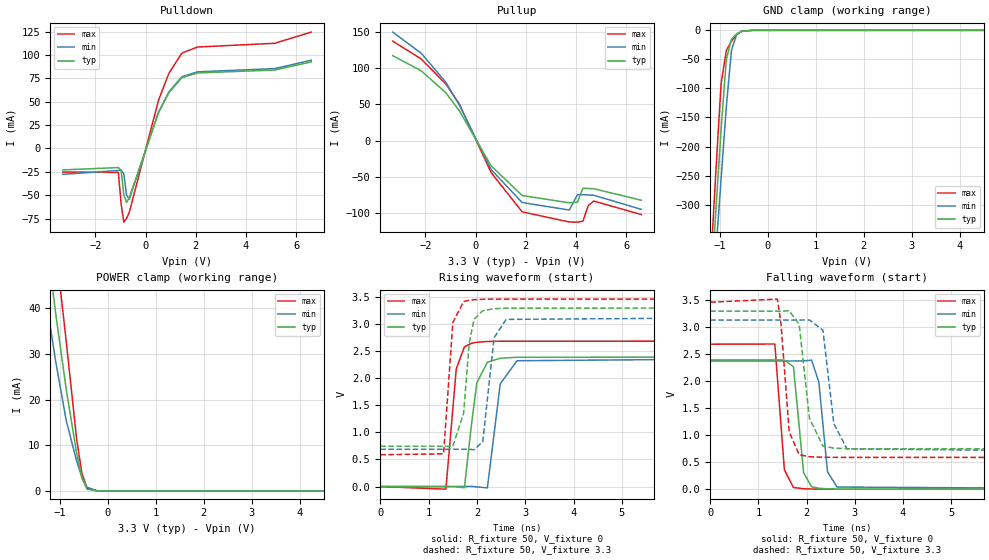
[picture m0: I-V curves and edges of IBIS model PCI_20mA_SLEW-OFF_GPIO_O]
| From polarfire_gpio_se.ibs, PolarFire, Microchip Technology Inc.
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|   Model PCI_20mA_SLEW-OFF_GPIO_O
[Model]   PCI_20mA_SLEW-OFF_GPIO_O
Model_type   Output
Polarity   Non-Inverting
Enable   Active-High
Cref =   5p
Rref =   25
|   typ   min   max
C_comp_pullup   2.605e-12   2.605e-12   2.76e-12
C_comp_pulldown  2.605e-12   2.605e-12   2.76e-12
| Vmeas and Vref depend on the measuring edge
| Rising Edge, uncomment the following
Vmeas =   0.9405V
Vref =   0.000V
| Falling Edge, uncomment the following
|Vmeas =   2.0295V
|Vref =   3.300V
[Model Spec]
Vmeas_rising   0.9405V   0.8934V   0.9875V
Vref_rising   0.000V   0.000V   0.000V
Vmeas_falling   2.0295V   1.9280V   2.1309V
Vref_falling   3.300V   3.135V   3.465V
[Temperature Range]  25C   100C   -40C
[Voltage Range]  3.3   3.135   3.465
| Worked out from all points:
|   slope of the pulldown table from 0 to 0.495 V, typ, clamps not added: 13.4 ohm
|   slope of the pullup table from 0 to 0.495 V, typ, clamps not added: 17.3 ohm
|   GND clamp passes 1 mA (typ) near -0.51 V on its own axis
|   POWER clamp passes 1 mA (typ) near -0.46 V on its own axis
|   rising waveform, R_fixture 50, V_fixture 0: 20-80 % time 180ps typ, 184ps min, 138ps max; typ from 0 V to 2.39 V
|   rising waveform, R_fixture 50, V_fixture 3.3: 20-80 % time 145ps typ, 168ps min, 109ps max; typ from 0.745 V to 3.3 V
|   falling waveform, R_fixture 50, V_fixture 0: 20-80 % time 128ps typ, 142ps min, 96.9ps max; typ from 2.39 V to 0 V
|   falling waveform, R_fixture 50, V_fixture 3.3: 20-80 % time 192ps typ, 194ps min, 144ps max; typ from 3.3 V to 0.745 V
[GND Clamp]
| Voltage   I(typ)   I(min)   I(max)
-3.3V     -3.213A    -2.957A    -3.541A
-1.191V   -450mA     -505.3mA   -401.1mA
-1.083V   -310.2mA   -380.8mA   -242.7mA
-974.5mV  -170.4mA   -256.4mA   -91.54mA
-866.2mV  -50.48mA   -132.2mA   -34.88mA
-758mV    -15.08mA   -34.24mA   -18.56mA
-649.7mV  -5.883mA   -6.714mA   -7.365mA
-541.4mV  -1.389mA   -1.466mA   -1.709mA
-324.8mV  -3.553uA   -9.504uA   -2.339uA
6.6V      0A         0A         0A
[POWER Clamp]
| Voltage   I(typ)   I(min)   I(max)
-3.3V     320.3mA    266.4mA    379mA
-1.624V   89.11mA    69.3mA     113.8mA
-1.408V   67.23mA    51.37mA    87.82mA
-1.299V   57.08mA    43.14mA    75.67mA
-1.191V   47.51mA    35.38mA    63.94mA
-1.083V   38.51mA    28.09mA    52.96mA
-866.2mV  22.14mA    15.36mA    32.61mA
-649.7mV  8.213mA    6.528mA    11.28mA
-541.4mV  2.791mA    3.019mA    3.88mA
-433.1mV  359.8uA    815.7uA    615.5uA
-216.6mV  159.8nA    4.578uA    2.748uA
6.6V      0A         0A         0A
[Pullup]
| Voltage   I(typ)   I(min)   I(max)
-3.3V     117mA      149.5mA    137mA
-2.166V   96.15mA    120.4mA    112.5mA
-1.191V   66.14mA    80.61mA    78.16mA
-649.7mV  41.23mA    49.17mA    50.55mA
618.8mV   -34.87mA   -39.98mA   -44.1mA
1.856V    -75.75mA   -85.44mA   -98.28mA
3.733V    -85.83mA   -95.77mA   -112.2mA
4.058V    -84.98mA   -74.55mA   -112.5mA
4.275V    -65.71mA   -74.6mA    -111.1mA
4.491V    -66.04mA   -74.99mA   -89.28mA
4.708V    -66.38mA   -75.37mA   -83.39mA
6.6V      -82.26mA   -94.83mA   -102mA
[Pulldown]
| Voltage   I(typ)   I(min)   I(max)
-3.3V     -22.95mA   -27.72mA   -25.22mA
-1.083V   -20.45mA   -23.58mA   -25.68mA
-974.5mV  -23.56mA   -23.09mA   -59.29mA
-866.2mV  -49.58mA   -27.1mA    -78.93mA
-758mV    -57.79mA   -49.98mA   -74.96mA
-649.7mV  -52.66mA   -54.3mA    -68.46mA
515.6mV   38.32mA    38.87mA    51.68mA
928.1mV   59.63mA    60.53mA    80.39mA
1.444V    75.7mA     76.75mA    102.1mA
2.062V    80.85mA    82.04mA    108.6mA
5.141V    83.98mA    85.49mA    112.6mA
6.6V      92.71mA    94.49mA    124.6mA
[Ramp]
dV/dt_r   1.43642/0.180403n  1.42548/0.18362n  1.61223/0.137715n
dV/dt_f   1.53328/0.192092n  1.46781/0.19408n  1.72588/0.143667n
R_load = 50
[Rising Waveform]
R_fixture = 50
V_fixture = 0
V_fixture_min = 0
V_fixture_max = 0
| Time   V(typ)   V(min)   V(max)
0s        32.7nV     23.65nV    88.85nV
1.358ns   758.9uV    498.5uV    -48.53mV
1.573ns   -5.442mV   577.4uV    2.174V
1.741ns   -23.01mV   639.1uV    2.581V
1.886ns   1.136V     2.761mV    2.648V
1.998ns   1.918V     -5.65mV    2.666V
2.217ns   2.298V     -25.15mV   2.681V
2.483ns   2.371V     1.897V     2.686V
2.83ns    2.389V     2.325V     2.686V
10ns      2.394V     2.376V     2.687V
[Rising Waveform]
R_fixture = 50
V_fixture = 3.3
V_fixture_min = 3.135
V_fixture_max = 3.465
| Time   V(typ)   V(min)   V(max)
0s        744.5mV    688.6mV    588.5mV
1.31ns    744.8mV    689.2mV    603.4mV
1.502ns   741.6mV    689.3mV    3.033V
1.725ns   1.357V     689.4mV    3.419V
1.84ns    2.649V     689.6mV    3.443V
1.941ns   3.093V     680.1mV    3.453V
2.121ns   3.25V      830.4mV    3.461V
2.356ns   3.287V     2.752V     3.464V
2.604ns   3.296V     3.089V     3.465V
10ns      3.3V       3.135V     3.465V
[Falling Waveform]
R_fixture = 50
V_fixture = 0
V_fixture_min = 0
V_fixture_max = 0
| Time   V(typ)   V(min)   V(max)
0s        2.394V     2.376V     2.687V
1.34ns    2.394V     2.376V     2.691V
1.538ns   2.394V     2.376V     357.7mV
1.726ns   2.271V     2.376V     30.74mV
1.937ns   303.7mV    2.377V     8.074mV
2.103ns   44.1mV     2.392V     3.21mV
2.253ns   16.72mV    1.987V     1.497mV
2.433ns   6.341mV    323.4mV    704.6uV
2.629ns   2.511mV    39.81mV    686.3uV
10ns      499.5nV    2.786uV    152.4nV
[Falling Waveform]
R_fixture = 50
V_fixture = 3.3
V_fixture_min = 3.135
V_fixture_max = 3.465
| Time   V(typ)   V(min)   V(max)
0s        3.3V       3.135V     3.465V
1.393ns   3.299V     3.135V     3.524V
1.467ns   3.299V     3.135V     3.078V
1.638ns   3.308V     3.135V     1.062V
1.846ns   3.051V     3.135V     639mV
2.058ns   1.314V     3.137V     601.6mV
2.338ns   799.5mV    2.947V     591.6mV
2.565ns   760.8mV    1.213V     589.5mV
2.838ns   749mV      747.2mV    588.8mV
10ns      744.5mV    688.6mV    588.5mV
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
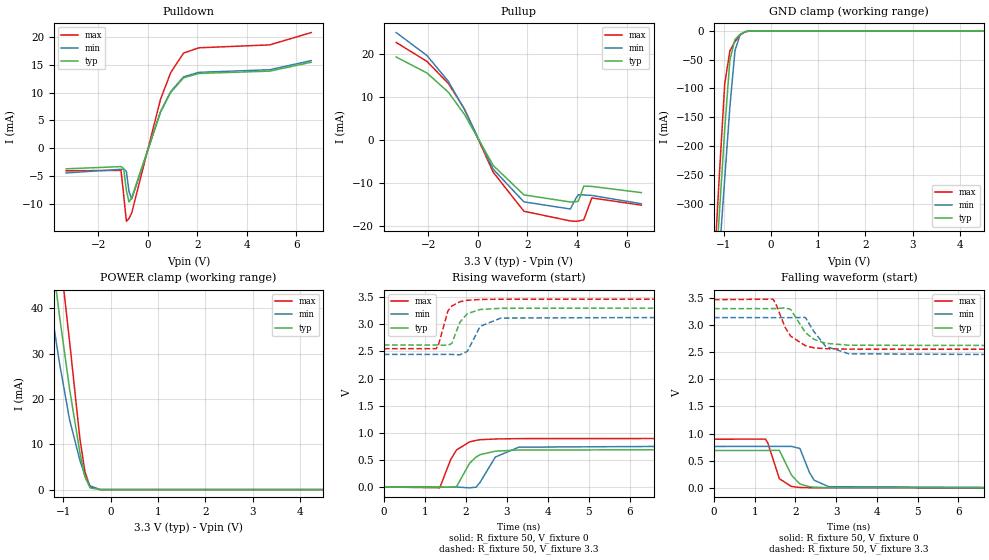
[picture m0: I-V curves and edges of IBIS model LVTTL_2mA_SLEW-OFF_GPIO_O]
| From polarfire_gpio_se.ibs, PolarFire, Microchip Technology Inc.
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|   Model LVTTL_2mA_SLEW-OFF_GPIO_O
[Model]   LVTTL_2mA_SLEW-OFF_GPIO_O
Model_type   Output
Polarity   Non-Inverting
Enable   Active-High
Vmeas =   1.65
Cref =   5p
Rref =   1M
|   typ   min   max
C_comp_pullup   2.605e-12   2.605e-12   2.76e-12
C_comp_pulldown  2.605e-12   2.605e-12   2.76e-12
[Temperature Range]  25C   100C   -40C
[Voltage Range]  3.3   3.135   3.465
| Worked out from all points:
|   slope of the pulldown table from 0 to 0.495 V, typ, clamps not added: 78.7 ohm
|   slope of the pullup table from 0 to 0.495 V, typ, clamps not added: 102 ohm
|   GND clamp passes 1 mA (typ) near -0.51 V on its own axis
|   POWER clamp passes 1 mA (typ) near -0.46 V on its own axis
|   rising waveform, R_fixture 50, V_fixture 0: 20-80 % time 366ps typ, 413ps min, 340ps max; typ from 0 V to 0.688 V
|   rising waveform, R_fixture 50, V_fixture 3.3: 20-80 % time 263ps typ, 317ps min, 225ps max; typ from 2.62 V to 3.3 V
|   falling waveform, R_fixture 50, V_fixture 0: 20-80 % time 276ps typ, 261ps min, 231ps max; typ from 0.688 V to 0 V
|   falling waveform, R_fixture 50, V_fixture 3.3: 20-80 % time 419ps typ, 425ps min, 393ps max; typ from 3.3 V to 2.62 V
[GND Clamp]
| Voltage   I(typ)   I(min)   I(max)
-3.3V     -3.213A    -2.957A    -3.542A
-1.191V   -450mA     -505.3mA   -401.1mA
-1.083V   -310.2mA   -380.8mA   -242.7mA
-974.5mV  -170.4mA   -256.4mA   -91.54mA
-866.2mV  -50.48mA   -132.2mA   -34.88mA
-758mV    -15.08mA   -34.24mA   -18.56mA
-649.7mV  -5.883mA   -6.714mA   -7.365mA
-541.4mV  -1.389mA   -1.466mA   -1.709mA
-433.1mV  -123uA     -170uA     -145.5uA
-108.3mV  -6.015nA   -17.98nA   -17.62nA
6.6V      0A         0A         0A
[POWER Clamp]
| Voltage   I(typ)   I(min)   I(max)
-3.3V     320.3mA    266.4mA    379mA
-1.624V   89.11mA    69.3mA     113.8mA
-1.408V   67.23mA    51.37mA    87.82mA
-1.299V   57.08mA    43.14mA    75.67mA
-1.191V   47.51mA    35.38mA    63.94mA
-1.083V   38.51mA    28.09mA    52.96mA
-866.2mV  22.14mA    15.36mA    32.61mA
-649.7mV  8.213mA    6.528mA    11.28mA
-541.4mV  2.791mA    3.019mA    3.88mA
-433.1mV  359.8uA    815.7uA    615.5uA
-216.6mV  159.8nA    4.578uA    2.748uA
6.6V      0A         0A         0A
[Pullup]
| Voltage   I(typ)   I(min)   I(max)
-3.3V     19.29mA    24.96mA    22.66mA
-2.057V   15.58mA    19.63mA    18.26mA
-1.191V   11.1mA     13.61mA    13.12mA
-541.4mV  5.944mA    7.057mA    7.214mA
618.8mV   -5.885mA   -6.76mA    -7.46mA
1.856V    -12.7mA    -14.32mA   -16.49mA
3.733V    -14.35mA   -15.98mA   -18.75mA
3.95V     -14.29mA   -13.56mA   -18.83mA
4.058V    -14.15mA   -12.66mA   -18.76mA
4.275V    -10.66mA   -12.72mA   -18.48mA
4.599V    -10.74mA   -12.82mA   -13.41mA
6.6V      -12.17mA   -14.77mA   -15.08mA
[Pulldown]
| Voltage   I(typ)   I(min)   I(max)
-3.3V     -3.739mA   -4.486mA   -4.094mA
-1.083V   -3.336mA   -3.821mA   -4.025mA
-974.5mV  -3.682mA   -3.744mA   -8.434mA
-866.2mV  -7.63mA    -4.182mA   -13.21mA
-758mV    -9.724mA   -7.867mA   -12.69mA
-649.7mV  -8.948mA   -9.182mA   -11.69mA
515.6mV   6.515mA    6.609mA    8.847mA
928.1mV   10.07mA    10.23mA    13.65mA
1.444V    12.7mA     12.87mA    17.16mA
2.062V    13.48mA    13.68mA    18.11mA
4.924V    13.9mA     14.15mA    18.64mA
6.6V      15.5mA     15.8mA     20.86mA
[Ramp]
dV/dt_r   0.412661/0.366321n  0.457095/0.413405n  0.537475/0.340225n
dV/dt_f   0.408767/0.418814n  0.413823/0.424708n  0.548259/0.392834n
R_load = 50
[Rising Waveform]
R_fixture = 50
V_fixture = 0
V_fixture_min = 0
V_fixture_max = 0
| Time   V(typ)   V(min)   V(max)
0s        102.4nV    74.64nV    311nV
1.362ns   -768.9uV   110.2uV    -13.21mV
1.625ns   -3.459mV   131.4uV    501.1mV
1.77ns    4.766mV    143.1uV    683mV
2.089ns   438.2mV    -15.31mV   832.3mV
2.25ns    554.7mV    -1.884mV   861mV
2.35ns    597.8mV    92.23mV    872.8mV
2.717ns   660.7mV    552.7mV    885.7mV
3.29ns    683.4mV    735.1mV    892.8mV
10ns      687.8mV    761.8mV    895.8mV
[Rising Waveform]
R_fixture = 50
V_fixture = 3.3
V_fixture_min = 3.135
V_fixture_max = 3.465
| Time   V(typ)   V(min)   V(max)
0s        2.619V     2.445V     2.551V
1.274ns   2.618V     2.445V     2.551V
1.331ns   2.618V     2.445V     2.624V
1.562ns   2.614V     2.445V     3.25V
1.656ns   2.648V     2.445V     3.337V
1.853ns   3.039V     2.438V     3.417V
2.035ns   3.198V     2.501V     3.444V
2.348ns   3.274V     2.964V     3.459V
2.854ns   3.296V     3.116V     3.464V
10ns      3.3V       3.135V     3.465V
[Falling Waveform]
R_fixture = 50
V_fixture = 0
V_fixture_min = 0
V_fixture_max = 0
| Time   V(typ)   V(min)   V(max)
0s        687.8mV    762.1mV    895.8mV
1.265ns   688.1mV    762.7mV    898.4mV
1.325ns   688.2mV    762.7mV    818.8mV
1.604ns   691.6mV    762.8mV    168.7mV
1.902ns   235.6mV    763mV      25.15mV
2.109ns   70.55mV    726.5mV    7.988mV
2.343ns   20.89mV    286mV      3.215mV
2.46ns    12.75mV    140.2mV    827.8uV
2.819ns   2.226mV    21.21mV    439.8uV
10ns      534.1nV    -354nV     399.4nV
[Falling Waveform]
R_fixture = 50
V_fixture = 3.3
V_fixture_min = 3.135
V_fixture_max = 3.465
| Time   V(typ)   V(min)   V(max)
0s        3.3V       3.135V     3.465V
1.448ns   3.301V     3.134V     3.475V
1.51ns    3.301V     3.134V     3.404V
1.745ns   3.315V     3.134V     2.956V
1.883ns   3.285V     3.134V     2.792V
2.244ns   2.859V     3.138V     2.618V
2.45ns    2.737V     2.881V     2.579V
2.742ns   2.661V     2.606V     2.563V
3.314ns   2.626V     2.468V     2.554V
10ns      2.619V     2.445V     2.551V
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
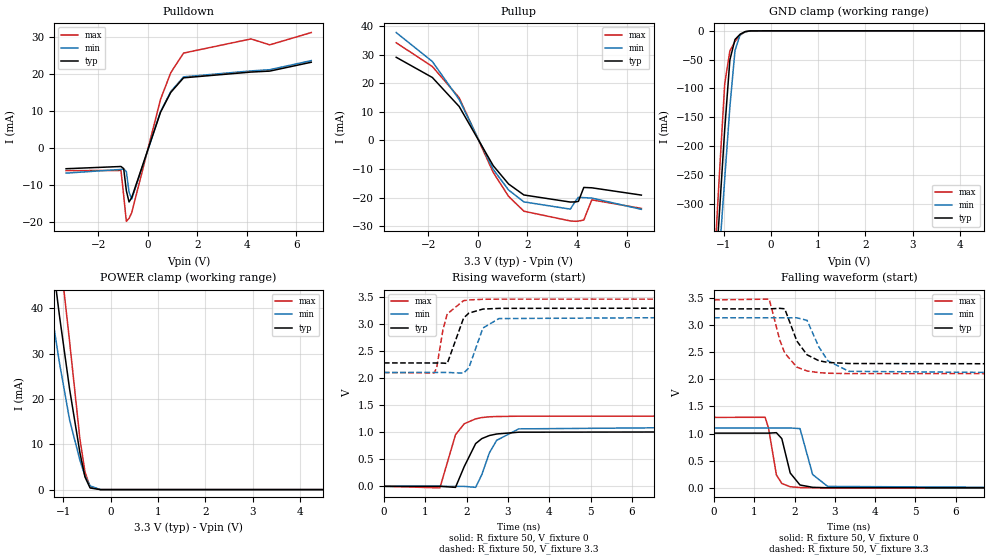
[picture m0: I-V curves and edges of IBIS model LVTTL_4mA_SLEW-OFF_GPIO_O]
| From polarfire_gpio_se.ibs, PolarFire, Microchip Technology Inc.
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|   Model LVTTL_4mA_SLEW-OFF_GPIO_O
[Model]   LVTTL_4mA_SLEW-OFF_GPIO_O
Model_type   Output
Polarity   Non-Inverting
Enable   Active-High
Vmeas =   1.65
Cref =   5p
Rref =   1M
|   typ   min   max
C_comp_pullup   2.605e-12   2.605e-12   2.76e-12
C_comp_pulldown  2.605e-12   2.605e-12   2.76e-12
[Temperature Range]  25C   100C   -40C
[Voltage Range]  3.3   3.135   3.465
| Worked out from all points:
|   slope of the pulldown table from 0 to 0.495 V, typ, clamps not added: 52.5 ohm
|   slope of the pullup table from 0 to 0.495 V, typ, clamps not added: 68.4 ohm
|   GND clamp passes 1 mA (typ) near -0.51 V on its own axis
|   POWER clamp passes 1 mA (typ) near -0.46 V on its own axis
|   rising waveform, R_fixture 50, V_fixture 0: 20-80 % time 367ps typ, 397ps min, 326ps max; typ from 0 V to 1.01 V
|   rising waveform, R_fixture 50, V_fixture 3.3: 20-80 % time 265ps typ, 289ps min, 217ps max; typ from 2.28 V to 3.3 V
|   falling waveform, R_fixture 50, V_fixture 0: 20-80 % time 211ps typ, 238ps min, 171ps max; typ from 1.01 V to 0 V
|   falling waveform, R_fixture 50, V_fixture 3.3: 20-80 % time 391ps typ, 456ps min, 364ps max; typ from 3.3 V to 2.28 V
[GND Clamp]
| Voltage   I(typ)   I(min)   I(max)
-3.3V     -3.213A    -2.957A    -3.542A
-1.191V   -450mA     -505.3mA   -401.1mA
-1.083V   -310.2mA   -380.8mA   -242.7mA
-974.5mV  -170.4mA   -256.4mA   -91.54mA
-866.2mV  -50.48mA   -132.2mA   -34.88mA
-758mV    -15.08mA   -34.24mA   -18.56mA
-649.7mV  -5.883mA   -6.714mA   -7.365mA
-541.4mV  -1.389mA   -1.466mA   -1.709mA
-433.1mV  -123uA     -170uA     -145.5uA
-108.3mV  -6.015nA   -17.98nA   -17.62nA
6.6V      0A         0A         0A
[POWER Clamp]
| Voltage   I(typ)   I(min)   I(max)
-3.3V     320.3mA    266.4mA    379mA
-1.624V   89.11mA    69.3mA     113.8mA
-1.408V   67.23mA    51.37mA    87.82mA
-1.299V   57.08mA    43.14mA    75.67mA
-1.191V   47.51mA    35.38mA    63.94mA
-1.083V   38.51mA    28.09mA    52.96mA
-866.2mV  22.14mA    15.36mA    32.61mA
-649.7mV  8.213mA    6.528mA    11.28mA
-541.4mV  2.791mA    3.019mA    3.88mA
-433.1mV  359.8uA    815.7uA    615.5uA
-216.6mV  159.8nA    4.578uA    2.748uA
6.6V      0A         0A         0A
[Pullup]
| Voltage   I(typ)   I(min)   I(max)
-3.3V     29.06mA    37.69mA    34.14mA
-1.841V   22mA       27.59mA    25.83mA
-758mV    11.88mA    14.29mA    14.95mA
618.8mV   -8.81mA    -10.12mA   -11.17mA
1.238V    -15.2mA    -17.29mA   -19.51mA
1.856V    -19.03mA   -21.44mA   -24.7mA
3.733V    -21.5mA    -23.97mA   -28.1mA
3.95V     -21.43mA   -20.97mA   -28.22mA
4.058V    -21.25mA   -19.85mA   -28.14mA
4.275V    -16.4mA    -19.95mA   -27.77mA
4.599V    -16.52mA   -20.11mA   -20.73mA
6.6V      -19.07mA   -24.04mA   -23.71mA
[Pulldown]
| Voltage   I(typ)   I(min)   I(max)
-3.3V     -5.571mA   -6.764mA   -6.091mA
-1.083V   -4.968mA   -5.761mA   -6.034mA
-974.5mV  -5.532mA   -5.644mA   -12.81mA
-866.2mV  -11.51mA   -6.329mA   -19.8mA
-758mV    -14.57mA   -11.89mA   -19mA
-649.7mV  -13.39mA   -13.75mA   -17.48mA
515.6mV   9.754mA    9.89mA     13.24mA
928.1mV   15.09mA    15.32mA    20.43mA
1.444V    19.03mA    19.29mA    25.73mA
4.166V    20.59mA    20.9mA     29.56mA
4.924V    20.85mA    21.23mA    27.96mA
6.6V      23.25mA    23.69mA    31.28mA
[Ramp]
dV/dt_r   0.605265/0.366908n  0.662241/0.396996n  0.779577/0.325652n
dV/dt_f   0.60978/0.39101n  0.616355/0.456454n  0.815846/0.36434n
R_load = 50
[Rising Waveform]
R_fixture = 50
V_fixture = 0
V_fixture_min = 0
V_fixture_max = 0
| Time   V(typ)   V(min)   V(max)
0s        84.25nV    61.34nV    248.1nV
1.353ns   861.7uV    -559.1uV   -28.54mV
1.731ns   -19.52mV   -715.3uV   954.6mV
1.942ns   365mV      -1.097mV   1.158V
2.218ns   790.4mV    -19.14mV   1.249V
2.367ns   882.9mV    215.3mV    1.273V
2.551ns   940.4mV    619.5mV    1.287V
2.727ns   968.5mV    851.9mV    1.292V
3.262ns   1.002V     1.063V     1.298V
10ns      1.009V     1.104V     1.299V
[Rising Waveform]
R_fixture = 50
V_fixture = 3.3
V_fixture_min = 3.135
V_fixture_max = 3.465
| Time   V(typ)   V(min)   V(max)
0s        2.284V     2.108V     2.105V
1.219ns   2.283V     2.108V     2.1V
1.278ns   2.283V     2.108V     2.207V
1.427ns   2.281V     2.108V     2.896V
1.532ns   2.275V     2.108V     3.192V
1.927ns   3.115V     2.095V     3.437V
2.054ns   3.206V     2.193V     3.45V
2.394ns   3.281V     2.93V      3.462V
2.782ns   3.294V     3.105V     3.465V
10ns      3.3V       3.135V     3.465V
[Falling Waveform]
R_fixture = 50
V_fixture = 0
V_fixture_min = 0
V_fixture_max = 0
| Time   V(typ)   V(min)   V(max)
0s        1.009V     1.104V     1.299V
1.268ns   1.009V     1.104V     1.301V
1.355ns   1.009V     1.104V     1.096V
1.548ns   1.017V     1.104V     240.3mV
1.683ns   906.7mV    1.104V     80.15mV
1.892ns   273.8mV    1.104V     20.41mV
2.135ns   52.58mV    1.092V     5.632mV
2.449ns   10.09mV    245.9mV    1.124mV
2.823ns   2.058mV    26.29mV    127.2uV
10ns      1.187uV    2.702uV    -287.6nV
[Falling Waveform]
R_fixture = 50
V_fixture = 3.3
V_fixture_min = 3.135
V_fixture_max = 3.465
| Time   V(typ)   V(min)   V(max)
0s        3.3V       3.135V     3.465V
1.37ns    3.299V     3.135V     3.479V
1.633ns   3.309V     3.134V     2.723V
1.755ns   3.301V     3.134V     2.486V
2.057ns   2.706V     3.135V     2.225V
2.309ns   2.453V     3.088V     2.155V
2.605ns   2.343V     2.596V     2.124V
2.827ns   2.312V     2.341V     2.113V
3.35ns    2.292V     2.148V     2.106V
10ns      2.284V     2.108V     2.105V
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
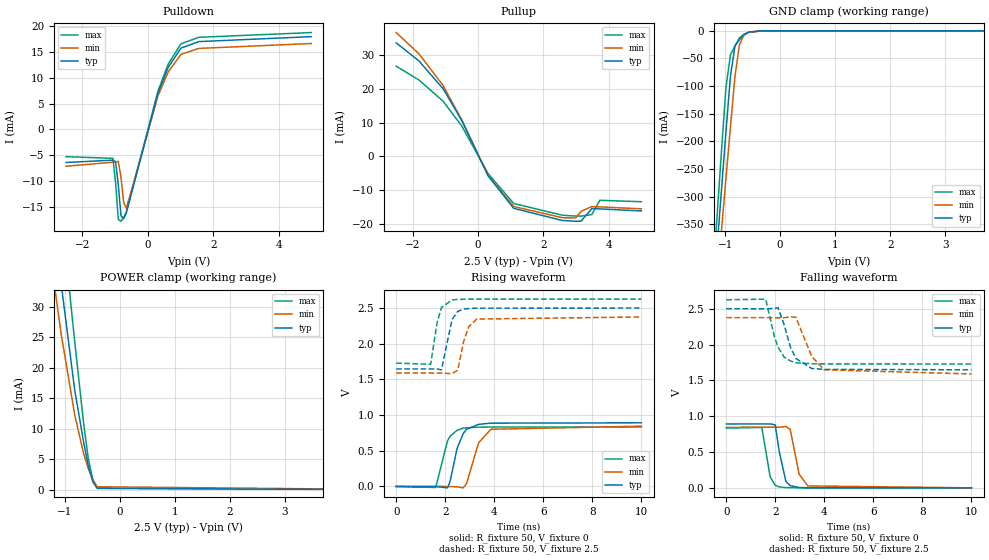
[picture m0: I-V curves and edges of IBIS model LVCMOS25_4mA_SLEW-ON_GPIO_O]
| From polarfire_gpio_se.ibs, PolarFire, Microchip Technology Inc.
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|   Model LVCMOS25_4mA_SLEW-ON_GPIO_O
[Model]   LVCMOS25_4mA_SLEW-ON_GPIO_O
Model_type   Output
Polarity   Non-Inverting
Enable   Active-High
Vmeas =   1.25
Cref =   5p
Rref =   1M
|   typ   min   max
C_comp_pullup   2.605e-12   2.605e-12   2.76e-12
C_comp_pulldown  2.605e-12   2.605e-12   2.76e-12
[Temperature Range]  25C   100C   -40C
[Voltage Range]  2.5   2.375   2.625
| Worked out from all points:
|   slope of the pulldown table from 0 to 0.375 V, typ, clamps not added: 45.8 ohm
|   slope of the pullup table from 0 to 0.375 V, typ, clamps not added: 55 ohm
|   GND clamp passes 1 mA (typ) near -0.51 V on its own axis
|   POWER clamp passes 1 mA (typ) near -0.47 V on its own axis
|   rising waveform, R_fixture 50, V_fixture 0: 20-80 % time 419ps typ, 487ps min, 380ps max; typ from 0 V to 0.892 V
|   rising waveform, R_fixture 50, V_fixture 2.5: 20-80 % time 291ps typ, 341ps min, 263ps max; typ from 1.65 V to 2.5 V
|   falling waveform, R_fixture 50, V_fixture 0: 20-80 % time 250ps typ, 301ps min, 214ps max; typ from 0.892 V to 0 V
|   falling waveform, R_fixture 50, V_fixture 2.5: 20-80 % time 492ps typ, 592ps min, 435ps max; typ from 2.5 V to 1.65 V
[GND Clamp]
| Voltage   I(typ)   I(min)   I(max)
-2.5V     -2.154A    -2.019A    -2.334A
-1.23V    -500.9mA   -550.5mA   -458.7mA
-1.148V   -394.9mA   -456.3mA   -338.7mA
-1.066V   -289mA     -362mA     -218.7mA
-984.4mV  -183.1mA   -267.7mA   -102.9mA
-902.3mV  -82.21mA   -173.6mA   -43.25mA
-820.3mV  -27.37mA   -82.26mA   -27.26mA
-738.3mV  -12.87mA   -24.95mA   -16.13mA
-656.2mV  -6.285mA   -7.324mA   -7.886mA
-574.2mV  -2.342mA   -2.429mA   -2.872mA
-328.1mV  -3.985uA   -10.42uA   -2.675uA
5V        0A         0A         0A
[POWER Clamp]
| Voltage   I(typ)   I(min)   I(max)
-2.5V     191.3mA    155.6mA    232.6mA
-1.559V   79.6mA     61.42mA    102.5mA
-1.395V   63.37mA    48.38mA    82.85mA
-1.23V    48.04mA    36.4mA     63.67mA
-1.148V   40.77mA    30.8mA     54.53mA
-1.066V   33.71mA    25.51mA    45.88mA
-820.3mV  16.31mA    12.25mA    24.25mA
-656.2mV  7.665mA    5.818mA    10.67mA
-574.2mV  3.929mA    3.48mA     5.131mA
-492.2mV  1.272mA    1.622mA    1.634mA
-410.2mV  189.8uA    467.6uA    244.4uA
5V        0A         0A         0A
[Pullup]
| Voltage   I(typ)   I(min)   I(max)
-2.5V     33.62mA    36.67mA    26.72mA
-1.805V   28.27mA    30.39mA    22.62mA
-1.066V   20.05mA    20.99mA    16.34mA
-492.2mV  10.57mA    10.75mA    8.939mA
312.5mV   -5.798mA   -5.683mA   -5.138mA
1.094V    -15.4mA    -14.86mA   -13.96mA
2.582V    -18.99mA   -18.17mA   -17.44mA
2.992V    -19.24mA   -18.24mA   -17.69mA
3.156V    -19.2mA    -16.28mA   -17.71mA
3.484V    -15.48mA   -14.88mA   -17.24mA
3.73V     -15.57mA   -14.97mA   -13.02mA
5V        -16.17mA   -15.55mA   -13.44mA
[Pulldown]
| Voltage   I(typ)   I(min)   I(max)
-2.5V     -6.418mA   -7.144mA   -5.286mA
-1.066V   -5.955mA   -6.36mA    -5.613mA
-984.4mV  -6.289mA   -6.263mA   -10.4mA
-902.3mV  -10.75mA   -6.223mA   -17.43mA
-820.3mV  -16.74mA   -9.245mA   -17.81mA
-738.3mV  -17.3mA    -14.16mA   -17.08mA
-656.2mV  -16.13mA   -15.3mA    -16.02mA
312.5mV   7.039mA    6.513mA    7.432mA
625mV     12.05mA    11.15mA    12.69mA
1.016V    15.75mA    14.54mA    16.59mA
1.562V    17.01mA    15.69mA    17.84mA
5V        17.97mA    16.64mA    18.76mA
[Ramp]
dV/dt_r   0.535034/0.418696n  0.507143/0.486984n  0.50036/0.379991n
dV/dt_f   0.511775/0.492134n  0.470942/0.592329n  0.537693/0.434764n
R_load = 50
[Rising Waveform]
R_fixture = 50
V_fixture = 0
V_fixture_min = 0
V_fixture_max = 0
| Time   V(typ)   V(min)   V(max)
0s        21.03nV    38.43nV    26.87nV
1.611ns   -542.2uV   -604.4uV   -13.97mV
2.093ns   -18.93mV   -785.2uV   638.2mV
2.194ns   64.68mV    -823.1uV   703.1mV
2.484ns   534.4mV    -4.776mV   788.2mV
2.731ns   740.7mV    -19.36mV   817.1mV
2.87ns    801.6mV    41.5mV     822.1mV
3.361ns   870.6mV    612.8mV    831.1mV
3.864ns   887.5mV    801.5mV    832.9mV
10ns      891.7mV    845.2mV    833.9mV
[Rising Waveform]
R_fixture = 50
V_fixture = 2.5
V_fixture_min = 2.375
V_fixture_max = 2.625
| Time   V(typ)   V(min)   V(max)
0s        1.647V     1.59V      1.729V
1.404ns   1.647V     1.59V      1.712V
1.668ns   1.647V     1.59V      2.295V
1.845ns   1.633V     1.59V      2.507V
2.276ns   2.337V     1.58V      2.613V
2.51ns    2.454V     1.631V     2.621V
2.753ns   2.485V     2.033V     2.623V
2.953ns   2.493V     2.237V     2.625V
3.285ns   2.498V     2.346V     2.625V
10ns      2.5V       2.375V     2.625V
[Falling Waveform]
R_fixture = 50
V_fixture = 0
V_fixture_min = 0
V_fixture_max = 0
| Time   V(typ)   V(min)   V(max)
0s        891.7mV    845.2mV    834mV
1.446ns   892.4mV    845.7mV    843.7mV
1.788ns   892.6mV    845.8mV    153mV
1.995ns   879.4mV    845.9mV    36.17mV
2.157ns   509.9mV    845.9mV    13.22mV
2.431ns   87.39mV    857.2mV    3.48mV
2.604ns   30.6mV     815.3mV    1.515mV
2.969ns   5.435mV    189.9mV    561.2uV
3.323ns   1.359mV    27.09mV    532.9uV
10ns      985.3nV    5.259uV    494.1nV
[Falling Waveform]
R_fixture = 50
V_fixture = 2.5
V_fixture_min = 2.375
V_fixture_max = 2.625
| Time   V(typ)   V(min)   V(max)
0s        2.5V       2.375V     2.625V
1.606ns   2.499V     2.375V     2.634V
1.963ns   2.505V     2.374V     2.106V
2.109ns   2.515V     2.374V     1.965V
2.36ns    2.275V     2.374V     1.823V
2.621ns   1.958V     2.388V     1.77V
2.836ns   1.807V     2.38V      1.747V
3.483ns   1.666V     1.833V     1.731V
3.991ns   1.654V     1.647V     1.73V
10ns      1.647V     1.59V      1.729V
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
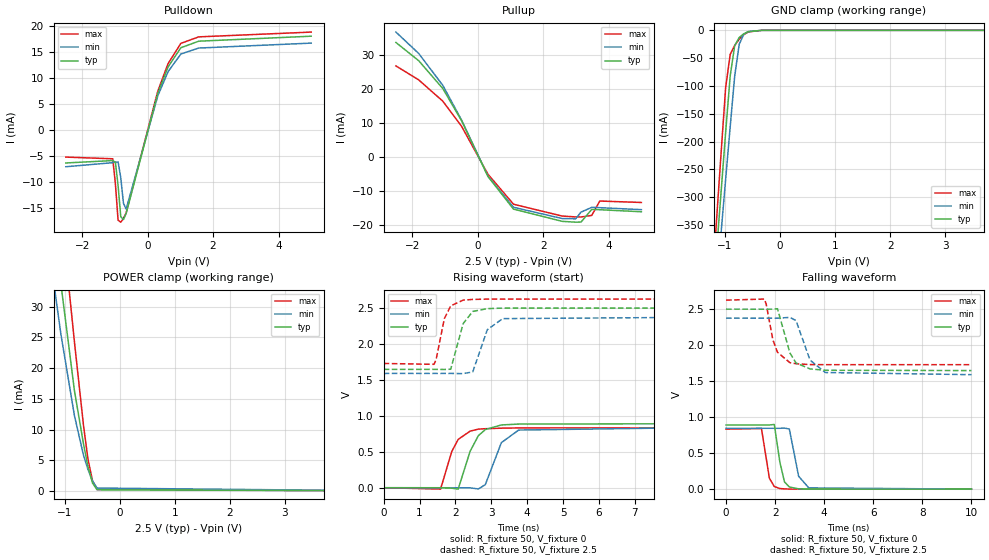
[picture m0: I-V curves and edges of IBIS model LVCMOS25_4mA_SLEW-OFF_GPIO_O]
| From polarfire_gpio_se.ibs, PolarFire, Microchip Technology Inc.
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|   Model LVCMOS25_4mA_SLEW-OFF_GPIO_O
[Model]   LVCMOS25_4mA_SLEW-OFF_GPIO_O
Model_type   Output
Polarity   Non-Inverting
Enable   Active-High
Vmeas =   1.25
Cref =   5p
Rref =   1M
|   typ   min   max
C_comp_pullup   2.605e-12   2.605e-12   2.76e-12
C_comp_pulldown  2.605e-12   2.605e-12   2.76e-12
[Temperature Range]  25C   100C   -40C
[Voltage Range]  2.5   2.375   2.625
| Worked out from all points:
|   slope of the pulldown table from 0 to 0.375 V, typ, clamps not added: 45.8 ohm
|   slope of the pullup table from 0 to 0.375 V, typ, clamps not added: 55 ohm
|   GND clamp passes 1 mA (typ) near -0.51 V on its own axis
|   POWER clamp passes 1 mA (typ) near -0.47 V on its own axis
|   rising waveform, R_fixture 50, V_fixture 0: 20-80 % time 390ps typ, 436ps min, 352ps max; typ from 0 V to 0.892 V
|   rising waveform, R_fixture 50, V_fixture 2.5: 20-80 % time 281ps typ, 330ps min, 252ps max; typ from 1.65 V to 2.5 V
|   falling waveform, R_fixture 50, V_fixture 0: 20-80 % time 228ps typ, 279ps min, 195ps max; typ from 0.892 V to 0 V
|   falling waveform, R_fixture 50, V_fixture 2.5: 20-80 % time 453ps typ, 532ps min, 387ps max; typ from 2.5 V to 1.65 V
[GND Clamp]
| Voltage   I(typ)   I(min)   I(max)
-2.5V     -2.154A    -2.019A    -2.334A
-1.23V    -500.9mA   -550.5mA   -458.7mA
-1.148V   -394.9mA   -456.3mA   -338.7mA
-1.066V   -289mA     -362mA     -218.7mA
-984.4mV  -183.1mA   -267.7mA   -102.9mA
-902.3mV  -82.21mA   -173.6mA   -43.25mA
-820.3mV  -27.37mA   -82.26mA   -27.26mA
-738.3mV  -12.87mA   -24.95mA   -16.13mA
-656.2mV  -6.285mA   -7.324mA   -7.886mA
-574.2mV  -2.342mA   -2.429mA   -2.872mA
-328.1mV  -3.985uA   -10.42uA   -2.675uA
5V        0A         0A         0A
[POWER Clamp]
| Voltage   I(typ)   I(min)   I(max)
-2.5V     191.3mA    155.6mA    232.6mA
-1.559V   79.6mA     61.42mA    102.5mA
-1.395V   63.37mA    48.38mA    82.85mA
-1.23V    48.04mA    36.4mA     63.67mA
-1.148V   40.77mA    30.8mA     54.53mA
-1.066V   33.71mA    25.51mA    45.88mA
-820.3mV  16.31mA    12.25mA    24.25mA
-656.2mV  7.665mA    5.818mA    10.67mA
-574.2mV  3.929mA    3.48mA     5.131mA
-492.2mV  1.272mA    1.622mA    1.634mA
-410.2mV  189.8uA    467.6uA    244.4uA
5V        0A         0A         0A
[Pullup]
| Voltage   I(typ)   I(min)   I(max)
-2.5V     33.62mA    36.67mA    26.72mA
-1.805V   28.27mA    30.39mA    22.62mA
-1.066V   20.05mA    20.99mA    16.34mA
-492.2mV  10.57mA    10.75mA    8.939mA
312.5mV   -5.798mA   -5.683mA   -5.138mA
1.094V    -15.4mA    -14.86mA   -13.96mA
2.582V    -18.99mA   -18.17mA   -17.44mA
2.992V    -19.24mA   -18.24mA   -17.69mA
3.156V    -19.2mA    -16.28mA   -17.71mA
3.484V    -15.48mA   -14.88mA   -17.24mA
3.73V     -15.57mA   -14.97mA   -13.02mA
5V        -16.17mA   -15.55mA   -13.44mA
[Pulldown]
| Voltage   I(typ)   I(min)   I(max)
-2.5V     -6.418mA   -7.144mA   -5.286mA
-1.066V   -5.955mA   -6.36mA    -5.613mA
-984.4mV  -6.289mA   -6.263mA   -10.4mA
-902.3mV  -10.75mA   -6.223mA   -17.43mA
-820.3mV  -16.74mA   -9.245mA   -17.81mA
-738.3mV  -17.3mA    -14.16mA   -17.08mA
-656.2mV  -16.13mA   -15.3mA    -16.02mA
312.5mV   7.039mA    6.513mA    7.432mA
625mV     12.05mA    11.15mA    12.69mA
1.016V    15.75mA    14.54mA    16.59mA
1.562V    17.01mA    15.69mA    17.84mA
5V        17.97mA    16.64mA    18.76mA
[Ramp]
dV/dt_r   0.535015/0.390377n  0.507106/0.436038n  0.500376/0.352346n
dV/dt_f   0.511786/0.452645n  0.471144/0.531646n  0.537693/0.387269n
R_load = 50
[Rising Waveform]
R_fixture = 50
V_fixture = 0
V_fixture_min = 0
V_fixture_max = 0
| Time   V(typ)   V(min)   V(max)
0s        21.02nV    38.42nV    26.87nV
1.586ns   -481.1uV   -428uV     -18.7mV
1.898ns   -6.249mV   -512.2uV   503.6mV
2.076ns   -20.07mV   -560.2uV   671.9mV
2.41ns    507.1mV    -1.195mV   787.6mV
2.639ns   724.2mV    -17.63mV   814.9mV
2.833ns   808.9mV    42.98mV    821.1mV
3.281ns   873.5mV    627.2mV    828.5mV
3.762ns   885.6mV    802.5mV    832mV
10ns      891.7mV    845.2mV    834mV
[Rising Waveform]
R_fixture = 50
V_fixture = 2.5
V_fixture_min = 2.375
V_fixture_max = 2.625
| Time   V(typ)   V(min)   V(max)
0s        1.647V     1.59V      1.729V
1.404ns   1.647V     1.59V      1.717V
1.462ns   1.647V     1.59V      1.783V
1.692ns   1.645V     1.59V      2.353V
1.869ns   1.649V     1.59V      2.531V
2.215ns   2.283V     1.588V     2.61V
2.483ns   2.453V     1.611V     2.62V
2.888ns   2.492V     2.198V     2.624V
3.317ns   2.499V     2.353V     2.624V
10ns      2.5V       2.375V     2.625V
[Falling Waveform]
R_fixture = 50
V_fixture = 0
V_fixture_min = 0
V_fixture_max = 0
| Time   V(typ)   V(min)   V(max)
0s        891.7mV    845.2mV    834mV
1.443ns   891.7mV    845.3mV    841.8mV
1.765ns   891.7mV    845.3mV    152.9mV
1.966ns   897.9mV    845.3mV    36.37mV
2.195ns   370.4mV    845.3mV    8.919mV
2.381ns   101.6mV    848.5mV    3.865mV
2.579ns   29.96mV    834.5mV    1.519mV
2.957ns   4.79mV     179.6mV    137.9uV
3.373ns   605.4uV    17.59mV    129.8uV
10ns      1.18uV     4.561uV    473.6nV
[Falling Waveform]
R_fixture = 50
V_fixture = 2.5
V_fixture_min = 2.375
V_fixture_max = 2.625
| Time   V(typ)   V(min)   V(max)
0s        2.5V       2.375V     2.625V
1.565ns   2.499V     2.374V     2.64V
1.636ns   2.499V     2.374V     2.57V
1.907ns   2.5V       2.374V     2.075V
2.096ns   2.506V     2.374V     1.901V
2.603ns   1.891V     2.386V     1.756V
2.85ns    1.753V     2.341V     1.742V
3.422ns   1.67V      1.792V     1.73V
4.047ns   1.651V     1.62V      1.729V
10ns      1.647V     1.59V      1.729V
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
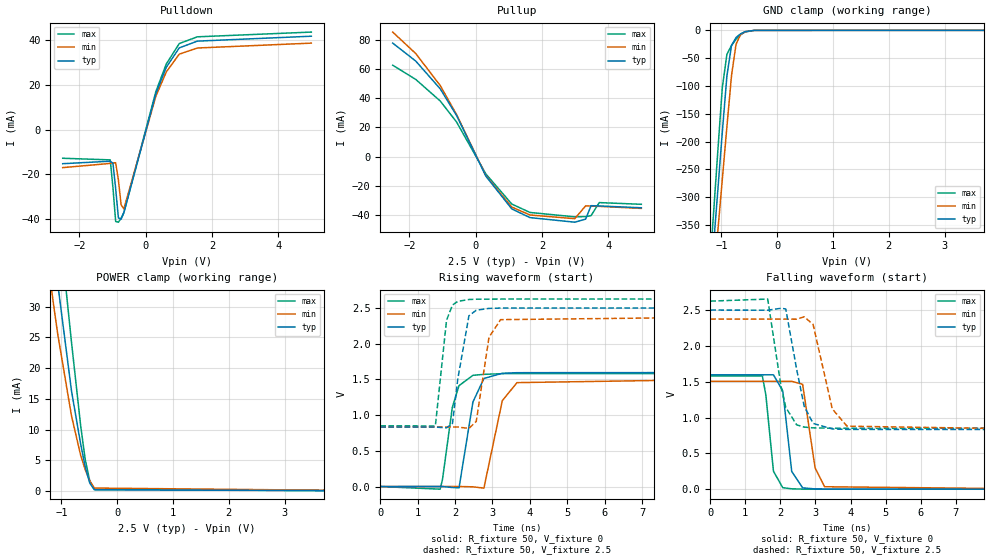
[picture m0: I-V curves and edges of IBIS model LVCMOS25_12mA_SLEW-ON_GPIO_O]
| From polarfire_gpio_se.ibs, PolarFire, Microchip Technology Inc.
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|   Model LVCMOS25_12mA_SLEW-ON_GPIO_O
[Model]   LVCMOS25_12mA_SLEW-ON_GPIO_O
Model_type   Output
Polarity   Non-Inverting
Enable   Active-High
Vmeas =   1.25
Cref =   5p
Rref =   1M
|   typ   min   max
C_comp_pullup   2.605e-12   2.605e-12   2.76e-12
C_comp_pulldown  2.605e-12   2.605e-12   2.76e-12
[Temperature Range]  25C   100C   -40C
[Voltage Range]  2.5   2.375   2.625
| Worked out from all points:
|   slope of the pulldown table from 0 to 0.375 V, typ, clamps not added: 19.8 ohm
|   slope of the pullup table from 0 to 0.375 V, typ, clamps not added: 23.7 ohm
|   GND clamp passes 1 mA (typ) near -0.51 V on its own axis
|   POWER clamp passes 1 mA (typ) near -0.47 V on its own axis
|   rising waveform, R_fixture 50, V_fixture 0: 20-80 % time 296ps typ, 344ps min, 278ps max; typ from 0 V to 1.6 V
|   rising waveform, R_fixture 50, V_fixture 2.5: 20-80 % time 229ps typ, 268ps min, 192ps max; typ from 0.833 V to 2.5 V
|   falling waveform, R_fixture 50, V_fixture 0: 20-80 % time 210ps typ, 255ps min, 188ps max; typ from 1.6 V to 0 V
|   falling waveform, R_fixture 50, V_fixture 2.5: 20-80 % time 366ps typ, 431ps min, 327ps max; typ from 2.5 V to 0.833 V
[GND Clamp]
| Voltage   I(typ)   I(min)   I(max)
-2.5V     -2.154A    -2.019A    -2.334A
-1.23V    -500.9mA   -550.5mA   -458.7mA
-1.148V   -394.9mA   -456.3mA   -338.7mA
-1.066V   -289mA     -362mA     -218.7mA
-984.4mV  -183.1mA   -267.7mA   -102.9mA
-902.3mV  -82.21mA   -173.6mA   -43.25mA
-820.3mV  -27.37mA   -82.26mA   -27.26mA
-738.3mV  -12.87mA   -24.95mA   -16.13mA
-656.2mV  -6.285mA   -7.324mA   -7.886mA
-574.2mV  -2.342mA   -2.429mA   -2.872mA
-410.2mV  -62.85uA   -96.5uA    -70.85uA
5V        0A         0A         0A
[POWER Clamp]
| Voltage   I(typ)   I(min)   I(max)
-2.5V     191.3mA    155.6mA    232.6mA
-1.559V   79.6mA     61.42mA    102.5mA
-1.395V   63.37mA    48.38mA    82.85mA
-1.23V    48.04mA    36.4mA     63.67mA
-1.148V   40.77mA    30.8mA     54.53mA
-1.066V   33.71mA    25.51mA    45.88mA
-820.3mV  16.31mA    12.25mA    24.25mA
-656.2mV  7.665mA    5.818mA    10.67mA
-574.2mV  3.929mA    3.48mA     5.131mA
-492.2mV  1.272mA    1.622mA    1.634mA
-410.2mV  189.8uA    467.6uA    244.4uA
5V        0A         0A         0A
[Pullup]
| Voltage   I(typ)   I(min)   I(max)
-2.5V     77.74mA    85.27mA    62.59mA
-1.805V   65.42mA    70.57mA    52.86mA
-1.066V   46.4mA     48.65mA    38.08mA
-574.2mV  28.18mA    28.85mA    23.73mA
312.5mV   -13.44mA   -13.17mA   -11.93mA
1.094V    -35.83mA   -34.55mA   -32.49mA
1.641V    -41.75mA   -39.96mA   -38.22mA
2.992V    -44.89mA   -42.49mA   -41.24mA
3.32V     -42.78mA   -33.71mA   -41.05mA
3.484V    -33.59mA   -33.85mA   -40.41mA
3.73V     -33.78mA   -34.05mA   -31.47mA
5V        -35.02mA   -35.45mA   -32.64mA
[Pulldown]
| Voltage   I(typ)   I(min)   I(max)
-2.5V     -15.27mA   -17.03mA   -12.83mA
-1.066V   -14.16mA   -15.15mA   -13.56mA
-984.4mV  -15.08mA   -14.92mA   -26mA
-902.3mV  -26.47mA   -14.85mA   -41.17mA
-820.3mV  -39.57mA   -22.52mA   -41.5mA
-738.3mV  -40.15mA   -33.68mA   -39.7mA
-656.2mV  -37.32mA   -35.53mA   -37.14mA
312.5mV   16.27mA    15.07mA    17.18mA
625mV     27.94mA    25.88mA    29.43mA
1.016V    36.65mA    33.84mA    38.59mA
1.562V    39.69mA    36.6mA     41.62mA
5V        41.89mA    38.79mA    43.74mA
[Ramp]
dV/dt_r   0.957456/0.296222n  0.903749/0.34386n  0.948665/0.27806n
dV/dt_f   1.0004/0.365865n  0.925306/0.431378n  1.06503/0.327114n
R_load = 50
[Rising Waveform]
R_fixture = 50
V_fixture = 0
V_fixture_min = 0
V_fixture_max = 0
| Time   V(typ)   V(min)   V(max)
0s        11.97nV    22.18nV    15.14nV
1.6ns     687.7uV    372.4uV    -36.88mV
1.663ns   714.8uV    387uV      94.99mV
1.927ns   -13.59mV   448.5uV    1.109V
2.106ns   -18.72mV   490.1uV    1.413V
2.478ns   1.184V     -4.286mV   1.557V
2.772ns   1.513V     -21.89mV   1.571V
3.263ns   1.586V     1.202V     1.58V
3.657ns   1.594V     1.455V     1.582V
10ns      1.596V     1.506V     1.581V
[Rising Waveform]
R_fixture = 50
V_fixture = 2.5
V_fixture_min = 2.375
V_fixture_max = 2.625
| Time   V(typ)   V(min)   V(max)
0s        832.7mV    832.8mV    850mV
1.473ns   832.4mV    833.3mV    848mV
1.772ns   821.7mV    833.4mV    2.328V
1.931ns   883.9mV    833.5mV    2.542V
2.074ns   1.509V     833.5mV    2.593V
2.371ns   2.391V     813.5mV    2.619V
2.568ns   2.469V     912.8mV    2.623V
2.908ns   2.494V     2.091V     2.624V
3.219ns   2.499V     2.337V     2.625V
10ns      2.5V       2.375V     2.625V
[Falling Waveform]
R_fixture = 50
V_fixture = 0
V_fixture_min = 0
V_fixture_max = 0
| Time   V(typ)   V(min)   V(max)
0s        1.596V     1.506V     1.581V
1.486ns   1.596V     1.506V     1.58V
1.585ns   1.596V     1.506V     1.316V
1.802ns   1.596V     1.505V     250.5mV
2.068ns   1.372V     1.505V     20.36mV
2.323ns   247.6mV    1.505V     4.963mV
2.634ns   18.8mV     1.464V     1.007mV
2.99ns    3.249mV    295.4mV    169.4uV
3.261ns   1.031mV    33.92mV    162.9uV
10ns      560.1nV    5.647uV    862.1nV
[Falling Waveform]
R_fixture = 50
V_fixture = 2.5
V_fixture_min = 2.375
V_fixture_max = 2.625
| Time   V(typ)   V(min)   V(max)
0s        2.5V       2.375V     2.625V
1.638ns   2.499V     2.374V     2.654V
2.015ns   2.525V     2.374V     1.442V
2.153ns   2.516V     2.374V     1.141V
2.464ns   1.672V     2.373V     897.9mV
2.679ns   1.158V     2.407V     867.2mV
2.933ns   917.9mV    2.299V     855.9mV
3.48ns    840.8mV    1.12V      850.6mV
3.9ns     834.2mV    879.3mV    849.9mV
10ns      832.7mV    832.8mV    850mV
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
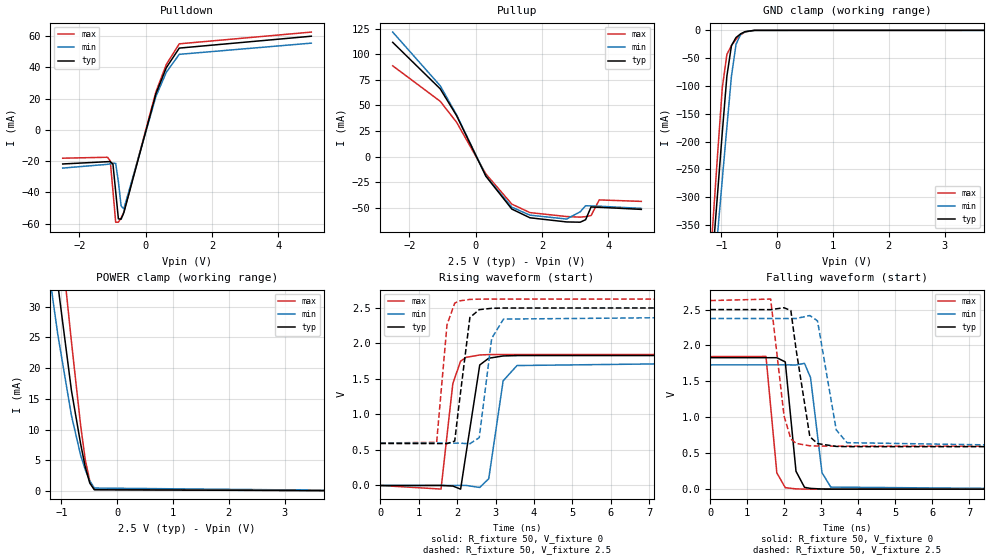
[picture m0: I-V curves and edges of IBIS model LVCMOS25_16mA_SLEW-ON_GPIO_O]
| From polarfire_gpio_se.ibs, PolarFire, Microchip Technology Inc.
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|   Model LVCMOS25_16mA_SLEW-ON_GPIO_O
[Model]   LVCMOS25_16mA_SLEW-ON_GPIO_O
Model_type   Output
Polarity   Non-Inverting
Enable   Active-High
Vmeas =   1.25
Cref =   5p
Rref =   1M
|   typ   min   max
C_comp_pullup   2.605e-12   2.605e-12   2.76e-12
C_comp_pulldown  2.605e-12   2.605e-12   2.76e-12
[Temperature Range]  25C   100C   -40C
[Voltage Range]  2.5   2.375   2.625
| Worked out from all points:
|   slope of the pulldown table from 0 to 0.375 V, typ, clamps not added: 14 ohm
|   slope of the pullup table from 0 to 0.375 V, typ, clamps not added: 16.7 ohm
|   GND clamp passes 1 mA (typ) near -0.51 V on its own axis
|   POWER clamp passes 1 mA (typ) near -0.47 V on its own axis
|   rising waveform, R_fixture 50, V_fixture 0: 20-80 % time 231ps typ, 264ps min, 211ps max; typ from 0 V to 1.83 V
|   rising waveform, R_fixture 50, V_fixture 2.5: 20-80 % time 208ps typ, 241ps min, 167ps max; typ from 0.591 V to 2.5 V
|   falling waveform, R_fixture 50, V_fixture 0: 20-80 % time 182ps typ, 229ps min, 154ps max; typ from 1.83 V to 0 V
|   falling waveform, R_fixture 50, V_fixture 2.5: 20-80 % time 272ps typ, 330ps min, 246ps max; typ from 2.5 V to 0.591 V
[GND Clamp]
| Voltage   I(typ)   I(min)   I(max)
-2.5V     -2.154A    -2.019A    -2.334A
-1.23V    -500.9mA   -550.5mA   -458.7mA
-1.148V   -394.9mA   -456.3mA   -338.7mA
-1.066V   -289mA     -362mA     -218.7mA
-984.4mV  -183.1mA   -267.7mA   -102.9mA
-902.3mV  -82.21mA   -173.6mA   -43.25mA
-820.3mV  -27.37mA   -82.26mA   -27.26mA
-738.3mV  -12.87mA   -24.95mA   -16.13mA
-656.2mV  -6.285mA   -7.324mA   -7.886mA
-574.2mV  -2.342mA   -2.429mA   -2.872mA
-410.2mV  -62.85uA   -96.5uA    -70.85uA
5V        0A         0A         0A
[POWER Clamp]
| Voltage   I(typ)   I(min)   I(max)
-2.5V     191.3mA    155.6mA    232.6mA
-1.559V   79.6mA     61.42mA    102.5mA
-1.395V   63.37mA    48.38mA    82.85mA
-1.23V    48.04mA    36.4mA     63.67mA
-1.148V   40.77mA    30.8mA     54.53mA
-1.066V   33.71mA    25.51mA    45.88mA
-820.3mV  16.31mA    12.25mA    24.25mA
-656.2mV  7.665mA    5.818mA    10.67mA
-574.2mV  3.929mA    3.48mA     5.131mA
-492.2mV  1.272mA    1.622mA    1.634mA
-410.2mV  189.8uA    467.6uA    244.4uA
5V        0A         0A         0A
[Pullup]
| Voltage   I(typ)   I(min)   I(max)
-2.5V     111.6mA    121.6mA    88.7mA
-1.066V   66.19mA    69.19mA    54.05mA
-574.2mV  40.12mA    40.97mA    33.68mA
312.5mV   -19.13mA   -18.73mA   -16.95mA
1.094V    -51.1mA    -49.25mA   -46.28mA
1.641V    -59.61mA   -57.05mA   -54.54mA
2.746V    -63.65mA   -60.83mA   -58.39mA
3.156V    -63.9mA    -53.75mA   -58.96mA
3.32V     -61.47mA   -47.84mA   -58.47mA
3.484V    -49.07mA   -48.02mA   -57.43mA
3.73V     -49.35mA   -48.31mA   -42.17mA
5V        -51.4mA    -50.43mA   -43.6mA
[Pulldown]
| Voltage   I(typ)   I(min)   I(max)
-2.5V     -21.8mA    -24.42mA   -18.1mA
-1.148V   -20.34mA   -22.02mA   -17.51mA
-1.066V   -20.22mA   -21.71mA   -19.77mA
-984.4mV  -21.89mA   -21.38mA   -38.99mA
-902.3mV  -39.28mA   -21.4mA    -58.99mA
-820.3mV  -56.85mA   -33.15mA   -58.99mA
-738.3mV  -57.05mA   -48.61mA   -56.33mA
-656.2mV  -52.91mA   -50.5mA    -52.6mA
312.5mV   23.07mA    21.38mA    24.31mA
625mV     39.7mA     36.79mA    41.76mA
1.016V    52.23mA    48.24mA    54.96mA
5V        59.82mA    55.4mA     62.46mA
[Ramp]
dV/dt_r   1.09823/0.231334n  1.03825/0.263871n  1.10671/0.211375n
dV/dt_f   1.1454/0.272269n  1.06754/0.329666n  1.21584/0.245885n
R_load = 50
[Rising Waveform]
R_fixture = 50
V_fixture = 0
V_fixture_min = 0
V_fixture_max = 0
| Time   V(typ)   V(min)   V(max)
0s        9.068nV    16.86nV    11.45nV
1.581ns   637.6uV    685uV      -50.13mV
1.889ns   -7.759mV   818.4uV    1.437V
2.091ns   -51.72mV   905.9uV    1.751V
2.232ns   447.6mV    967uV      1.804V
2.589ns   1.697V     -27.63mV   1.838V
2.823ns   1.792V     95.17mV    1.843V
3.198ns   1.824V     1.474V     1.844V
3.559ns   1.829V     1.689V     1.844V
10ns      1.83V      1.73V      1.845V
[Rising Waveform]
R_fixture = 50
V_fixture = 2.5
V_fixture_min = 2.375
V_fixture_max = 2.625
| Time   V(typ)   V(min)   V(max)
0s        591mV      595.8mV    598.6mV
1.467ns   590.8mV    596.3mV    607.4mV
1.737ns   589.4mV    596.4mV    2.264V
1.938ns   626.1mV    596.5mV    2.567V
2.038ns   1.088V     596.5mV    2.597V
2.332ns   2.365V     587.9mV    2.62V
2.576ns   2.476V     673.4mV    2.624V
2.9ns     2.495V     2.071V     2.625V
3.207ns   2.499V     2.343V     2.625V
10ns      2.5V       2.375V     2.625V
[Falling Waveform]
R_fixture = 50
V_fixture = 0
V_fixture_min = 0
V_fixture_max = 0
| Time   V(typ)   V(min)   V(max)
0s        1.83V      1.73V      1.845V
1.506ns   1.83V      1.73V      1.847V
1.799ns   1.83V      1.73V      226.8mV
2.027ns   1.771V     1.73V      20.76mV
2.317ns   249.1mV    1.729V     3.925mV
2.547ns   25.59mV    1.751V     1.176mV
2.71ns    10.65mV    1.553V     651uV
3.02ns    2.263mV    229.2mV    63.3uV
3.257ns   851.4uV    28.73mV    61.17uV
10ns      206nV      5.448uV    645nV
[Falling Waveform]
R_fixture = 50
V_fixture = 2.5
V_fixture_min = 2.375
V_fixture_max = 2.625
| Time   V(typ)   V(min)   V(max)
0s        2.5V       2.375V     2.625V
1.632ns   2.499V     2.375V     2.646V
1.994ns   2.525V     2.375V     1.018V
2.178ns   2.486V     2.375V     698.9mV
2.319ns   1.946V     2.375V     636.8mV
2.691ns   730.7mV    2.417V     603.8mV
2.899ns   634.6mV    2.342V     600.6mV
3.404ns   595mV      825.8mV    598.8mV
3.696ns   592.2mV    647.1mV    598.6mV
10ns      591mV      595.8mV    598.6mV
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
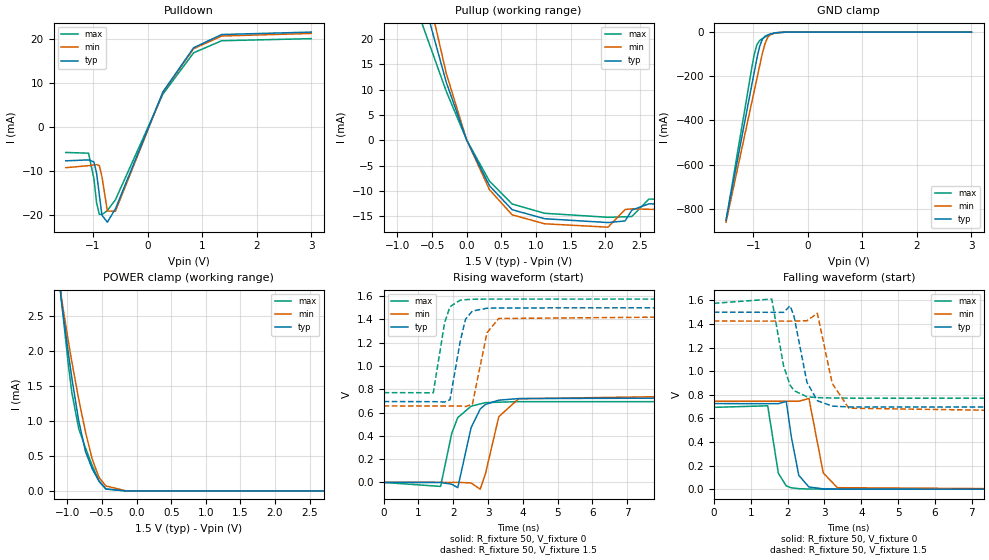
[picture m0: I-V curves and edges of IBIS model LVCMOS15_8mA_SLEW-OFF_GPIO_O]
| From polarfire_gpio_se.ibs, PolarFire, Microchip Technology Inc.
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|   Model LVCMOS15_8mA_SLEW-OFF_GPIO_O
[Model]   LVCMOS15_8mA_SLEW-OFF_GPIO_O
Model_type   Output
Polarity   Non-Inverting
Enable   Active-High
Vmeas =   0.75
Cref =   5p
Rref =   1M
|   typ   min   max
C_comp_pullup   2.605e-12   2.605e-12   2.76e-12
C_comp_pulldown  2.605e-12   2.605e-12   2.76e-12
[Temperature Range]  25C   100C   -40C
[Voltage Range]  1.5   1.425   1.575
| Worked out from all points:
|   slope of the pulldown table from 0 to 0.225 V, typ, clamps not added: 34.2 ohm
|   slope of the pullup table from 0 to 0.225 V, typ, clamps not added: 34 ohm
|   GND clamp passes 1 mA (typ) near -0.52 V on its own axis
|   POWER clamp passes 1 mA (typ) near -0.84 V on its own axis
|   rising waveform, R_fixture 50, V_fixture 0: 20-80 % time 383ps typ, 401ps min, 350ps max; typ from 0 V to 0.725 V
|   rising waveform, R_fixture 50, V_fixture 1.5: 20-80 % time 280ps typ, 308ps min, 259ps max; typ from 0.694 V to 1.5 V
|   falling waveform, R_fixture 50, V_fixture 0: 20-80 % time 233ps typ, 283ps min, 193ps max; typ from 0.725 V to 0 V
|   falling waveform, R_fixture 50, V_fixture 1.5: 20-80 % time 324ps typ, 330ps min, 295ps max; typ from 1.5 V to 0.694 V
[GND Clamp]
| Voltage   I(typ)   I(min)   I(max)
-1.5V     -849.7mA   -860.2mA   -853.5mA
-1.034V   -246.6mA   -324.3mA   -170.7mA
-984.4mV  -183.1mA   -267.7mA   -102.9mA
-935.2mV  -119.9mA   -211.2mA   -57.59mA
-885.9mV  -66.33mA   -154.7mA   -38.94mA
-836.7mV  -33.59mA   -99.09mA   -29.82mA
-787.5mV  -19.44mA   -53.53mA   -22.49mA
-738.3mV  -12.87mA   -24.95mA   -16.13mA
-689.1mV  -8.545mA   -11.57mA   -10.81mA
-590.6mV  -2.947mA   -3.067mA   -3.621mA
-393.7mV  -37.64uA   -63.17uA   -40.12uA
3V        0A         0A         0A
[POWER Clamp]
| Voltage   I(typ)   I(min)   I(max)
-1.5V     10.9mA     9.757mA    12.4mA
-1.181V   3.55mA     3.502mA    3.75mA
-1.083V   2.694mA    2.748mA    2.703mA
-984.4mV  1.956mA    2.133mA    1.792mA
-935.2mV  1.615mA    1.848mA    1.408mA
-836.7mV  1.007mA    1.316mA    894.8uA
-738.3mV  562.1uA    843.7uA    616.9uA
-639.8mV  314.2uA    451.1uA    357.6uA
-541.4mV  134.7uA    190.1uA    142.2uA
-443mV    26.83uA    70.8uA     28.29uA
-147.7mV  138.9nA    173.8nA    970.8pA
3V        0A         0A         0A
[Pullup]
| Voltage   I(typ)   I(min)   I(max)
-1.5V     70.01mA    84.98mA    53.82mA
-1.181V   55.46mA    66mA       43.49mA
-295.3mV  11.42mA    13.18mA    9.637mA
0V        -138.7nA   12.43uA    20.68uA
328.1mV   -8.987mA   -9.76mA    -8.073mA
656.2mV   -13.72mA   -14.73mA   -12.6mA
1.125V    -15.5mA    -16.5mA    -14.43mA
2.041V    -16.26mA   -17.17mA   -15.22mA
2.288V    -15.94mA   -13.69mA   -15.12mA
2.386V    -13.79mA   -13.55mA   -15.06mA
2.632V    -12.56mA   -13.64mA   -11.62mA
3V        -12.67mA   -13.76mA   -11.72mA
[Pulldown]
| Voltage   I(typ)   I(min)   I(max)
-1.5V     -7.654mA   -9.205mA   -5.749mA
-1.083V   -7.43mA    -8.749mA   -5.909mA
-984.4mV  -7.883mA   -8.59mA    -11.7mA
-935.2mV  -10.5mA    -8.502mA   -17.22mA
-885.9mV  -15.31mA   -8.737mA   -19.78mA
-836.7mV  -20.02mA   -11.27mA   -19.87mA
-738.3mV  -21.59mA   -19.05mA   -18.94mA
-590.6mV  -18.57mA   -19.11mA   -16.51mA
281.2mV   8.019mA    7.924mA    7.527mA
843.8mV   18.05mA    17.82mA    16.9mA
1.359V    21.05mA    20.71mA    19.64mA
3V        21.6mA     21.29mA    20.11mA
[Ramp]
dV/dt_r   0.435212/0.383072n  0.447544/0.40119n  0.416049/0.349615n
dV/dt_f   0.483314/0.323801n  0.460744/0.330442n  0.482132/0.295487n
R_load = 50
[Rising Waveform]
R_fixture = 50
V_fixture = 0
V_fixture_min = 0
V_fixture_max = 0
| Time   V(typ)   V(min)   V(max)
0s        14.78nV    20.59nV    20.51nV
1.636ns   -677.1uV   642.8uV    -34.32mV
1.957ns   -15.22mV   768.9uV    421.9mV
2.13ns    -45.11mV   836.8uV    556.9mV
2.512ns   469.6mV    -4.66mV    654.5mV
2.774ns   630.2mV    -57.95mV   674.4mV
2.925ns   670.2mV    74.06mV    685.2mV
3.309ns   706.4mV    564.9mV    689.3mV
3.879ns   720.3mV    718.8mV    693.7mV
10ns      725.4mV    745.9mV    693.4mV
[Rising Waveform]
R_fixture = 50
V_fixture = 1.5
V_fixture_min = 1.425
V_fixture_max = 1.575
| Time   V(typ)   V(min)   V(max)
0s        694.5mV    657.1mV    771.4mV
1.426ns   693.9mV    656.6mV    770mV
1.752ns   691mV      656.4mV    1.372V
1.906ns   709.2mV    656.4mV    1.509V
2.197ns   1.206V     656.3mV    1.565V
2.352ns   1.402V     652mV      1.57V
2.549ns   1.472V     671.2mV    1.573V
2.969ns   1.496V     1.285V     1.575V
3.306ns   1.499V     1.408V     1.575V
10ns      1.5V       1.425V     1.575V
[Falling Waveform]
R_fixture = 50
V_fixture = 0
V_fixture_min = 0
V_fixture_max = 0
| Time   V(typ)   V(min)   V(max)
0s        725.3mV    745.9mV    693.4mV
1.463ns   724.6mV    745.4mV    706.4mV
1.752ns   724.5mV    745.3mV    134.2mV
1.966ns   743.7mV    745.3mV    27.31mV
2.105ns   440mV      745.2mV    11.43mV
2.306ns   116.9mV    744.8mV    4.263mV
2.581ns   18.32mV    768.8mV    1.259mV
2.97ns    2.642mV    137mV      277.6uV
3.354ns   463uV      12.47mV    -1.484uV
10ns      645nV      3.921uV    819.8nV
[Falling Waveform]
R_fixture = 50
V_fixture = 1.5
V_fixture_min = 1.425
V_fixture_max = 1.575
| Time   V(typ)   V(min)   V(max)
0s        1.5V       1.425V     1.575V
1.573ns   1.499V     1.424V     1.611V
1.895ns   1.498V     1.424V     1.041V
2.07ns    1.554V     1.424V     882mV
2.176ns   1.465V     1.424V     835mV
2.528ns   904.1mV    1.427V     783.1mV
2.809ns   749.7mV    1.491V     775.9mV
3.211ns   704.2mV    897.3mV    772.5mV
3.661ns   696.7mV    686.1mV    771.5mV
10ns      694.5mV    657.1mV    771.4mV
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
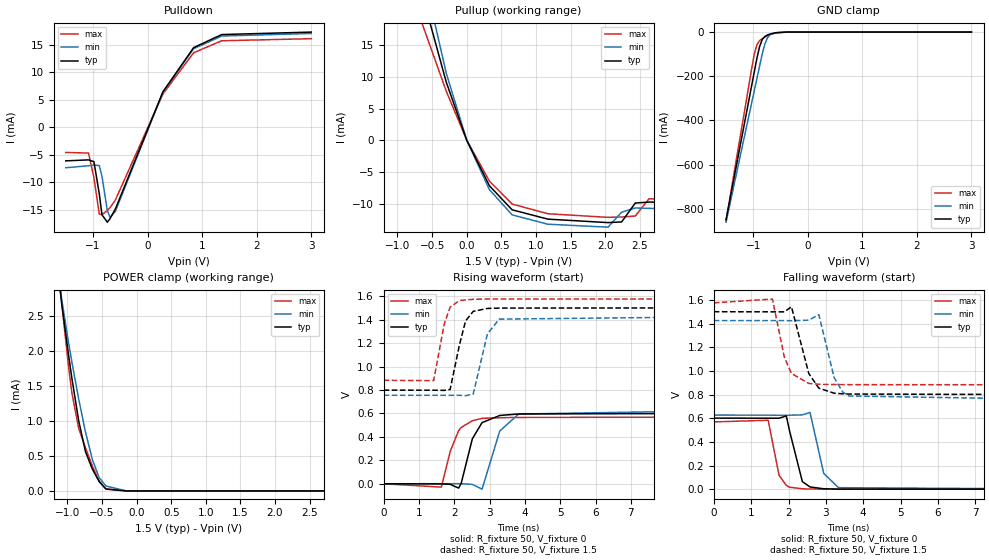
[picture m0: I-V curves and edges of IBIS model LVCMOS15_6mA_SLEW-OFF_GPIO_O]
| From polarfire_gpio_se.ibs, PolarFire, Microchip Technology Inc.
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|   Model LVCMOS15_6mA_SLEW-OFF_GPIO_O
[Model]   LVCMOS15_6mA_SLEW-OFF_GPIO_O
Model_type   Output
Polarity   Non-Inverting
Enable   Active-High
Vmeas =   0.75
Cref =   5p
Rref =   1M
|   typ   min   max
C_comp_pullup   2.605e-12   2.605e-12   2.76e-12
C_comp_pulldown  2.605e-12   2.605e-12   2.76e-12
[Temperature Range]  25C   100C   -40C
[Voltage Range]  1.5   1.425   1.575
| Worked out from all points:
|   slope of the pulldown table from 0 to 0.225 V, typ, clamps not added: 42.6 ohm
|   slope of the pullup table from 0 to 0.225 V, typ, clamps not added: 42.5 ohm
|   GND clamp passes 1 mA (typ) near -0.52 V on its own axis
|   POWER clamp passes 1 mA (typ) near -0.84 V on its own axis
|   rising waveform, R_fixture 50, V_fixture 0: 20-80 % time 391ps typ, 417ps min, 358ps max; typ from 0 V to 0.601 V
|   rising waveform, R_fixture 50, V_fixture 1.5: 20-80 % time 296ps typ, 324ps min, 269ps max; typ from 0.799 V to 1.5 V
|   falling waveform, R_fixture 50, V_fixture 0: 20-80 % time 245ps typ, 284ps min, 199ps max; typ from 0.601 V to 0 V
|   falling waveform, R_fixture 50, V_fixture 1.5: 20-80 % time 353ps typ, 341ps min, 309ps max; typ from 1.5 V to 0.799 V
[GND Clamp]
| Voltage   I(typ)   I(min)   I(max)
-1.5V     -849.7mA   -860.2mA   -853.5mA
-1.034V   -246.6mA   -324.3mA   -170.7mA
-984.4mV  -183.1mA   -267.7mA   -102.9mA
-935.2mV  -119.9mA   -211.2mA   -57.59mA
-885.9mV  -66.33mA   -154.7mA   -38.94mA
-836.7mV  -33.59mA   -99.09mA   -29.82mA
-787.5mV  -19.44mA   -53.53mA   -22.49mA
-738.3mV  -12.87mA   -24.95mA   -16.13mA
-689.1mV  -8.545mA   -11.57mA   -10.81mA
-590.6mV  -2.947mA   -3.067mA   -3.621mA
-393.7mV  -37.64uA   -63.17uA   -40.12uA
3V        0A         0A         0A
[POWER Clamp]
| Voltage   I(typ)   I(min)   I(max)
-1.5V     10.9mA     9.757mA    12.4mA
-1.181V   3.55mA     3.502mA    3.75mA
-1.083V   2.694mA    2.748mA    2.703mA
-984.4mV  1.956mA    2.133mA    1.792mA
-935.2mV  1.615mA    1.848mA    1.408mA
-836.7mV  1.007mA    1.316mA    894.8uA
-738.3mV  562.1uA    843.7uA    616.9uA
-639.8mV  314.2uA    451.1uA    357.6uA
-541.4mV  134.7uA    190.1uA    142.2uA
-443mV    26.83uA    70.8uA     28.29uA
-147.7mV  138.9nA    174nA      970.8pA
3V        0A         0A         0A
[Pullup]
| Voltage   I(typ)   I(min)   I(max)
-1.5V     56.04mA    68.02mA    43.12mA
-1.181V   44.42mA    52.88mA    34.86mA
-295.3mV  9.154mA    10.56mA    7.724mA
0V        -138.7nA   9.95uA     16.62uA
328.1mV   -7.199mA   -7.814mA   -6.465mA
656.2mV   -10.99mA   -11.79mA   -10.08mA
1.172V    -12.46mA   -13.26mA   -11.61mA
2.041V    -13.01mA   -13.73mA   -12.18mA
2.238V    -12.9mA    -11.36mA   -12.12mA
2.435V    -9.92mA    -10.7mA    -11.97mA
2.632V    -9.767mA   -10.76mA   -9.253mA
3V        -9.852mA   -10.86mA   -9.332mA
[Pulldown]
| Voltage   I(typ)   I(min)   I(max)
-1.5V     -6.142mA   -7.393mA   -4.616mA
-1.083V   -5.962mA   -7.027mA   -4.715mA
-984.4mV  -6.289mA   -6.899mA   -9.229mA
-885.9mV  -12.14mA   -6.99mA    -15.82mA
-836.7mV  -15.95mA   -8.973mA   -15.92mA
-738.3mV  -17.3mA    -15.2mA    -15.19mA
-689.1mV  -16.66mA   -16.43mA   -14.66mA
-590.6mV  -14.89mA   -15.32mA   -13.25mA
281.2mV   6.43mA     6.351mA    6.039mA
843.8mV   14.46mA    14.27mA    13.53mA
1.359V    16.84mA    16.57mA    15.71mA
3V        17.29mA    17.04mA    16.09mA
[Ramp]
dV/dt_r   0.360363/0.390669n  0.375538/0.416842n  0.341141/0.357648n
dV/dt_f   0.420878/0.353422n  0.402167/0.341363n  0.415505/0.308892n
R_load = 50
[Rising Waveform]
R_fixture = 50
V_fixture = 0
V_fixture_min = 0
V_fixture_max = 0
| Time   V(typ)   V(min)   V(max)
0s        16.87nV    23.49nV    23.32nV
1.632ns   -639uV     570.9uV    -28.05mV
1.883ns   -4.353mV   658.7uV    274.6mV
2.122ns   -36.45mV   742.3uV    453.4mV
2.196ns   4.193mV    768.2uV    480.5mV
2.511ns   383.3mV    -4.951mV   537.3mV
2.786ns   521.6mV    -45.76mV   558.3mV
3.288ns   582.6mV    450.5mV    563.1mV
3.822ns   595.4mV    594.6mV    565.8mV
10ns      600.6mV    625.9mV    568.6mV
[Rising Waveform]
R_fixture = 50
V_fixture = 1.5
V_fixture_min = 1.425
V_fixture_max = 1.575
| Time   V(typ)   V(min)   V(max)
0s        798.6mV    754.7mV    882.5mV
1.416ns   797.9mV    754.6mV    879.4mV
1.717ns   796.4mV    754.5mV    1.364V
1.882ns   804mV      754.5mV    1.506V
2.147ns   1.186V     754.5mV    1.562V
2.32ns    1.389V     751.2mV    1.568V
2.536ns   1.47V      765.4mV    1.573V
2.938ns   1.495V     1.278V     1.575V
3.273ns   1.498V     1.404V     1.575V
10ns      1.5V       1.425V     1.575V
[Falling Waveform]
R_fixture = 50
V_fixture = 0
V_fixture_min = 0
V_fixture_max = 0
| Time   V(typ)   V(min)   V(max)
0s        600.6mV    625.9mV    568.6mV
1.456ns   599.8mV    625.4mV    582.5mV
1.746ns   599.6mV    625.3mV    118.6mV
1.941ns   619.1mV    625.2mV    31.74mV
2.029ns   491.5mV    625.2mV    16.87mV
2.371ns   63.53mV    627.9mV    2.911mV
2.576ns   18.6mV     648.6mV    1.434mV
2.943ns   3.141mV    132.9mV    13.83uV
3.338ns   715.9uV    12.66mV    13.03uV
10ns      -761.9nV   4.056uV    -446.1nV
[Falling Waveform]
R_fixture = 50
V_fixture = 1.5
V_fixture_min = 1.425
V_fixture_max = 1.575
| Time   V(typ)   V(min)   V(max)
0s        1.5V       1.425V     1.575V
1.57ns    1.499V     1.425V     1.607V
1.89ns    1.499V     1.425V     1.115V
2.079ns   1.542V     1.424V     978.2mV
2.544ns   976.4mV    1.429V     893.4mV
2.812ns   854mV      1.475V     886.4mV
3.221ns   811.3mV    944.2mV    884.5mV
3.444ns   806mV      823.7mV    883.8mV
3.613ns   804mV      787.7mV    883.5mV
10ns      798.5mV    754.7mV    882.5mV
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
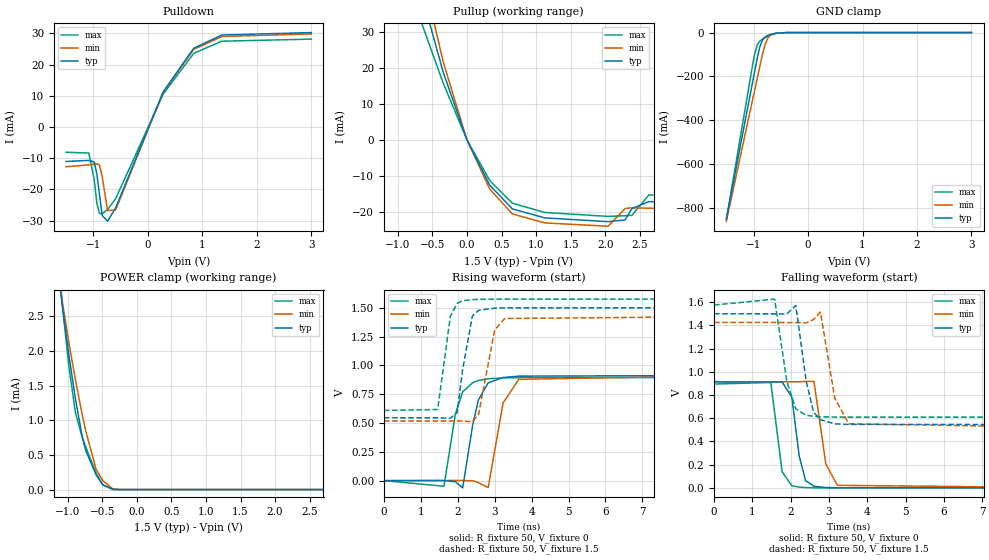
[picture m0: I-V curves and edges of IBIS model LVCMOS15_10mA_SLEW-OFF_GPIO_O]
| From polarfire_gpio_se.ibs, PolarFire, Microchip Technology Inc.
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|   Model LVCMOS15_10mA_SLEW-OFF_GPIO_O
[Model]   LVCMOS15_10mA_SLEW-OFF_GPIO_O
Model_type   Output
Polarity   Non-Inverting
Enable   Active-High
Vmeas =   0.75
Cref =   5p
Rref =   1M
|   typ   min   max
C_comp_pullup   2.605e-12   2.605e-12   2.76e-12
C_comp_pulldown  2.605e-12   2.605e-12   2.76e-12
[Temperature Range]  25C   100C   -40C
[Voltage Range]  1.5   1.425   1.575
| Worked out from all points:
|   slope of the pulldown table from 0 to 0.225 V, typ, clamps not added: 24.5 ohm
|   slope of the pullup table from 0 to 0.225 V, typ, clamps not added: 24.4 ohm
|   GND clamp passes 1 mA (typ) near -0.52 V on its own axis
|   POWER clamp passes 1 mA (typ) near -0.84 V on its own axis
|   rising waveform, R_fixture 50, V_fixture 0: 20-80 % time 320ps typ, 328ps min, 306ps max; typ from 0 V to 0.913 V
|   rising waveform, R_fixture 50, V_fixture 1.5: 20-80 % time 240ps typ, 311ps min, 216ps max; typ from 0.545 V to 1.5 V
|   falling waveform, R_fixture 50, V_fixture 0: 20-80 % time 223ps typ, 248ps min, 188ps max; typ from 0.913 V to 0 V
|   falling waveform, R_fixture 50, V_fixture 1.5: 20-80 % time 248ps typ, 279ps min, 255ps max; typ from 1.5 V to 0.545 V
[GND Clamp]
| Voltage   I(typ)   I(min)   I(max)
-1.5V     -849.7mA   -860.2mA   -853.5mA
-1.034V   -246.6mA   -324.3mA   -170.7mA
-984.4mV  -183.1mA   -267.7mA   -102.9mA
-935.2mV  -119.9mA   -211.2mA   -57.59mA
-885.9mV  -66.33mA   -154.7mA   -38.94mA
-836.7mV  -33.59mA   -99.09mA   -29.82mA
-787.5mV  -19.44mA   -53.53mA   -22.49mA
-738.3mV  -12.87mA   -24.95mA   -16.13mA
-689.1mV  -8.545mA   -11.57mA   -10.81mA
-590.6mV  -2.947mA   -3.067mA   -3.621mA
-393.7mV  -37.64uA   -63.17uA   -40.12uA
3V        0A         0A         0A
[POWER Clamp]
| Voltage   I(typ)   I(min)   I(max)
-1.5V     10.9mA     9.757mA    12.4mA
-1.23V    4.091mA    4.068mA    4.41mA
-1.083V   2.694mA    2.748mA    2.728mA
-984.4mV  1.956mA    2.133mA    1.792mA
-885.9mV  1.297mA    1.575mA    1.105mA
-787.5mV  756.7uA    1.072mA    746.1uA
-738.3mV  562.1uA    843.7uA    616.9uA
-590.6mV  217.4uA    298uA      241.2uA
-492.2mV  69.4uA     129.1uA    67.8uA
-344.5mV  1.546uA    8.832uA    4.546uA
-246.1mV  138.9nA    771.2nA    12.63nA
3V        0A         0A         0A
[Pullup]
| Voltage   I(typ)   I(min)   I(max)
-1.5V     97.49mA    118.4mA    74.94mA
-1.083V   70.28mA    83.19mA    55.49mA
-344.5mV  18.91mA    21.79mA    15.84mA
0V        -138.7nA   17.25uA    28.6uA
328.1mV   -12.55mA   -13.63mA   -11.27mA
656.2mV   -19.2mA    -20.6mA    -17.61mA
1.125V    -21.7mA    -23.1mA    -20.19mA
2.041V    -22.76mA   -24.03mA   -21.29mA
2.288V    -22.28mA   -19.11mA   -21.1mA
2.386V    -19.09mA   -18.89mA   -20.99mA
2.632V    -17.18mA   -19.02mA   -15.31mA
3V        -17.33mA   -19.19mA   -15.43mA
[Pulldown]
| Voltage   I(typ)   I(min)   I(max)
-1.5V     -11.06mA   -12.77mA   -8.108mA
-1.083V   -10.73mA   -12.14mA   -8.354mA
-984.4mV  -11.24mA   -11.92mA   -16.79mA
-935.2mV  -15.01mA   -11.79mA   -24.44mA
-885.9mV  -21.9mA    -12.25mA   -27.74mA
-836.7mV  -28.35mA   -15.96mA   -27.79mA
-738.3mV  -30.24mA   -26.8mA    -26.47mA
-590.6mV  -25.96mA   -26.62mA   -23.03mA
281.2mV   11.21mA    11.05mA    10.5mA
843.8mV   25.25mA    24.89mA    23.61mA
1.359V    29.47mA    28.98mA    27.48mA
3V        30.25mA    29.81mA    28.15mA
[Ramp]
dV/dt_r   0.547789/0.320419n  0.54883/0.327975n  0.53667/0.306044n
dV/dt_f   0.57295/0.247669n  0.544317/0.279122n  0.579415/0.25508n
R_load = 50
[Rising Waveform]
R_fixture = 50
V_fixture = 0
V_fixture_min = 0
V_fixture_max = 0
| Time   V(typ)   V(min)   V(max)
0s        11.81nV    16.52nV    16.52nV
1.625ns   804.8uV    716.9uV    -48.79mV
1.936ns   -9.623mV   854.1uV    579.3mV
2.133ns   -62.77mV   941uV      771.4mV
2.405ns   485.8mV    -1.038mV   850.2mV
2.558ns   699.9mV    -17.15mV   869.6mV
2.823ns   848.7mV    -60.9mV    883.9mV
3.226ns   894.9mV    673.2mV    891.8mV
3.652ns   906.8mV    879.2mV    893.6mV
10ns      913mV      914.7mV    894.4mV
[Rising Waveform]
R_fixture = 50
V_fixture = 1.5
V_fixture_min = 1.425
V_fixture_max = 1.575
| Time   V(typ)   V(min)   V(max)
0s        545.1mV    517.8mV    609.3mV
1.455ns   544.5mV    517.6mV    617.1mV
1.799ns   541.2mV    517.6mV    1.426V
1.982ns   590.5mV    517.5mV    1.538V
2.125ns   951.8mV    517.5mV    1.561V
2.394ns   1.428V     510mV      1.571V
2.564ns   1.478V     576.8mV    1.573V
2.999ns   1.497V     1.307V     1.575V
3.271ns   1.499V     1.407V     1.575V
10ns      1.5V       1.425V     1.575V
[Falling Waveform]
R_fixture = 50
V_fixture = 0
V_fixture_min = 0
V_fixture_max = 0
| Time   V(typ)   V(min)   V(max)
0s        913mV      914.7mV    894.4mV
1.481ns   912.1mV    914.1mV    907.9mV
1.776ns   912.4mV    913.9mV    139.8mV
2.03ns    782mV      913.8mV    17.75mV
2.222ns   274mV      913.8mV    6.277mV
2.39ns    61.86mV    916.6mV    2.896mV
2.607ns   13.89mV    917.5mV    575.2uV
2.919ns   2.743mV    203.1mV    291.8uV
3.22ns    860.9uV    21.75mV    18.34uV
10ns      1.88uV     3.952uV    453.2nV
[Falling Waveform]
R_fixture = 50
V_fixture = 1.5
V_fixture_min = 1.425
V_fixture_max = 1.575
| Time   V(typ)   V(min)   V(max)
0s        1.5V       1.425V     1.575V
1.581ns   1.499V     1.425V     1.626V
1.898ns   1.498V     1.424V     917.9mV
2.133ns   1.571V     1.424V     681.2mV
2.405ns   918.3mV    1.421V     624.8mV
2.598ns   651.5mV    1.45V      616.5mV
2.776ns   586.7mV    1.514V     612.4mV
3.153ns   551.5mV    769.5mV    609.9mV
3.52ns    546.9mV    551.4mV    609.4mV
10ns      545.1mV    517.8mV    609.3mV
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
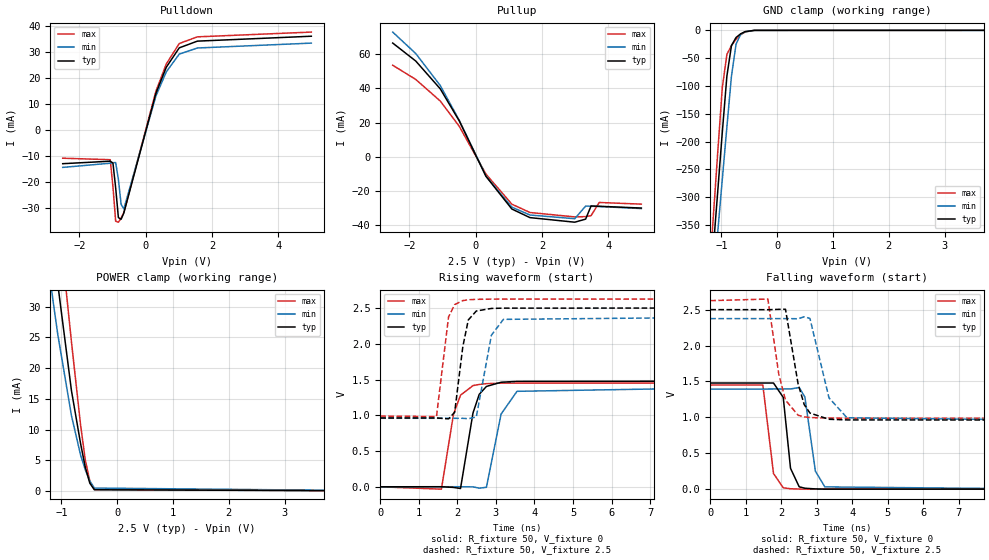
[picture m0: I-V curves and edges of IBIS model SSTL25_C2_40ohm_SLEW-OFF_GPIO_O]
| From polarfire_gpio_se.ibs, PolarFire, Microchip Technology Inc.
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|   Model SSTL25_C2_40ohm_SLEW-OFF_GPIO_O
[Model]   SSTL25_C2_40ohm_SLEW-OFF_GPIO_O
Model_type   Output
Polarity   Non-Inverting
Enable   Active-High
Vmeas =   1.25
Cref =   5p
Rref =   50
Vref =   1.25
|   typ   min   max
C_comp_pullup   2.605e-12   2.605e-12   2.76e-12
C_comp_pulldown  2.605e-12   2.605e-12   2.76e-12
[Temperature Range]  25C   100C   -40C
[Voltage Range]  2.5   2.375   2.625
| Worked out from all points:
|   slope of the pulldown table from 0 to 0.375 V, typ, clamps not added: 23 ohm
|   slope of the pullup table from 0 to 0.375 V, typ, clamps not added: 27.6 ohm
|   GND clamp passes 1 mA (typ) near -0.51 V on its own axis
|   POWER clamp passes 1 mA (typ) near -0.47 V on its own axis
|   rising waveform, R_fixture 50, V_fixture 0: 20-80 % time 288ps typ, 327ps min, 281ps max; typ from 0 V to 1.48 V
|   rising waveform, R_fixture 50, V_fixture 2.5: 20-80 % time 221ps typ, 267ps min, 187ps max; typ from 0.963 V to 2.5 V
|   falling waveform, R_fixture 50, V_fixture 0: 20-80 % time 180ps typ, 228ps min, 165ps max; typ from 1.48 V to 0 V
|   falling waveform, R_fixture 50, V_fixture 2.5: 20-80 % time 342ps typ, 417ps min, 328ps max; typ from 2.5 V to 0.963 V
[GND Clamp]
| Voltage   I(typ)   I(min)   I(max)
-2.5V     -2.154A    -2.019A    -2.334A
-1.23V    -500.9mA   -550.5mA   -458.7mA
-1.148V   -394.9mA   -456.3mA   -338.7mA
-1.066V   -289mA     -362mA     -218.7mA
-984.4mV  -183.1mA   -267.7mA   -102.9mA
-902.3mV  -82.21mA   -173.6mA   -43.25mA
-820.3mV  -27.37mA   -82.26mA   -27.26mA
-738.3mV  -12.87mA   -24.95mA   -16.13mA
-656.2mV  -6.285mA   -7.324mA   -7.886mA
-574.2mV  -2.342mA   -2.429mA   -2.872mA
-410.2mV  -62.85uA   -96.5uA    -70.85uA
5V        0A         0A         0A
[POWER Clamp]
| Voltage   I(typ)   I(min)   I(max)
-2.5V     191.3mA    155.6mA    232.6mA
-1.559V   79.6mA     61.42mA    102.5mA
-1.395V   63.37mA    48.38mA    82.85mA
-1.23V    48.04mA    36.4mA     63.67mA
-1.148V   40.77mA    30.8mA     54.53mA
-1.066V   33.71mA    25.51mA    45.88mA
-820.3mV  16.31mA    12.25mA    24.25mA
-656.2mV  7.665mA    5.818mA    10.67mA
-574.2mV  3.929mA    3.48mA     5.131mA
-492.2mV  1.272mA    1.622mA    1.634mA
-410.2mV  189.8uA    467.6uA    244.4uA
5V        0A         0A         0A
[Pullup]
| Voltage   I(typ)   I(min)   I(max)
-2.5V     66.67mA    73.1mA     53.64mA
-1.805V   56.12mA    60.52mA    45.32mA
-1.066V   39.81mA    41.74mA    32.66mA
-492.2mV  20.98mA    21.34mA    17.82mA
312.5mV   -11.53mA   -11.3mA    -10.24mA
1.094V    -30.72mA   -29.62mA   -27.87mA
1.641V    -35.77mA   -34.24mA   -32.77mA
2.992V    -38.45mA   -36.41mA   -35.35mA
3.32V     -36.64mA   -28.99mA   -35.18mA
3.484V    -28.93mA   -29.1mA    -34.62mA
3.73V     -29.1mA    -29.28mA   -26.88mA
5V        -30.16mA   -30.46mA   -27.85mA
[Pulldown]
| Voltage   I(typ)   I(min)   I(max)
-2.5V     -13.11mA   -14.54mA   -11mA
-1.066V   -12.16mA   -12.93mA   -11.58mA
-984.4mV  -12.87mA   -12.74mA   -21.98mA
-902.3mV  -22.41mA   -12.67mA   -35.23mA
-820.3mV  -33.84mA   -19.11mA   -35.61mA
-738.3mV  -34.48mA   -28.75mA   -34.08mA
-656.2mV  -32.07mA   -30.49mA   -31.89mA
312.5mV   13.99mA    12.94mA    14.76mA
625mV     23.99mA    22.21mA    25.26mA
1.016V    31.44mA    29.03mA    33.1mA
1.562V    34.02mA    31.38mA    35.67mA
5V        35.91mA    33.26mA    37.5mA
[Ramp]
dV/dt_r   0.886572/0.28835n  0.836294/0.326756n  0.87015/0.281196n
dV/dt_f   0.922356/0.341587n  0.850041/0.416629n  0.982087/0.328475n
R_load = 50
[Rising Waveform]
R_fixture = 50
V_fixture = 0
V_fixture_min = 0
V_fixture_max = 0
| Time   V(typ)   V(min)   V(max)
0s        13.4nV     24.78nV    16.99nV
1.586ns   744.1uV    575uV      -33.3mV
1.9ns     -8.804mV   688.9uV    1.015V
2.082ns   -24.11mV   754.8uV    1.281V
2.406ns   1.033V     -1.018mV   1.415V
2.568ns   1.293V     -18.93mV   1.431V
2.754ns   1.403V     -7.746mV   1.442V
3.135ns   1.462V     1.017V     1.449V
3.548ns   1.474V     1.335V     1.45V
10ns      1.478V     1.394V     1.45V
[Rising Waveform]
R_fixture = 50
V_fixture = 2.5
V_fixture_min = 2.375
V_fixture_max = 2.625
| Time   V(typ)   V(min)   V(max)
0s        962.7mV    958.3mV    988.2mV
1.458ns   962.6mV    957.7mV    981.4mV
1.771ns   949.9mV    957.6mV    2.374V
1.93ns    1.042V     957.5mV    2.548V
2.142ns   1.96V      957.4mV    2.604V
2.284ns   2.333V     951.5mV    2.615V
2.492ns   2.458V     976.3mV    2.621V
2.884ns   2.494V     2.12V      2.624V
3.195ns   2.498V     2.341V     2.625V
10ns      2.5V       2.375V     2.625V
[Falling Waveform]
R_fixture = 50
V_fixture = 0
V_fixture_min = 0
V_fixture_max = 0
| Time   V(typ)   V(min)   V(max)
0s        1.478V     1.394V     1.45V
1.481ns   1.478V     1.394V     1.451V
1.782ns   1.478V     1.395V     217.8mV
2.056ns   1.278V     1.395V     19.01mV
2.261ns   290.6mV    1.395V     5.788mV
2.506ns   32.43mV    1.415V     1.841mV
2.667ns   13.29mV    1.281V     816uV
2.962ns   3.388mV    250.5mV    185.4uV
3.229ns   1.111mV    31.75mV    43.13uV
10ns      2.497uV    4.968uV    711.4nV
[Falling Waveform]
R_fixture = 50
V_fixture = 2.5
V_fixture_min = 2.375
V_fixture_max = 2.625
| Time   V(typ)   V(min)   V(max)
0s        2.5V       2.375V     2.625V
1.623ns   2.499V     2.375V     2.647V
1.931ns   2.504V     2.375V     1.599V
2.119ns   2.505V     2.375V     1.24V
2.475ns   1.464V     2.373V     1.029V
2.647ns   1.178V     2.4V       1.007V
2.808ns   1.06V      2.378V     997.4mV
3.345ns   973mV      1.272V     989.5mV
3.853ns   964.4mV    994mV      988.2mV
10ns      962.7mV    958.3mV    988.2mV
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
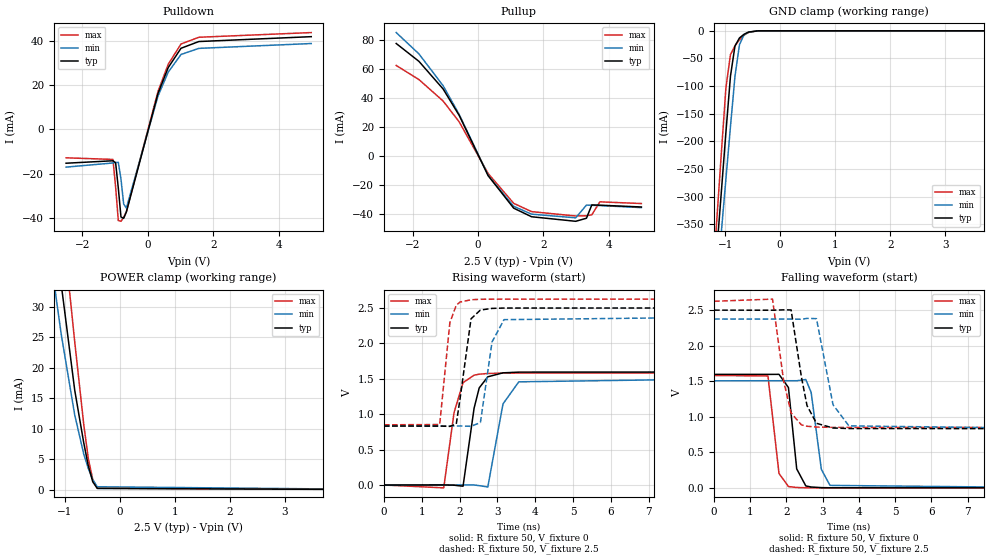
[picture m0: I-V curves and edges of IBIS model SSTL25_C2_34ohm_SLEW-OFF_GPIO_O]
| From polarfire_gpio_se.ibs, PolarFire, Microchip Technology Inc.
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|   Model SSTL25_C2_34ohm_SLEW-OFF_GPIO_O
[Model]   SSTL25_C2_34ohm_SLEW-OFF_GPIO_O
Model_type   Output
Polarity   Non-Inverting
Enable   Active-High
Vmeas =   1.25
Cref =   5p
Rref =   50
Vref =   1.25
|   typ   min   max
C_comp_pullup   2.605e-12   2.605e-12   2.76e-12
C_comp_pulldown  2.605e-12   2.605e-12   2.76e-12
[Temperature Range]  25C   100C   -40C
[Voltage Range]  2.5   2.375   2.625
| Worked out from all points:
|   slope of the pulldown table from 0 to 0.375 V, typ, clamps not added: 19.8 ohm
|   slope of the pullup table from 0 to 0.375 V, typ, clamps not added: 23.7 ohm
|   GND clamp passes 1 mA (typ) near -0.51 V on its own axis
|   POWER clamp passes 1 mA (typ) near -0.47 V on its own axis
|   rising waveform, R_fixture 50, V_fixture 0: 20-80 % time 267ps typ, 306ps min, 258ps max; typ from 0 V to 1.6 V
|   rising waveform, R_fixture 50, V_fixture 2.5: 20-80 % time 213ps typ, 250ps min, 177ps max; typ from 0.833 V to 2.5 V
|   falling waveform, R_fixture 50, V_fixture 0: 20-80 % time 182ps typ, 227ps min, 163ps max; typ from 1.6 V to 0 V
|   falling waveform, R_fixture 50, V_fixture 2.5: 20-80 % time 315ps typ, 353ps min, 291ps max; typ from 2.5 V to 0.833 V
[GND Clamp]
| Voltage   I(typ)   I(min)   I(max)
-2.5V     -2.154A    -2.019A    -2.334A
-1.23V    -500.9mA   -550.5mA   -458.7mA
-1.148V   -394.9mA   -456.3mA   -338.7mA
-1.066V   -289mA     -362mA     -218.7mA
-984.4mV  -183.1mA   -267.7mA   -102.9mA
-902.3mV  -82.21mA   -173.6mA   -43.25mA
-820.3mV  -27.37mA   -82.26mA   -27.26mA
-738.3mV  -12.87mA   -24.95mA   -16.13mA
-656.2mV  -6.285mA   -7.324mA   -7.886mA
-574.2mV  -2.342mA   -2.429mA   -2.872mA
-410.2mV  -62.85uA   -96.5uA    -70.85uA
5V        0A         0A         0A
[POWER Clamp]
| Voltage   I(typ)   I(min)   I(max)
-2.5V     191.3mA    155.6mA    232.6mA
-1.559V   79.6mA     61.42mA    102.5mA
-1.395V   63.37mA    48.38mA    82.85mA
-1.23V    48.04mA    36.4mA     63.67mA
-1.148V   40.77mA    30.8mA     54.53mA
-1.066V   33.71mA    25.51mA    45.88mA
-820.3mV  16.31mA    12.25mA    24.25mA
-656.2mV  7.665mA    5.818mA    10.67mA
-574.2mV  3.929mA    3.48mA     5.131mA
-492.2mV  1.272mA    1.622mA    1.634mA
-410.2mV  189.8uA    467.6uA    244.4uA
5V        0A         0A         0A
[Pullup]
| Voltage   I(typ)   I(min)   I(max)
-2.5V     77.74mA    85.27mA    62.59mA
-1.805V   65.42mA    70.57mA    52.86mA
-1.066V   46.4mA     48.65mA    38.08mA
-574.2mV  28.18mA    28.85mA    23.73mA
312.5mV   -13.44mA   -13.17mA   -11.93mA
1.094V    -35.83mA   -34.55mA   -32.49mA
1.641V    -41.75mA   -39.96mA   -38.22mA
2.992V    -44.89mA   -42.49mA   -41.24mA
3.32V     -42.78mA   -33.71mA   -41.05mA
3.484V    -33.59mA   -33.85mA   -40.41mA
3.73V     -33.78mA   -34.05mA   -31.47mA
5V        -35.02mA   -35.45mA   -32.64mA
[Pulldown]
| Voltage   I(typ)   I(min)   I(max)
-2.5V     -15.27mA   -17.03mA   -12.83mA
-1.066V   -14.16mA   -15.15mA   -13.56mA
-984.4mV  -15.08mA   -14.92mA   -26mA
-902.3mV  -26.47mA   -14.85mA   -41.17mA
-820.3mV  -39.57mA   -22.52mA   -41.5mA
-738.3mV  -40.15mA   -33.68mA   -39.7mA
-656.2mV  -37.32mA   -35.53mA   -37.14mA
312.5mV   16.27mA    15.07mA    17.18mA
625mV     27.94mA    25.88mA    29.43mA
1.016V    36.65mA    33.84mA    38.59mA
1.562V    39.69mA    36.6mA     41.62mA
5V        41.89mA    38.79mA    43.74mA
[Ramp]
dV/dt_r   0.957455/0.267173n  0.903738/0.305797n  0.94867/0.258218n
dV/dt_f   1.0004/0.314541n  0.925306/0.352978n  1.06503/0.291427n
R_load = 50
[Rising Waveform]
R_fixture = 50
V_fixture = 0
V_fixture_min = 0
V_fixture_max = 0
| Time   V(typ)   V(min)   V(max)
0s        11.97nV    22.17nV    15.14nV
1.581ns   694.3uV    540.3uV    -40.37mV
1.854ns   -2.706mV   633.6uV    1.023V
2.092ns   -17.15mV   715uV      1.446V
2.384ns   1.085V     787.5uV    1.551V
2.52ns    1.372V     -9.093mV   1.565V
2.747ns   1.528V     -28.09mV   1.575V
3.148ns   1.584V     1.145V     1.58V
3.566ns   1.594V     1.457V     1.581V
10ns      1.596V     1.506V     1.581V
[Rising Waveform]
R_fixture = 50
V_fixture = 2.5
V_fixture_min = 2.375
V_fixture_max = 2.625
| Time   V(typ)   V(min)   V(max)
0s        832.7mV    832.8mV    850mV
1.474ns   832.5mV    833.4mV    854.1mV
1.743ns   827.6mV    833.5mV    2.292V
1.913ns   861.4mV    833.5mV    2.541V
2.014ns   1.225V     833.6mV    2.584V
2.303ns   2.347V     828.5mV    2.616V
2.551ns   2.471V     881.4mV    2.623V
2.859ns   2.494V     2.021V     2.624V
3.175ns   2.499V     2.335V     2.624V
10ns      2.5V       2.375V     2.625V
[Falling Waveform]
R_fixture = 50
V_fixture = 0
V_fixture_min = 0
V_fixture_max = 0
| Time   V(typ)   V(min)   V(max)
0s        1.596V     1.506V     1.581V
1.488ns   1.596V     1.507V     1.574V
1.793ns   1.597V     1.507V     203.1mV
2.054ns   1.411V     1.507V     18.33mV
2.282ns   267.1mV    1.507V     5.101mV
2.534ns   26.87mV    1.524V     1.292mV
2.681ns   12.03mV    1.343V     811.5uV
2.963ns   3.268mV    260mV      124.2uV
3.201ns   1.122mV    34.75mV    120uV
10ns      2.445uV    1.95uV     10.16nV
[Falling Waveform]
R_fixture = 50
V_fixture = 2.5
V_fixture_min = 2.375
V_fixture_max = 2.625
| Time   V(typ)   V(min)   V(max)
0s        2.5V       2.375V     2.625V
1.614ns   2.499V     2.374V     2.655V
1.925ns   2.504V     2.374V     1.493V
2.127ns   2.503V     2.374V     1.054V
2.411ns   1.563V     2.372V     886.5mV
2.567ns   1.157V     2.384V     866.6mV
2.828ns   908.1mV    2.38V      855.6mV
3.286ns   842.1mV    1.168V     850.9mV
3.724ns   834.5mV    871.9mV    849.9mV
10ns      832.7mV    832.8mV    850mV
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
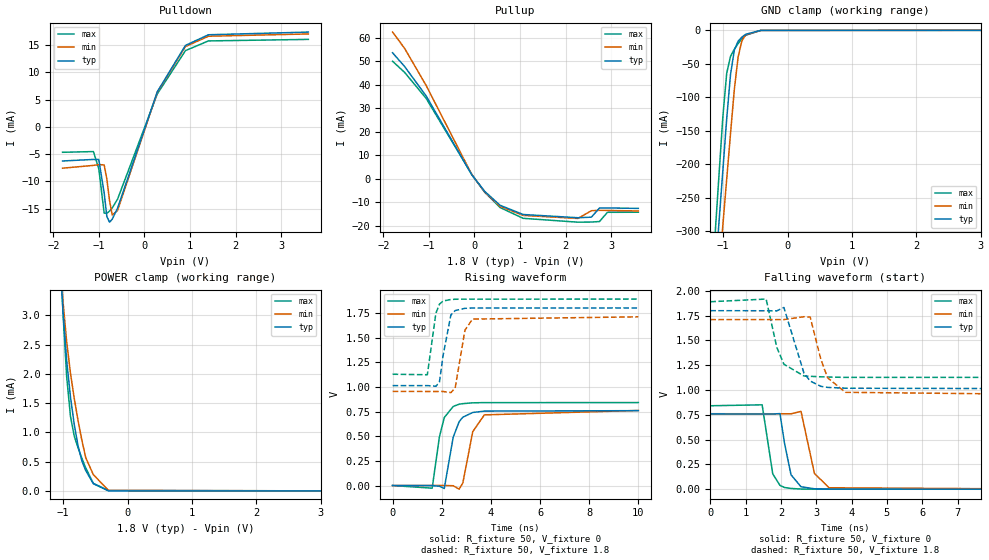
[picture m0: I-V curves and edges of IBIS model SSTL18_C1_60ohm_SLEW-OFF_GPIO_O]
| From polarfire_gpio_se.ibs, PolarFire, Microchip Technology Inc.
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|   Model SSTL18_C1_60ohm_SLEW-OFF_GPIO_O
[Model]   SSTL18_C1_60ohm_SLEW-OFF_GPIO_O
Model_type   Output
Polarity   Non-Inverting
Enable   Active-High
Vmeas =   0.9
Cref =   5p
Rref =   50
Vref =   0.9
|   typ   min   max
C_comp_pullup   2.605e-12   2.605e-12   2.76e-12
C_comp_pulldown  2.605e-12   2.605e-12   2.76e-12
[Temperature Range]  25C   100C   -40C
[Voltage Range]  1.8   1.71   1.89
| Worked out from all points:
|   slope of the pulldown table from 0 to 0.27 V, typ, clamps not added: 43.5 ohm
|   slope of the pullup table from 0 to 0.27 V, typ, clamps not added: 42.3 ohm
|   GND clamp passes 1 mA (typ) near -0.52 V on its own axis
|   POWER clamp passes 1 mA (typ) near -0.81 V on its own axis
|   rising waveform, R_fixture 50, V_fixture 0: 20-80 % time 380ps typ, 422ps min, 339ps max; typ from 0 V to 0.759 V
|   rising waveform, R_fixture 50, V_fixture 1.8: 20-80 % time 278ps typ, 312ps min, 250ps max; typ from 1.01 V to 1.8 V
|   falling waveform, R_fixture 50, V_fixture 0: 20-80 % time 232ps typ, 273ps min, 196ps max; typ from 0.759 V to 0 V
|   falling waveform, R_fixture 50, V_fixture 1.8: 20-80 % time 398ps typ, 391ps min, 356ps max; typ from 1.8 V to 1.01 V
[GND Clamp]
| Voltage   I(typ)   I(min)   I(max)
-1.8V     -1.238A    -1.206A    -1.294A
-1.122V   -361mA     -426.1mA   -300.3mA
-1.063V   -284.7mA   -358.2mA   -213.9mA
-1.004V   -208.5mA   -290.3mA   -128.4mA
-945mV    -132.4mA   -222.5mA   -64.19mA
-885.9mV  -66.33mA   -154.7mA   -38.94mA
-826.9mV  -29.63mA   -88.81mA   -28.27mA
-767.8mV  -16.36mA   -39.95mA   -19.83mA
-708.7mV  -10.12mA   -15.57mA   -12.8mA
-649.7mV  -5.882mA   -6.713mA   -7.364mA
-413.4mV  -69.42uA   -104.8uA   -78.93uA
3.6V      0A         0A         0A
[POWER Clamp]
| Voltage   I(typ)   I(min)   I(max)
-1.8V     45.61mA    35.66mA    60.31mA
-1.063V   4.301mA    4.234mA    4.672mA
-1.004V   3.099mA    3.258mA    3.078mA
-945mV    2.226mA    2.547mA    1.95mA
-885.9mV  1.604mA    2.011mA    1.273mA
-826.9mV  1.131mA    1.577mA    934uA
-767.8mV  765.5uA    1.2mA      735.6uA
-708.7mV  512.4uA    863.2uA    558uA
-649.7mV  349.8uA    570.8uA    394.2uA
-531.6mV  123.5uA    279.3uA    129.3uA
-295.3mV  280.4nA    8.522uA    8.372uA
3.6V      0A         0A         0A
[Pullup]
| Voltage   I(typ)   I(min)   I(max)
-1.8V     53.58mA    62.39mA    49.98mA
-1.536V   47.75mA    55.48mA    45.24mA
-1.063V   35.23mA    39.68mA    34.21mA
-59.06mV  1.616mA    1.731mA    1.765mA
225mV     -5.445mA   -5.712mA   -5.811mA
562.5mV   -11.35mA   -11.8mA    -12.32mA
1.069V    -15.27mA   -15.66mA   -16.9mA
2.272V    -16.65mA   -16.96mA   -18.55mA
2.568V    -16.41mA   -13.67mA   -18.48mA
2.745V    -12.54mA   -13.49mA   -18.27mA
2.922V    -12.49mA   -13.55mA   -14.34mA
3.6V      -12.68mA   -13.77mA   -14.31mA
[Pulldown]
| Voltage   I(typ)   I(min)   I(max)
-1.8V     -6.262mA   -7.584mA   -4.667mA
-1.122V   -5.98mA    -7.074mA   -4.538mA
-1.004V   -5.999mA   -6.926mA   -7.694mA
-885.9mV  -12.14mA   -6.99mA    -15.82mA
-826.9mV  -16.46mA   -9.567mA   -15.87mA
-767.8mV  -17.49mA   -13.54mA   -15.45mA
-708.7mV  -16.94mA   -16.18mA   -14.88mA
-590.6mV  -14.89mA   -15.32mA   -13.25mA
281.2mV   6.43mA     6.352mA    6.039mA
900mV     14.94mA    14.73mA    13.98mA
1.406V    16.89mA    16.62mA    15.76mA
3.6V      17.38mA    17.04mA    16.04mA
[Ramp]
dV/dt_r   0.455262/0.379876n  0.456567/0.422441n  0.504626/0.339049n
dV/dt_f   0.472106/0.397857n  0.453666/0.39107n  0.457464/0.355859n
R_load = 50
[Rising Waveform]
R_fixture = 50
V_fixture = 0
V_fixture_min = 0
V_fixture_max = 0
| Time   V(typ)   V(min)   V(max)
0s        18.08nV    24.89nV    24.86nV
1.612ns   -745.7uV   619.3uV    -26.89mV
1.904ns   -6.67mV    731.5uV    490.8mV
2.104ns   -30.12mV   808.3uV    689.2mV
2.466ns   488.6mV    -1.997mV   801mV
2.709ns   647.4mV    -36.87mV   824.7mV
2.859ns   693mV      26mV       830mV
3.263ns   740.4mV    546.3mV    838.1mV
3.735ns   754.2mV    716.1mV    840.6mV
10ns      758.8mV    760.9mV    841mV
[Rising Waveform]
R_fixture = 50
V_fixture = 1.8
V_fixture_min = 1.71
V_fixture_max = 1.89
| Time   V(typ)   V(min)   V(max)
0s        1.013V     953.9mV    1.128V
1.415ns   1.013V     953.5mV    1.123V
1.762ns   1.006V     953.4mV    1.745V
1.907ns   1.048V     953.3mV    1.838V
2.055ns   1.317V     953.3mV    1.87V
2.372ns   1.728V     941.3mV    1.886V
2.546ns   1.773V     986.7mV    1.888V
2.945ns   1.796V     1.575V     1.889V
3.254ns   1.799V     1.687V     1.889V
10ns      1.8V       1.71V      1.89V
[Falling Waveform]
R_fixture = 50
V_fixture = 0
V_fixture_min = 0
V_fixture_max = 0
| Time   V(typ)   V(min)   V(max)
0s        758.8mV    760.8mV    841mV
1.468ns   758mV      760.4mV    850.5mV
1.768ns   757.9mV    760.3mV    154.1mV
1.972ns   762.1mV    760.2mV    38.29mV
2.099ns   468mV      760.2mV    17.14mV
2.285ns   145.3mV    759.8mV    7.085mV
2.568ns   24.3mV     784.4mV    1.443mV
2.948ns   3.983mV    159mV      431.8uV
3.361ns   550.8uV    14.06mV    -81.68uV
10ns      460.5nV    30.26nV    602.6nV
[Falling Waveform]
R_fixture = 50
V_fixture = 1.8
V_fixture_min = 1.71
V_fixture_max = 1.89
| Time   V(typ)   V(min)   V(max)
0s        1.8V       1.71V      1.89V
1.581ns   1.799V     1.71V      1.917V
1.882ns   1.798V     1.71V      1.431V
2.083ns   1.832V     1.71V      1.26V
2.652ns   1.17V      1.739V     1.141V
2.829ns   1.09V      1.735V     1.138V
3.129ns   1.037V     1.31V      1.133V
3.321ns   1.026V     1.123V     1.131V
3.826ns   1.018V     976.5mV    1.127V
10ns      1.013V     953.9mV    1.128V
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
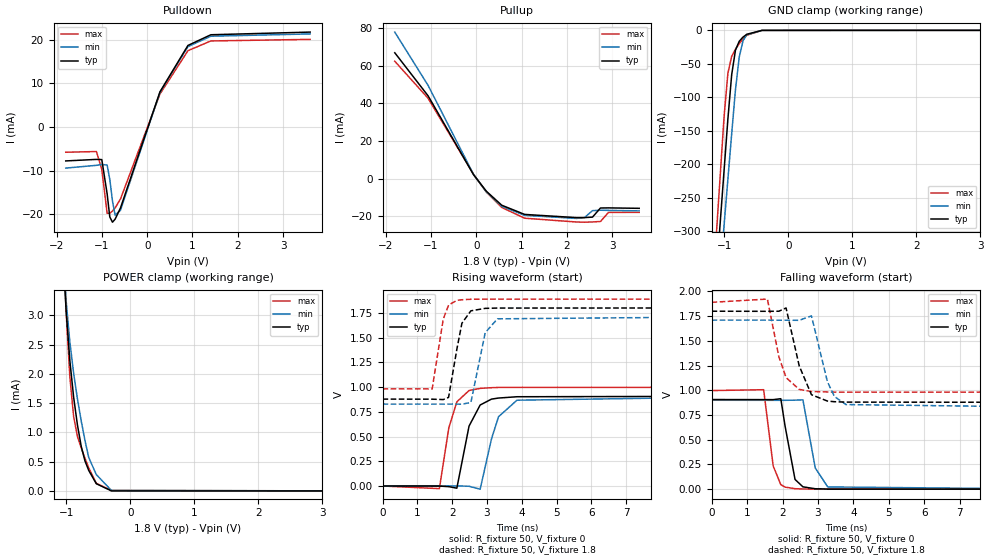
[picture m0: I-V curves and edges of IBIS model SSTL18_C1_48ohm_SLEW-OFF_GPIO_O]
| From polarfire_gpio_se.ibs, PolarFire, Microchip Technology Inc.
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|   Model SSTL18_C1_48ohm_SLEW-OFF_GPIO_O
[Model]   SSTL18_C1_48ohm_SLEW-OFF_GPIO_O
Model_type   Output
Polarity   Non-Inverting
Enable   Active-High
Vmeas =   0.9
Cref =   5p
Rref =   50
Vref =   0.9
|   typ   min   max
C_comp_pullup   2.605e-12   2.605e-12   2.76e-12
C_comp_pulldown  2.605e-12   2.605e-12   2.76e-12
[Temperature Range]  25C   100C   -40C
[Voltage Range]  1.8   1.71   1.89
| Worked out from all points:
|   slope of the pulldown table from 0 to 0.27 V, typ, clamps not added: 34.9 ohm
|   slope of the pullup table from 0 to 0.27 V, typ, clamps not added: 33.9 ohm
|   GND clamp passes 1 mA (typ) near -0.52 V on its own axis
|   POWER clamp passes 1 mA (typ) near -0.81 V on its own axis
|   rising waveform, R_fixture 50, V_fixture 0: 20-80 % time 357ps typ, 407ps min, 313ps max; typ from 0 V to 0.907 V
|   rising waveform, R_fixture 50, V_fixture 1.8: 20-80 % time 264ps typ, 303ps min, 239ps max; typ from 0.878 V to 1.8 V
|   falling waveform, R_fixture 50, V_fixture 0: 20-80 % time 230ps typ, 276ps min, 192ps max; typ from 0.907 V to 0 V
|   falling waveform, R_fixture 50, V_fixture 1.8: 20-80 % time 368ps typ, 377ps min, 341ps max; typ from 1.8 V to 0.878 V
[GND Clamp]
| Voltage   I(typ)   I(min)   I(max)
-1.8V     -1.238A    -1.206A    -1.294A
-1.122V   -361mA     -426.1mA   -300.3mA
-1.063V   -284.7mA   -358.2mA   -213.9mA
-1.004V   -208.5mA   -290.3mA   -128.4mA
-945mV    -132.4mA   -222.5mA   -64.19mA
-885.9mV  -66.33mA   -154.7mA   -38.94mA
-826.9mV  -29.63mA   -88.81mA   -28.27mA
-767.8mV  -16.36mA   -39.95mA   -19.83mA
-708.7mV  -10.12mA   -15.57mA   -12.8mA
-649.7mV  -5.882mA   -6.713mA   -7.364mA
-413.4mV  -69.42uA   -104.8uA   -78.93uA
3.6V      0A         0A         0A
[POWER Clamp]
| Voltage   I(typ)   I(min)   I(max)
-1.8V     45.61mA    35.66mA    60.31mA
-1.063V   4.301mA    4.234mA    4.672mA
-1.004V   3.099mA    3.258mA    3.078mA
-945mV    2.226mA    2.547mA    1.95mA
-885.9mV  1.604mA    2.011mA    1.273mA
-826.9mV  1.131mA    1.577mA    934uA
-767.8mV  765.5uA    1.2mA      735.6uA
-708.7mV  512.4uA    863.2uA    558uA
-649.7mV  349.8uA    570.8uA    394.2uA
-531.6mV  123.5uA    279.3uA    129.3uA
-295.3mV  280.4nA    8.522uA    8.371uA
3.6V      0A         0A         0A
[Pullup]
| Voltage   I(typ)   I(min)   I(max)
-1.8V     66.93mA    77.93mA    62.42mA
-1.063V   43.98mA    49.52mA    42.69mA
-59.06mV  2.017mA    2.16mA     2.202mA
225mV     -6.802mA   -7.135mA   -7.252mA
562.5mV   -14.19mA   -14.74mA   -15.38mA
1.069V    -19.09mA   -19.59mA   -21.11mA
2.213V    -20.8mA    -21.22mA   -23.13mA
2.391V    -20.8mA    -20.76mA   -23.23mA
2.568V    -20.53mA   -17.1mA    -23.11mA
2.745V    -15.68mA   -16.86mA   -22.85mA
2.922V    -15.62mA   -16.94mA   -18.02mA
3.6V      -15.85mA   -17.21mA   -17.98mA
[Pulldown]
| Voltage   I(typ)   I(min)   I(max)
-1.8V     -7.803mA   -9.443mA   -5.812mA
-1.122V   -7.452mA   -8.808mA   -5.652mA
-1.004V   -7.497mA   -8.623mA   -9.758mA
-885.9mV  -15.31mA   -8.737mA   -19.78mA
-826.9mV  -20.64mA   -12.02mA   -19.81mA
-767.8mV  -21.84mA   -17mA      -19.28mA
-708.7mV  -21.14mA   -20.23mA   -18.56mA
-590.6mV  -18.57mA   -19.11mA   -16.51mA
281.2mV   8.019mA    7.924mA    7.527mA
900mV     18.66mA    18.4mA     17.46mA
1.406V    21.11mA    20.77mA    19.69mA
3.6V      21.72mA    21.3mA     20.05mA
[Ramp]
dV/dt_r   0.543994/0.35722n  0.539682/0.406891n  0.598494/0.312993n
dV/dt_f   0.552949/0.36822n  0.529066/0.377053n  0.544944/0.341115n
R_load = 50
[Rising Waveform]
R_fixture = 50
V_fixture = 0
V_fixture_min = 0
V_fixture_max = 0
| Time   V(typ)   V(min)   V(max)
0s        15.84nV    21.82nV    21.87nV
1.633ns   -870.9uV   709.3uV    -26.73mV
1.904ns   -6.453mV   827uV      587.6mV
2.135ns   -22.19mV   927.3uV    851mV
2.486ns   606mV      -2.786mV   965.5mV
2.805ns   818.9mV    -32.07mV   987.1mV
3.132ns   878.6mV    478.5mV    993.8mV
3.333ns   889.2mV    700.4mV    996.5mV
3.863ns   902.4mV    867.4mV    997.1mV
10ns      906.7mV    899.5mV    997.5mV
[Rising Waveform]
R_fixture = 50
V_fixture = 1.8
V_fixture_min = 1.71
V_fixture_max = 1.89
| Time   V(typ)   V(min)   V(max)
0s        878.4mV    828.2mV    981.8mV
1.426ns   877.8mV    828mV      981.6mV
1.744ns   873.8mV    827.9mV    1.687V
1.897ns   895.8mV    827.9mV    1.829V
2.136ns   1.384V     827.8mV    1.877V
2.281ns   1.646V     827.1mV    1.883V
2.538ns   1.771V     844.2mV    1.888V
2.95ns    1.796V     1.55V      1.889V
3.301ns   1.799V     1.69V      1.889V
10ns      1.8V       1.71V      1.89V
[Falling Waveform]
R_fixture = 50
V_fixture = 0
V_fixture_min = 0
V_fixture_max = 0
| Time   V(typ)   V(min)   V(max)
0s        906.6mV    899.5mV    997.5mV
1.468ns   905.8mV    899mV      1.006V
1.737ns   905.6mV    898.9mV    234.6mV
1.952ns   915.1mV    898.9mV    45.54mV
2.071ns   640.8mV    898.8mV    20.89mV
2.353ns   98.52mV    900.4mV    4.897mV
2.575ns   23.67mV    903.4mV    1.865mV
2.923ns   4.301mV    214.3mV    692uV
3.275ns   976.6uV    22.65mV    657.6uV
10ns      337.4nV    6.059uV    2.487nV
[Falling Waveform]
R_fixture = 50
V_fixture = 1.8
V_fixture_min = 1.71
V_fixture_max = 1.89
| Time   V(typ)   V(min)   V(max)
0s        1.8V       1.71V      1.89V
1.574ns   1.799V     1.71V      1.923V
1.898ns   1.8V       1.709V     1.339V
2.1ns     1.833V     1.709V     1.129V
2.471ns   1.247V     1.708V     1.009V
2.816ns   955.4mV    1.753V     987.3mV
3.266ns   891.2mV    1.087V     983.4mV
3.464ns   884.7mV    936.8mV    981.7mV
3.79ns    880.5mV    855.8mV    981.5mV
10ns      878.4mV    828.2mV    981.8mV
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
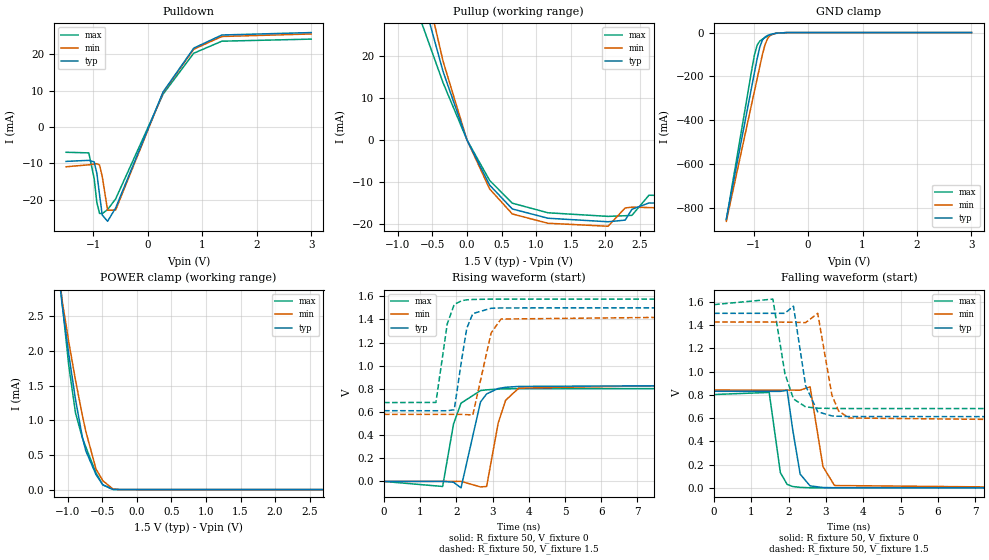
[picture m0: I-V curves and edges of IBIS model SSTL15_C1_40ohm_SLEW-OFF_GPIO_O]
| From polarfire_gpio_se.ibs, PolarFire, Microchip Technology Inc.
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|   Model SSTL15_C1_40ohm_SLEW-OFF_GPIO_O
[Model]   SSTL15_C1_40ohm_SLEW-OFF_GPIO_O
Model_type   Output
Polarity   Non-Inverting
Enable   Active-High
Vmeas =   0.75
Cref =   5p
Rref =   50
Vref =   0.75
|   typ   min   max
C_comp_pullup   2.605e-12   2.605e-12   2.76e-12
C_comp_pulldown  2.605e-12   2.605e-12   2.76e-12
[Temperature Range]  25C   100C   -40C
[Voltage Range]  1.5   1.425   1.575
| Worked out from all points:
|   slope of the pulldown table from 0 to 0.225 V, typ, clamps not added: 28.5 ohm
|   slope of the pullup table from 0 to 0.225 V, typ, clamps not added: 28.4 ohm
|   GND clamp passes 1 mA (typ) near -0.52 V on its own axis
|   POWER clamp passes 1 mA (typ) near -0.84 V on its own axis
|   rising waveform, R_fixture 50, V_fixture 0: 20-80 % time 349ps typ, 362ps min, 328ps max; typ from 0 V to 0.83 V
|   rising waveform, R_fixture 50, V_fixture 1.5: 20-80 % time 256ps typ, 322ps min, 225ps max; typ from 0.611 V to 1.5 V
|   falling waveform, R_fixture 50, V_fixture 0: 20-80 % time 229ps typ, 252ps min, 193ps max; typ from 0.83 V to 0 V
|   falling waveform, R_fixture 50, V_fixture 1.5: 20-80 % time 269ps typ, 284ps min, 277ps max; typ from 1.5 V to 0.611 V
[GND Clamp]
| Voltage   I(typ)   I(min)   I(max)
-1.5V     -849.7mA   -860.2mA   -853.5mA
-1.034V   -246.6mA   -324.3mA   -170.7mA
-984.4mV  -183.1mA   -267.7mA   -102.9mA
-935.2mV  -119.9mA   -211.2mA   -57.59mA
-885.9mV  -66.33mA   -154.7mA   -38.94mA
-836.7mV  -33.59mA   -99.09mA   -29.82mA
-787.5mV  -19.44mA   -53.53mA   -22.49mA
-738.3mV  -12.87mA   -24.95mA   -16.13mA
-689.1mV  -8.545mA   -11.57mA   -10.81mA
-590.6mV  -2.947mA   -3.067mA   -3.621mA
-393.7mV  -37.64uA   -63.17uA   -40.12uA
3V        0A         0A         0A
[POWER Clamp]
| Voltage   I(typ)   I(min)   I(max)
-1.5V     10.9mA     9.757mA    12.4mA
-1.23V    4.091mA    4.068mA    4.41mA
-1.083V   2.694mA    2.748mA    2.728mA
-984.4mV  1.956mA    2.133mA    1.792mA
-885.9mV  1.297mA    1.575mA    1.105mA
-787.5mV  756.7uA    1.072mA    746.1uA
-738.3mV  562.1uA    843.7uA    616.9uA
-590.6mV  217.4uA    298uA      241.2uA
-492.2mV  69.4uA     129.1uA    67.8uA
-344.5mV  1.546uA    8.832uA    4.546uA
-246.1mV  138.9nA    771.1nA    12.63nA
3V        0A         0A         0A
[Pullup]
| Voltage   I(typ)   I(min)   I(max)
-1.5V     83.88mA    101.6mA    64.33mA
-1.083V   60.48mA    71.42mA    47.64mA
-344.5mV  16.27mA    18.71mA    13.6mA
0V        -138.7nA   14.83uA    24.65uA
328.1mV   -10.78mA   -11.69mA   -9.66mA
656.2mV   -16.47mA   -17.66mA   -15.09mA
1.172V    -18.68mA   -19.88mA   -17.38mA
2.041V    -19.52mA   -20.59mA   -18.24mA
2.288V    -19.13mA   -16.23mA   -18.08mA
2.386V    -16.55mA   -16.04mA   -17.99mA
2.632V    -15.04mA   -16.14mA   -13.2mA
3V        -15.17mA   -16.29mA   -13.3mA
[Pulldown]
| Voltage   I(typ)   I(min)   I(max)
-1.5V     -9.481mA   -10.96mA   -6.976mA
-1.083V   -9.197mA   -10.42mA   -7.14mA
-984.4mV  -9.613mA   -10.23mA   -14.19mA
-935.2mV  -12.77mA   -10.12mA   -20.81mA
-885.9mV  -18.63mA   -10.47mA   -23.78mA
-836.7mV  -24.21mA   -13.59mA   -23.85mA
-738.3mV  -25.95mA   -22.91mA   -22.73mA
-590.6mV  -22.29mA   -22.87mA   -19.8mA
281.2mV   9.622mA    9.487mA    9.022mA
843.8mV   21.66mA    21.36mA    20.26mA
1.359V    25.26mA    24.85mA    23.56mA
3V        25.93mA    25.55mA    24.13mA
[Ramp]
dV/dt_r   0.497983/0.348612n  0.504474/0.361831n  0.481418/0.328466n
dV/dt_f   0.533192/0.268755n  0.507095/0.28378n  0.536013/0.277182n
R_load = 50
[Rising Waveform]
R_fixture = 50
V_fixture = 0
V_fixture_min = 0
V_fixture_max = 0
| Time   V(typ)   V(min)   V(max)
0s        13.12nV    18.33nV    18.29nV
1.621ns   836.5uV    656.5uV    -43.23mV
1.922ns   -6.66mV    778.4uV    496.9mV
2.129ns   -55.31mV   862.2uV    676.3mV
2.667ns   686.9mV    -47.39mV   785.2mV
2.836ns   756.3mV    -43.3mV    791.4mV
3.155ns   803.3mV    504.7mV    798.1mV
3.361ns   813.4mV    701.4mV    800.5mV
3.724ns   821mV      806.6mV    801.5mV
10ns      830mV      840.8mV    802.4mV
[Rising Waveform]
R_fixture = 50
V_fixture = 1.5
V_fixture_min = 1.425
V_fixture_max = 1.575
| Time   V(typ)   V(min)   V(max)
0s        611.3mV    579.8mV    681.6mV
1.435ns   610.8mV    579.5mV    682.6mV
1.748ns   610.7mV    579.4mV    1.361V
1.941ns   619.6mV    579.4mV    1.529V
2.152ns   1.063V     579.3mV    1.562V
2.287ns   1.322V     576.9mV    1.569V
2.454ns   1.45V      574.7mV    1.572V
2.959ns   1.496V     1.282V     1.575V
3.233ns   1.499V     1.403V     1.575V
10ns      1.5V       1.425V     1.575V
[Falling Waveform]
R_fixture = 50
V_fixture = 0
V_fixture_min = 0
V_fixture_max = 0
| Time   V(typ)   V(min)   V(max)
0s        830mV      840.7mV    802.4mV
1.477ns   829.2mV    840.1mV    820.1mV
1.776ns   829.4mV    840mV      131.4mV
1.957ns   838.9mV    840mV      30.25mV
2.107ns   499.5mV    839.9mV    11.6mV
2.306ns   118.3mV    839.7mV    4.204mV
2.573ns   16.81mV    868.6mV    777.2uV
2.918ns   3.163mV    182.6mV    332.5uV
3.227ns   959.6uV    20.11mV    -11.5uV
10ns      645.2nV    3.925uV    -52.98nV
[Falling Waveform]
R_fixture = 50
V_fixture = 1.5
V_fixture_min = 1.425
V_fixture_max = 1.575
| Time   V(typ)   V(min)   V(max)
0s        1.5V       1.425V     1.575V
1.575ns   1.5V       1.425V     1.622V
1.897ns   1.5V       1.424V     984.3mV
2.127ns   1.562V     1.424V     764.2mV
2.453ns   878mV      1.42V      696mV
2.777ns   653.5mV    1.5V       684.6mV
3.158ns   618.3mV    795.9mV    682.8mV
3.336ns   615.5mV    661.1mV    682mV
3.613ns   613mV      600.4mV    681.7mV
10ns      611.3mV    579.8mV    681.6mV
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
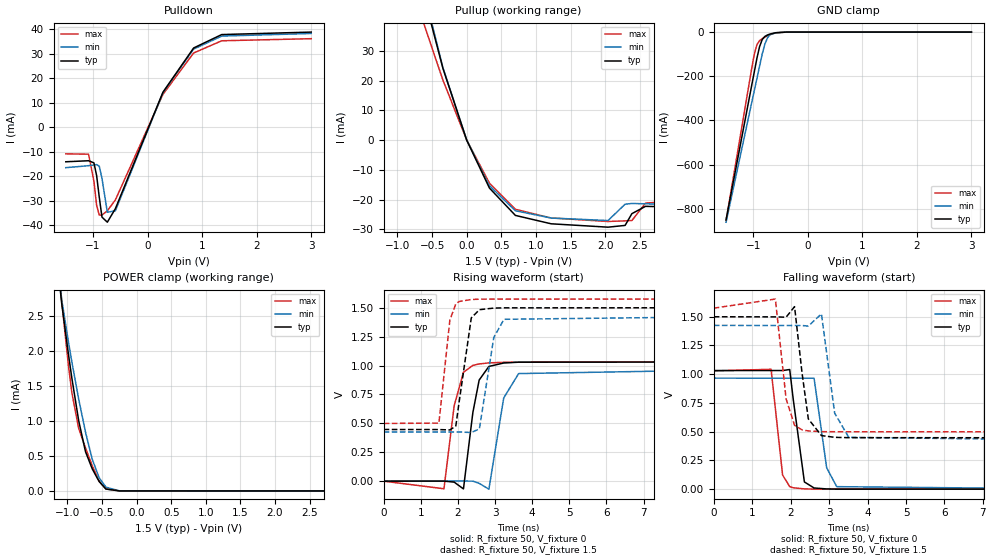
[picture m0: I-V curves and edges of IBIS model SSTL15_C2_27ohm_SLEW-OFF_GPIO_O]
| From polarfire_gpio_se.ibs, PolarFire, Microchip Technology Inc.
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|   Model SSTL15_C2_27ohm_SLEW-OFF_GPIO_O
[Model]   SSTL15_C2_27ohm_SLEW-OFF_GPIO_O
Model_type   Output
Polarity   Non-Inverting
Enable   Active-High
Vmeas =   0.75
Cref =   5p
Rref =   50
Vref =   0.75
|   typ   min   max
C_comp_pullup   2.605e-12   2.605e-12   2.76e-12
C_comp_pulldown  2.605e-12   2.605e-12   2.76e-12
[Temperature Range]  25C   100C   -40C
[Voltage Range]  1.5   1.425   1.575
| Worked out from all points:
|   slope of the pulldown table from 0 to 0.225 V, typ, clamps not added: 19.1 ohm
|   slope of the pullup table from 0 to 0.225 V, typ, clamps not added: 19 ohm
|   GND clamp passes 1 mA (typ) near -0.52 V on its own axis
|   POWER clamp passes 1 mA (typ) near -0.84 V on its own axis
|   rising waveform, R_fixture 50, V_fixture 0: 20-80 % time 266ps typ, 309ps min, 259ps max; typ from 0 V to 1.03 V
|   rising waveform, R_fixture 50, V_fixture 1.5: 20-80 % time 245ps typ, 290ps min, 192ps max; typ from 0.447 V to 1.5 V
|   falling waveform, R_fixture 50, V_fixture 0: 20-80 % time 190ps typ, 242ps min, 173ps max; typ from 1.03 V to 0 V
|   falling waveform, R_fixture 50, V_fixture 1.5: 20-80 % time 209ps typ, 237ps min, 202ps max; typ from 1.5 V to 0.447 V
[GND Clamp]
| Voltage   I(typ)   I(min)   I(max)
-1.5V     -849.7mA   -860.2mA   -853.5mA
-1.034V   -246.6mA   -324.3mA   -170.7mA
-984.4mV  -183.1mA   -267.7mA   -102.9mA
-935.2mV  -119.9mA   -211.2mA   -57.59mA
-885.9mV  -66.33mA   -154.7mA   -38.94mA
-836.7mV  -33.59mA   -99.09mA   -29.82mA
-787.5mV  -19.44mA   -53.53mA   -22.49mA
-738.3mV  -12.87mA   -24.95mA   -16.13mA
-689.1mV  -8.545mA   -11.57mA   -10.81mA
-590.6mV  -2.947mA   -3.067mA   -3.621mA
-393.7mV  -37.64uA   -63.17uA   -40.12uA
3V        0A         0A         0A
[POWER Clamp]
| Voltage   I(typ)   I(min)   I(max)
-1.5V     10.9mA     9.757mA    12.4mA
-1.23V    4.091mA    4.068mA    4.41mA
-1.083V   2.694mA    2.748mA    2.728mA
-984.4mV  1.956mA    2.133mA    1.792mA
-935.2mV  1.615mA    1.848mA    1.408mA
-836.7mV  1.007mA    1.316mA    894.8uA
-738.3mV  562.1uA    843.7uA    616.9uA
-639.8mV  314.2uA    451.1uA    357.6uA
-541.4mV  134.7uA    190.1uA    142.2uA
-443mV    26.83uA    53.65uA    28.29uA
-246.1mV  138.9nA    771.3nA    12.63nA
3V        0A         0A         0A
[Pullup]
| Voltage   I(typ)   I(min)   I(max)
-1.5V     125mA      133mA      96.23mA
-1.083V   90.04mA    93.42mA    71.17mA
-344.5mV  24.23mA    24.46mA    20.26mA
0V        -138.7nA   19.36uA    36.56uA
328.1mV   -16.11mA   -15.32mA   -14.46mA
703.1mV   -25.32mA   -23.75mA   -23.27mA
1.219V    -28.14mA   -26.2mA    -26.19mA
2.041V    -29.28mA   -27.05mA   -27.36mA
2.288V    -28.69mA   -21.55mA   -27.16mA
2.386V    -24.73mA   -21.3mA    -27.04mA
2.583V    -22.27mA   -21.42mA   -21.17mA
3V        -22.5mA    -21.64mA   -20.51mA
[Pulldown]
| Voltage   I(typ)   I(min)   I(max)
-1.5V     -14.06mA   -16.47mA   -10.83mA
-1.083V   -13.64mA   -15.66mA   -10.96mA
-984.4mV  -14.5mA    -15.37mA   -21.99mA
-935.2mV  -19.64mA   -15.21mA   -31.83mA
-885.9mV  -28.61mA   -15.88mA   -35.81mA
-836.7mV  -36.66mA   -20.85mA   -35.82mA
-738.3mV  -38.73mA   -34.68mA   -34.08mA
-590.6mV  -33.19mA   -34.08mA   -29.62mA
281.2mV   14.34mA    14.15mA    13.49mA
843.8mV   32.4mA     31.95mA    30.35mA
1.359V    37.88mA    37.26mA    35.34mA
3V        38.89mA    38.32mA    36.2mA
[Ramp]
dV/dt_r   0.619455/0.266146n  0.579664/0.309193n  0.617681/0.259223n
dV/dt_f   0.631786/0.209055n  0.599768/0.237103n  0.645427/0.201582n
R_load = 50
[Rising Waveform]
R_fixture = 50
V_fixture = 0
V_fixture_min = 0
V_fixture_max = 0
| Time   V(typ)   V(min)   V(max)
0s        9.866nV    13.8nV     13.78nV
1.624ns   769.9uV    583uV      -65.66mV
1.899ns   -8.347mV   681.7uV    652.3mV
2.149ns   -66.78mV   771.4uV    941.9mV
2.402ns   593.2mV    366uV      1.001V
2.572ns   874.6mV    -18.88mV   1.014V
2.834ns   992.3mV    -69.17mV   1.023V
3.233ns   1.022V     719.6mV    1.028V
3.635ns   1.029V     930.5mV    1.029V
10ns      1.032V     966.1mV    1.029V
[Rising Waveform]
R_fixture = 50
V_fixture = 1.5
V_fixture_min = 1.425
V_fixture_max = 1.575
| Time   V(typ)   V(min)   V(max)
0s        447mV      425.4mV    499.3mV
1.488ns   446.3mV    425.3mV    502mV
1.782ns   443mV      425.3mV    1.391V
1.943ns   476.3mV    425.3mV    1.534V
2.033ns   686mV      425.3mV    1.554V
2.36ns    1.412V     420.9mV    1.571V
2.578ns   1.483V     452.1mV    1.574V
2.966ns   1.497V     1.243V     1.575V
3.241ns   1.499V     1.4V       1.575V
10ns      1.5V       1.425V     1.575V
[Falling Waveform]
R_fixture = 50
V_fixture = 0
V_fixture_min = 0
V_fixture_max = 0
| Time   V(typ)   V(min)   V(max)
0s        1.032V     966.1mV    1.029V
1.491ns   1.032V     965.6mV    1.043V
1.79ns    1.032V     965.5mV    122.9mV
1.975ns   1.041V     965.4mV    22.71mV
2.066ns   783.9mV    965.4mV    11.83mV
2.357ns   62.7mV     965.6mV    2.56mV
2.609ns   10.27mV    965mV      637.4uV
2.936ns   2.045mV    186.8mV    223.7uV
3.197ns   742.1uV    21.86mV    67.5uV
10ns      1.539uV    2.946uV    227.9nV
[Falling Waveform]
R_fixture = 50
V_fixture = 1.5
V_fixture_min = 1.425
V_fixture_max = 1.575
| Time   V(typ)   V(min)   V(max)
0s        1.5V       1.425V     1.575V
1.602ns   1.499V     1.424V     1.654V
1.881ns   1.496V     1.424V     785.7mV
2.101ns   1.588V     1.424V     555.5mV
2.296ns   1.01V      1.424V     516.1mV
2.459ns   611.5mV    1.419V     506.6mV
2.8ns     466.2mV    1.525V     500.6mV
3.144ns   451mV      661.7mV    499.8mV
3.511ns   448mV      450.7mV    499.3mV
10ns      447mV      425.4mV    499.3mV
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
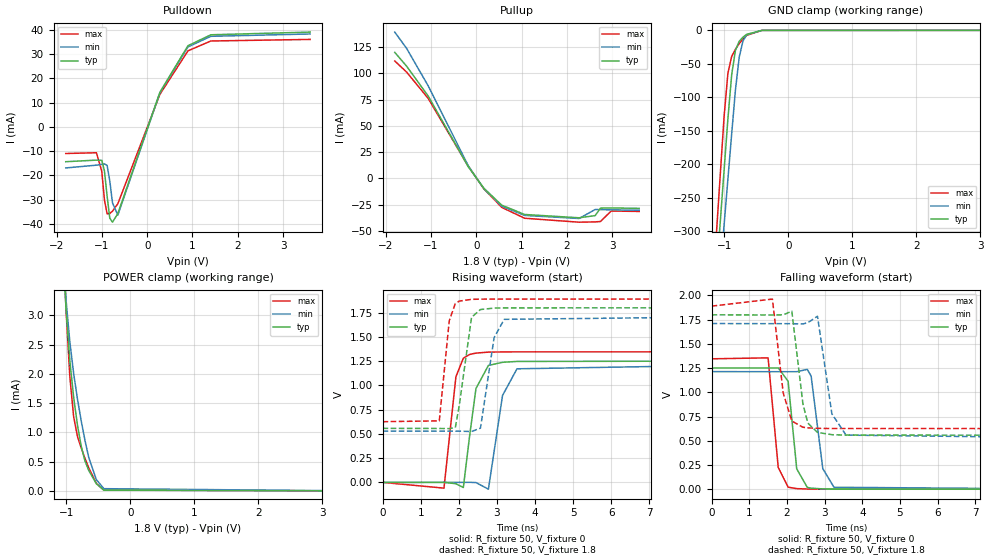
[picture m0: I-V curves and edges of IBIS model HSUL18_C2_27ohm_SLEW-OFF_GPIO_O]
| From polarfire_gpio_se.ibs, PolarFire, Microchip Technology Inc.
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|   Model HSUL18_C2_27ohm_SLEW-OFF_GPIO_O
[Model]   HSUL18_C2_27ohm_SLEW-OFF_GPIO_O
Model_type   Output
Polarity   Non-Inverting
Enable   Active-High
Vmeas =   0.9
Cref =   5p
Rref =   50
Vref =   0.9
|   typ   min   max
C_comp_pullup   2.605e-12   2.605e-12   2.76e-12
C_comp_pulldown  2.605e-12   2.605e-12   2.76e-12
[Temperature Range]  25C   100C   -40C
[Voltage Range]  1.8   1.71   1.89
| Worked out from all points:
|   slope of the pulldown table from 0 to 0.27 V, typ, clamps not added: 19.5 ohm
|   slope of the pullup table from 0 to 0.27 V, typ, clamps not added: 18.9 ohm
|   GND clamp passes 1 mA (typ) near -0.52 V on its own axis
|   POWER clamp passes 1 mA (typ) near -0.81 V on its own axis
|   rising waveform, R_fixture 50, V_fixture 0: 20-80 % time 248ps typ, 275ps min, 208ps max; typ from 0 V to 1.25 V
|   rising waveform, R_fixture 50, V_fixture 1.8: 20-80 % time 224ps typ, 263ps min, 172ps max; typ from 0.557 V to 1.8 V
|   falling waveform, R_fixture 50, V_fixture 0: 20-80 % time 186ps typ, 229ps min, 167ps max; typ from 1.25 V to 0 V
|   falling waveform, R_fixture 50, V_fixture 1.8: 20-80 % time 236ps typ, 261ps min, 231ps max; typ from 1.8 V to 0.557 V
[GND Clamp]
| Voltage   I(typ)   I(min)   I(max)
-1.8V     -1.238A    -1.206A    -1.294A
-1.122V   -361mA     -426.1mA   -300.3mA
-1.063V   -284.7mA   -358.2mA   -213.9mA
-1.004V   -208.5mA   -290.3mA   -128.4mA
-945mV    -132.4mA   -222.5mA   -64.19mA
-885.9mV  -66.33mA   -154.7mA   -38.94mA
-826.9mV  -29.63mA   -88.81mA   -28.27mA
-767.8mV  -16.36mA   -39.95mA   -19.83mA
-708.7mV  -10.12mA   -15.57mA   -12.8mA
-649.7mV  -5.882mA   -6.713mA   -7.364mA
-413.4mV  -69.42uA   -104.8uA   -78.93uA
3.6V      0A         0A         0A
[POWER Clamp]
| Voltage   I(typ)   I(min)   I(max)
-1.8V     45.61mA    35.66mA    60.31mA
-1.063V   4.301mA    4.234mA    4.672mA
-1.004V   3.099mA    3.258mA    3.078mA
-945mV    2.226mA    2.547mA    1.95mA
-885.9mV  1.604mA    2.011mA    1.273mA
-826.9mV  1.131mA    1.577mA    934uA
-767.8mV  765.5uA    1.2mA      735.6uA
-708.7mV  512.4uA    863.2uA    558uA
-649.7mV  349.8uA    570.8uA    394.2uA
-531.6mV  123.5uA    194.8uA    129.3uA
-413.4mV  12.94uA    38.41uA    15.1uA
3.6V      0A         0A         0A
[Pullup]
| Voltage   I(typ)   I(min)   I(max)
-1.8V     120mA      139.3mA    111.8mA
-1.536V   106.7mA    123.6mA    101.1mA
-1.063V   78.5mA     88.21mA    76.24mA
-177.2mV  11.19mA    12.13mA    11.59mA
168.8mV   -9.374mA   -9.835mA   -9.957mA
562.5mV   -25.45mA   -26.43mA   -27.55mA
1.069V    -34.34mA   -35.22mA   -37.93mA
2.272V    -37.49mA   -38.16mA   -41.68mA
2.627V    -35.41mA   -29.63mA   -41.39mA
2.745V    -28.29mA   -29.72mA   -41.01mA
2.981V    -28.12mA   -29.91mA   -31.03mA
3.6V      -28.51mA   -30.33mA   -31.46mA
[Pulldown]
| Voltage   I(typ)   I(min)   I(max)
-1.8V     -14.33mA   -16.9mA    -10.95mA
-1.122V   -13.68mA   -15.76mA   -10.64mA
-1.004V   -13.77mA   -15.43mA   -18.28mA
-945mV    -18.15mA   -15.24mA   -30.12mA
-885.9mV  -28.61mA   -15.88mA   -35.81mA
-826.9mV  -37.62mA   -22.25mA   -35.7mA
-767.8mV  -39.27mA   -31.25mA   -34.71mA
-649.7mV  -35.74mA   -36.37mA   -31.69mA
281.2mV   14.34mA    14.15mA    13.49mA
900mV     33.49mA    33.01mA    31.37mA
1.406V    38mA       37.37mA    35.44mA
3.6V      39.11mA    38.34mA    36.09mA
[Ramp]
dV/dt_r   0.750703/0.247685n  0.728289/0.275352n  0.807614/0.207576n
dV/dt_f   0.745775/0.235611n  0.708766/0.261482n  0.758484/0.230557n
R_load = 50
[Rising Waveform]
R_fixture = 50
V_fixture = 0
V_fixture_min = 0
V_fixture_max = 0
| Time   V(typ)   V(min)   V(max)
0s        10.57nV    14.63nV    14.7nV
1.611ns   865.6uV    397.6uV    -58.99mV
1.924ns   -13.35mV   474.9uV    1.089V
2.119ns   -52.73mV   523uV      1.28V
2.284ns   480.3mV    1.083mV    1.319V
2.45ns    967.6mV    -1.783mV   1.333V
2.777ns   1.206V     -69.7mV    1.343V
3.147ns   1.238V     896.1mV    1.345V
3.526ns   1.247V     1.171V     1.346V
10ns      1.251V     1.214V     1.346V
[Rising Waveform]
R_fixture = 50
V_fixture = 1.8
V_fixture_min = 1.71
V_fixture_max = 1.89
| Time   V(typ)   V(min)   V(max)
0s        557mV      528.7mV    625.9mV
1.488ns   556.2mV    528.2mV    634.5mV
1.75ns    554.4mV    528.1mV    1.668V
1.909ns   565.2mV    528mV      1.844V
2.012ns   792.3mV    528mV      1.869V
2.334ns   1.702V     524.7mV    1.887V
2.568ns   1.782V     559.5mV    1.889V
2.926ns   1.797V     1.492V     1.89V
3.191ns   1.799V     1.681V     1.89V
10ns      1.8V       1.71V      1.89V
[Falling Waveform]
R_fixture = 50
V_fixture = 0
V_fixture_min = 0
V_fixture_max = 0
| Time   V(typ)   V(min)   V(max)
0s        1.251V     1.214V     1.346V
1.5ns     1.252V     1.213V     1.356V
1.769ns   1.252V     1.213V     225.3mV
2.032ns   1.114V     1.213V     20.43mV
2.26ns    210mV      1.213V     5.534mV
2.54ns    18mV       1.237V     1.605mV
2.643ns   10.54mV    1.167V     764.8uV
2.952ns   2.541mV    212mV      307.6uV
3.249ns   860.2uV    19.68mV    13.45uV
10ns      1.674uV    2.516uV    605.2nV
[Falling Waveform]
R_fixture = 50
V_fixture = 1.8
V_fixture_min = 1.71
V_fixture_max = 1.89
| Time   V(typ)   V(min)   V(max)
0s        1.8V       1.71V      1.89V
1.615ns   1.799V     1.709V     1.963V
1.901ns   1.8V       1.709V     993.3mV
2.13ns    1.838V     1.709V     703.3mV
2.424ns   882.2mV    1.706V     639.5mV
2.555ns   682.2mV    1.719V     633.4mV
2.811ns   586.2mV    1.786V     628.2mV
3.193ns   562.4mV    778.6mV    626.3mV
3.568ns   558.5mV    558.1mV    626mV
10ns      557mV      528.7mV    625.9mV
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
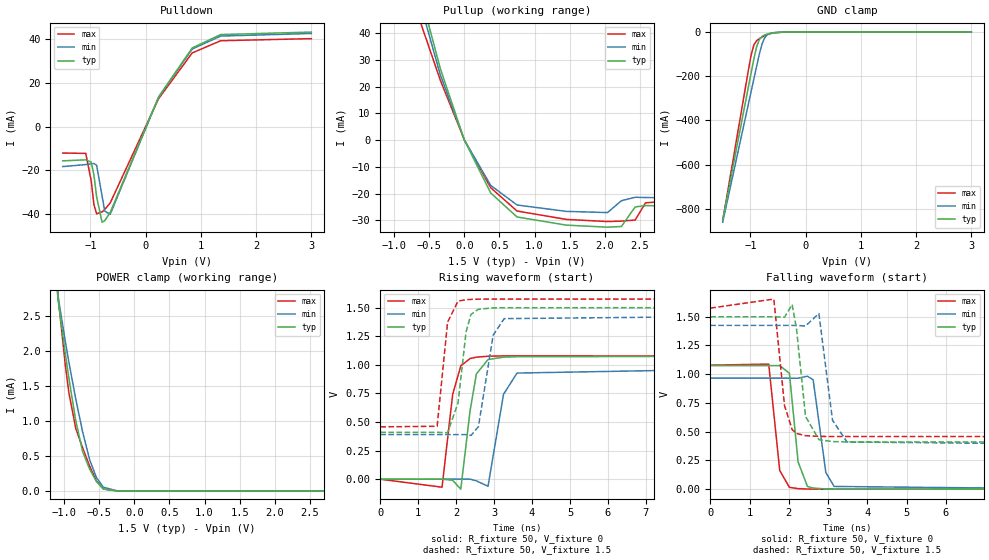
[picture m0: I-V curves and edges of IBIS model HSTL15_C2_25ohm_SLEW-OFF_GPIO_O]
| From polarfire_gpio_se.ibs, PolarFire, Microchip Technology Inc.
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|   Model HSTL15_C2_25ohm_SLEW-OFF_GPIO_O
[Model]   HSTL15_C2_25ohm_SLEW-OFF_GPIO_O
Model_type   Output
Polarity   Non-Inverting
Enable   Active-High
Vmeas =   0.75
Cref =   5p
Rref =   50
Vref =   0.75
|   typ   min   max
C_comp_pullup   2.605e-12   2.605e-12   2.76e-12
C_comp_pulldown  2.605e-12   2.605e-12   2.76e-12
[Temperature Range]  25C   100C   -40C
[Voltage Range]  1.5   1.425   1.575
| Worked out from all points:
|   slope of the pulldown table from 0 to 0.225 V, typ, clamps not added: 17.2 ohm
|   slope of the pullup table from 0 to 0.225 V, typ, clamps not added: 17.1 ohm
|   GND clamp passes 1 mA (typ) near -0.52 V on its own axis
|   POWER clamp passes 1 mA (typ) near -0.84 V on its own axis
|   rising waveform, R_fixture 50, V_fixture 0: 20-80 % time 242ps typ, 311ps min, 234ps max; typ from 0 V to 1.07 V
|   rising waveform, R_fixture 50, V_fixture 1.5: 20-80 % time 223ps typ, 302ps min, 183ps max; typ from 0.41 V to 1.5 V
|   falling waveform, R_fixture 50, V_fixture 0: 20-80 % time 191ps typ, 222ps min, 177ps max; typ from 1.07 V to 0 V
|   falling waveform, R_fixture 50, V_fixture 1.5: 20-80 % time 202ps typ, 208ps min, 194ps max; typ from 1.5 V to 0.41 V
[GND Clamp]
| Voltage   I(typ)   I(min)   I(max)
-1.5V     -849.7mA   -860.2mA   -853.5mA
-1.034V   -246.6mA   -324.3mA   -170.7mA
-984.4mV  -183.1mA   -267.7mA   -102.9mA
-935.2mV  -119.9mA   -211.2mA   -57.59mA
-885.9mV  -66.33mA   -154.7mA   -38.94mA
-836.7mV  -33.59mA   -99.09mA   -29.82mA
-787.5mV  -19.44mA   -53.53mA   -22.49mA
-738.3mV  -12.87mA   -24.95mA   -16.13mA
-689.1mV  -8.545mA   -11.57mA   -10.81mA
-590.6mV  -2.947mA   -3.067mA   -3.621mA
-393.7mV  -37.64uA   -63.17uA   -40.12uA
3V        0A         0A         0A
[POWER Clamp]
| Voltage   I(typ)   I(min)   I(max)
-1.5V     10.9mA     9.757mA    12.4mA
-1.23V    4.091mA    4.068mA    4.41mA
-1.083V   2.694mA    2.748mA    2.728mA
-984.4mV  1.956mA    2.133mA    1.792mA
-935.2mV  1.616mA    1.848mA    1.408mA
-836.7mV  1.007mA    1.316mA    894.8uA
-738.3mV  562.1uA    843.7uA    616.9uA
-639.8mV  314.2uA    451.1uA    357.6uA
-541.4mV  134.7uA    190.1uA    142.2uA
-443mV    26.83uA    53.65uA    28.29uA
-246.1mV  138.9nA    771.1nA    12.63nA
3V        0A         0A         0A
[Pullup]
| Voltage   I(typ)   I(min)   I(max)
-1.5V     138.4mA    133mA      106.8mA
-1.083V   99.65mA    93.42mA    78.93mA
-344.5mV  26.82mA    24.46mA    22.47mA
0V        -138.7nA   19.34uA    40.42uA
375mV     -19.73mA   -16.89mA   -17.78mA
750mV     -28.7mA    -24.22mA   -26.47mA
1.453V    -31.75mA   -26.61mA   -29.61mA
2.041V    -32.51mA   -27.05mA   -30.41mA
2.238V    -32.25mA   -22.63mA   -30.25mA
2.435V    -24.95mA   -21.33mA   -29.84mA
2.583V    -24.43mA   -21.42mA   -23.41mA
3V        -24.68mA   -21.64mA   -22.64mA
[Pulldown]
| Voltage   I(typ)   I(min)   I(max)
-1.5V     -15.62mA   -18.23mA   -12.05mA
-1.083V   -15.15mA   -17.32mA   -12.21mA
-984.4mV  -16.19mA   -17mA      -24.68mA
-935.2mV  -22.06mA   -16.83mA   -35.55mA
-885.9mV  -32.1mA    -17.67mA   -39.81mA
-787.5mV  -43.64mA   -31.66mA   -38.95mA
-738.3mV  -42.97mA   -38.61mA   -37.83mA
-639.8mV  -39.18mA   -40mA      -34.81mA
234.4mV   13.54mA    13.35mA    12.75mA
843.8mV   35.96mA    35.46mA    33.69mA
1.359V    42.08mA    41.39mA    39.26mA
3V        43.21mA    42.58mA    40.22mA
[Ramp]
dV/dt_r   0.645281/0.242426n  0.579699/0.31119n  0.64752/0.234246n
dV/dt_f   0.65406/0.202177n  0.620721/0.208477n  0.6703/0.193834n
R_load = 50
[Rising Waveform]
R_fixture = 50
V_fixture = 0
V_fixture_min = 0
V_fixture_max = 0
| Time   V(typ)   V(min)   V(max)
0s        9.117nV    12.76nV    12.75nV
1.628ns   789.3uV    547.2uV    -70.13mV
1.908ns   -9.439mV   641.3uV    740.7mV
2.122ns   -87.26mV   713.2uV    991.2mV
2.367ns   598.7mV    398.7uV    1.055V
2.533ns   920.4mV    -14.67mV   1.067V
2.84ns    1.046V     -62.06mV   1.075V
3.248ns   1.067V     741.7mV    1.078V
3.604ns   1.071V     927.9mV    1.078V
10ns      1.075V     966.2mV    1.079V
[Rising Waveform]
R_fixture = 50
V_fixture = 1.5
V_fixture_min = 1.425
V_fixture_max = 1.575
| Time   V(typ)   V(min)   V(max)
0s        409.9mV    390.5mV    457.8mV
1.499ns   409.2mV    390mV      462.7mV
1.774ns   407mV      390mV      1.372V
2.049ns   665.2mV    389.9mV    1.557V
2.262ns   1.289V     389.8mV    1.57V
2.391ns   1.441V     382.8mV    1.572V
2.586ns   1.486V     458.9mV    1.574V
2.976ns   1.498V     1.259V     1.575V
3.266ns   1.499V     1.404V     1.575V
10ns      1.5V       1.425V     1.575V
[Falling Waveform]
R_fixture = 50
V_fixture = 0
V_fixture_min = 0
V_fixture_max = 0
| Time   V(typ)   V(min)   V(max)
0s        1.075V     966.1mV    1.079V
1.488ns   1.075V     965.6mV    1.088V
1.768ns   1.075V     965.5mV    162.3mV
2.015ns   1.008V     965.4mV    15.82mV
2.236ns   236.9mV    965.3mV    4.368mV
2.473ns   23.92mV    983mV      1.384mV
2.619ns   9.381mV    951.9mV    645.8uV
2.942ns   1.793mV    145.1mV    436uV
3.152ns   841.6uV    23.63mV    423.1uV
10ns      -205.8nV   3.033uV    88.25nV
[Falling Waveform]
R_fixture = 50
V_fixture = 1.5
V_fixture_min = 1.425
V_fixture_max = 1.575
| Time   V(typ)   V(min)   V(max)
0s        1.5V       1.425V     1.575V
1.618ns   1.5V       1.425V     1.654V
1.891ns   1.496V     1.425V     726.4mV
2.084ns   1.606V     1.425V     518.9mV
2.195ns   1.396V     1.424V     484.8mV
2.425ns   633.3mV    1.42V      465.3mV
2.765ns   431mV      1.528V     459.5mV
3.112ns   413.9mV    599.3mV    458.1mV
3.481ns   410.9mV    410.3mV    458mV
10ns      409.9mV    390.5mV    457.8mV
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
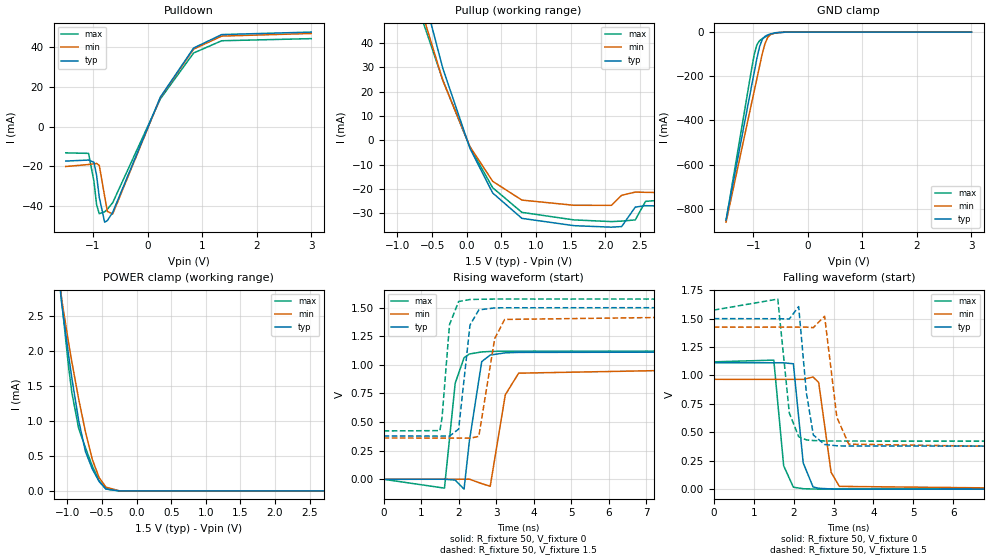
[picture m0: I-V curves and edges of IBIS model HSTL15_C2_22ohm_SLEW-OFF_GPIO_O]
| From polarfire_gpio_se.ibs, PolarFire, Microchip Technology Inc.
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|   Model HSTL15_C2_22ohm_SLEW-OFF_GPIO_O
[Model]   HSTL15_C2_22ohm_SLEW-OFF_GPIO_O
Model_type   Output
Polarity   Non-Inverting
Enable   Active-High
Vmeas =   0.75
Cref =   5p
Rref =   50
Vref =   0.75
|   typ   min   max
C_comp_pullup   2.605e-12   2.605e-12   2.76e-12
C_comp_pulldown  2.605e-12   2.605e-12   2.76e-12
[Temperature Range]  25C   100C   -40C
[Voltage Range]  1.5   1.425   1.575
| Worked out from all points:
|   slope of the pulldown table from 0 to 0.225 V, typ, clamps not added: 15.7 ohm
|   slope of the pullup table from 0 to 0.225 V, typ, clamps not added: 15.6 ohm
|   GND clamp passes 1 mA (typ) near -0.52 V on its own axis
|   POWER clamp passes 1 mA (typ) near -0.84 V on its own axis
|   rising waveform, R_fixture 50, V_fixture 0: 20-80 % time 226ps typ, 311ps min, 218ps max; typ from 0 V to 1.11 V
|   rising waveform, R_fixture 50, V_fixture 1.5: 20-80 % time 216ps typ, 293ps min, 167ps max; typ from 0.378 V to 1.5 V
|   falling waveform, R_fixture 50, V_fixture 0: 20-80 % time 182ps typ, 221ps min, 167ps max; typ from 1.11 V to 0 V
|   falling waveform, R_fixture 50, V_fixture 1.5: 20-80 % time 177ps typ, 211ps min, 181ps max; typ from 1.5 V to 0.378 V
[GND Clamp]
| Voltage   I(typ)   I(min)   I(max)
-1.5V     -849.7mA   -860.2mA   -853.5mA
-1.034V   -246.6mA   -324.3mA   -170.7mA
-984.4mV  -183.1mA   -267.7mA   -102.9mA
-935.2mV  -119.9mA   -211.2mA   -57.59mA
-885.9mV  -66.33mA   -154.7mA   -38.94mA
-836.7mV  -33.59mA   -99.09mA   -29.82mA
-787.5mV  -19.44mA   -53.53mA   -22.49mA
-738.3mV  -12.87mA   -24.95mA   -16.13mA
-689.1mV  -8.545mA   -11.57mA   -10.81mA
-590.6mV  -2.947mA   -3.067mA   -3.621mA
-393.7mV  -37.64uA   -63.17uA   -40.12uA
3V        0A         0A         0A
[POWER Clamp]
| Voltage   I(typ)   I(min)   I(max)
-1.5V     10.9mA     9.757mA    12.4mA
-1.23V    4.091mA    4.068mA    4.41mA
-1.083V   2.694mA    2.748mA    2.728mA
-984.4mV  1.956mA    2.133mA    1.792mA
-935.2mV  1.615mA    1.848mA    1.408mA
-836.7mV  1.007mA    1.316mA    894.8uA
-738.3mV  562.1uA    843.7uA    616.9uA
-639.8mV  314.2uA    451.1uA    357.6uA
-541.4mV  134.7uA    190.1uA    142.2uA
-443mV    26.83uA    53.65uA    28.29uA
-246.1mV  138.9nA    771.1nA    12.63nA
3V        0A         0A         0A
[Pullup]
| Voltage   I(typ)   I(min)   I(max)
-1.5V     152.1mA    133mA      117mA
-1.083V   109.4mA    93.42mA    86.47mA
-344.5mV  29.44mA    24.46mA    24.62mA
46.88mV   -3.363mA   -2.639mA   -2.952mA
375mV     -21.69mA   -16.89mA   -19.53mA
796.9mV   -32.12mA   -24.61mA   -29.66mA
1.549V    -35.12mA   -26.74mA   -32.75mA
2.091V    -35.74mA   -26.76mA   -33.45mA
2.238V    -35.49mA   -22.63mA   -33.24mA
2.435V    -27.49mA   -21.33mA   -32.75mA
2.583V    -26.91mA   -21.42mA   -25.15mA
3V        -27.18mA   -21.64mA   -24.18mA
[Pulldown]
| Voltage   I(typ)   I(min)   I(max)
-1.5V     -17.31mA   -20.04mA   -13.19mA
-1.083V   -16.79mA   -19.04mA   -13.43mA
-984.4mV  -17.91mA   -18.69mA   -27.39mA
-935.2mV  -24.48mA   -18.5mA    -39.27mA
-885.9mV  -35.62mA   -19.51mA   -43.78mA
-787.5mV  -48.03mA   -35.06mA   -42.79mA
-738.3mV  -47.24mA   -42.58mA   -41.55mA
-639.8mV  -43.06mA   -43.91mA   -38.22mA
234.4mV   14.87mA    14.66mA    13.99mA
843.8mV   39.53mA    38.97mA    37.03mA
1.359V    46.29mA    45.52mA    43.18mA
3V        47.53mA    46.84mA    44.24mA
[Ramp]
dV/dt_r   0.667036/0.225521n  0.579688/0.311239n  0.672238/0.2183n
dV/dt_f   0.673101/0.176675n  0.638536/0.211074n  0.691389/0.181444n
R_load = 50
[Rising Waveform]
R_fixture = 50
V_fixture = 0
V_fixture_min = 0
V_fixture_max = 0
| Time   V(typ)   V(min)   V(max)
0s        8.469nV    11.86nV    11.86nV
1.622ns   613.6uV    507.8uV    -77.1mV
1.908ns   -6.843mV   597.4uV    839.8mV
2.144ns   -86.26mV   671.2uV    1.062V
2.286ns   333.6mV    1.068mV    1.095V
2.615ns   1.028V     -37.74mV   1.113V
2.842ns   1.086V     -60.76mV   1.117V
3.244ns   1.105V     738.1mV    1.12V
3.6ns     1.109V     927.4mV    1.12V
10ns      1.112V     966.1mV    1.12V
[Rising Waveform]
R_fixture = 50
V_fixture = 1.5
V_fixture_min = 1.425
V_fixture_max = 1.575
| Time   V(typ)   V(min)   V(max)
0s        378.2mV    360.8mV    422.7mV
1.5ns     377.6mV    360.2mV    425.3mV
1.557ns   377.6mV    360.2mV    537.4mV
1.756ns   377.5mV    360.1mV    1.351V
2ns       438.7mV    360mV      1.554V
2.303ns   1.348V     359.3mV    1.571V
2.538ns   1.48V      375mV      1.573V
2.961ns   1.498V     1.229V     1.575V
3.228ns   1.499V     1.397V     1.575V
10ns      1.5V       1.425V     1.575V
[Falling Waveform]
R_fixture = 50
V_fixture = 0
V_fixture_min = 0
V_fixture_max = 0
| Time   V(typ)   V(min)   V(max)
0s        1.112V     966.1mV    1.12V
1.504ns   1.111V     965.5mV    1.135V
1.751ns   1.111V     965.4mV    205.7mV
1.994ns   1.103V     965.3mV    17.27mV
2.241ns   230.4mV    965.2mV    3.962mV
2.488ns   19.24mV    986.6mV    1.275mV
2.629ns   8.036mV    937.5mV    841.4uV
2.939ns   1.695mV    148.8mV    806uV
3.146ns   659uV      24.42mV    782.4uV
10ns      196.7nV    2.176uV    404.1nV
[Falling Waveform]
R_fixture = 50
V_fixture = 1.5
V_fixture_min = 1.425
V_fixture_max = 1.575
| Time   V(typ)   V(min)   V(max)
0s        1.5V       1.425V     1.575V
1.604ns   1.499V     1.425V     1.672V
1.893ns   1.497V     1.425V     669.2mV
2.127ns   1.606V     1.425V     461.3mV
2.318ns   852.9mV    1.425V     433.5mV
2.494ns   476.6mV    1.421V     427.6mV
2.777ns   392.9mV    1.521V     424.2mV
3.084ns   381.4mV    631.7mV    422.9mV
3.382ns   379.2mV    395.7mV    422.9mV
10ns      378.2mV    360.8mV    422.7mV
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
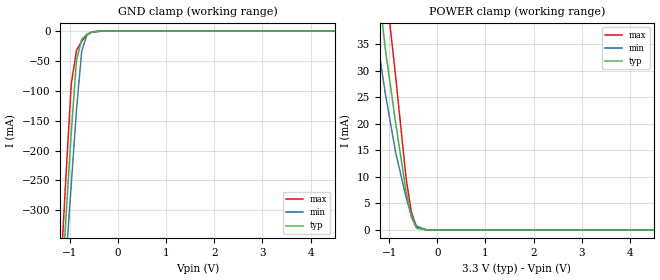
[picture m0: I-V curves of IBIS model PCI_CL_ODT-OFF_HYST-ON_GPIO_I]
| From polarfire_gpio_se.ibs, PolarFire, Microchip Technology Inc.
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|   Model PCI_CL_ODT-OFF_HYST-ON_GPIO_I
[Model]   PCI_CL_ODT-OFF_HYST-ON_GPIO_I
Model_type   Input
Vinl =   0.99
Vinh =   1.65
|   typ   min   max
C_comp_pullup   2.605e-12   2.605e-12   2.76e-12
C_comp_pulldown  2.605e-12   2.605e-12   2.76e-12
[Model Spec]
Vinh+   1.733   1.654   1.811
Vinh-   1.733   1.654   1.811
Vinl+   1.568   1.496   1.639
Vinl-   1.568   1.496   1.639
[Temperature Range]  25C   100C   -40C
[Voltage Range]  3.3   3.135   3.465
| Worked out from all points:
|   GND clamp passes 1 mA (typ) near -0.53 V on its own axis
|   POWER clamp passes 1 mA (typ) near -0.47 V on its own axis
[GND Clamp]
| Voltage   I(typ)   I(min)   I(max)
-3.3V     -3.213A    -2.957A    -3.541A
-1.191V   -449.3mA   -505mA     -398.4mA
-1.083V   -309.2mA   -380.6mA   -239.7mA
-974.5mV  -169.2mA   -256.1mA   -88.53mA
-866.2mV  -48.93mA   -131.7mA   -32.27mA
-758mV    -13.75mA   -33.64mA   -16.94mA
-649.7mV  -5.158mA   -6.075mA   -6.593mA
-541.4mV  -1.115mA   -1.146mA   -1.479mA
-324.8mV  -2.612uA   -7.214uA   -1.709uA
6.6V      0A         0A         0A
[POWER Clamp]
| Voltage   I(typ)   I(min)   I(max)
-3.3V     275.2mA    221.4mA    330.9mA
-1.516V   71.72mA    54.23mA    92.82mA
-1.408V   61.87mA    46.56mA    80.48mA
-1.299V   52.29mA    39.25mA    68.39mA
-1.191V   42.98mA    32.31mA    56.96mA
-1.083V   34.17mA    25.78mA    46.86mA
-866.2mV  20.14mA    14.56mA    28.83mA
-649.7mV  7.231mA    6.113mA    9.746mA
-541.4mV  2.468mA    2.743mA    3.418mA
-433.1mV  320uA      727.2uA    546.2uA
-216.6mV  124.9nA    3.979uA    90.42nA
6.6V      0A         0A         0A
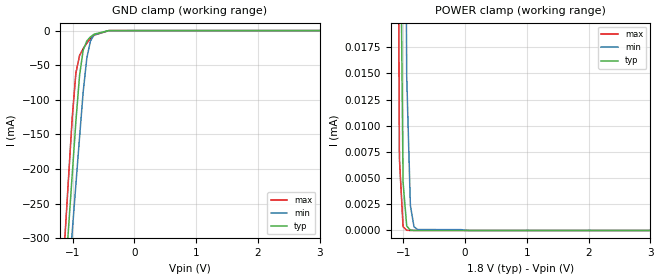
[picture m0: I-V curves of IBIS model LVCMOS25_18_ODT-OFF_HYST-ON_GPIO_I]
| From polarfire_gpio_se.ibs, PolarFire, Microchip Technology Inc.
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|   Model LVCMOS25_18_ODT-OFF_HYST-ON_GPIO_I
[Model]   LVCMOS25_18_ODT-OFF_HYST-ON_GPIO_I
Model_type   Input
Vinl =   0.7
Vinh =   1.7
|   typ   min   max
C_comp_pullup   2.605e-12   2.605e-12   2.76e-12
C_comp_pulldown  2.605e-12   2.605e-12   2.76e-12
[Model Spec]
Vinh+   1.313   1.247   1.378
Vinh-   1.313   1.247   1.378
Vinl+   1.188   1.128   1.247
Vinl-   1.188   1.128   1.247
[Temperature Range]  25C   100C   -40C
[Voltage Range]  1.8   1.71   1.89
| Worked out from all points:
|   GND clamp passes 1 mA (typ) near -0.53 V on its own axis
[GND Clamp]
| Voltage   I(typ)   I(min)   I(max)
-1.8V     -1.238A    -1.206A    -1.294A
-1.122V   -360.2mA   -425.9mA   -297.3mA
-1.063V   -283.8mA   -358mA     -210.9mA
-1.004V   -207.4mA   -290mA     -125.4mA
-945mV    -131.1mA   -222.2mA   -61.15mA
-885.9mV  -64.84mA   -154.3mA   -36.15mA
-826.9mV  -28.05mA   -88.35mA   -26.02mA
-767.8mV  -14.97mA   -39.36mA   -18.12mA
-708.7mV  -9.067mA   -14.9mA    -11.6mA
-649.7mV  -5.157mA   -6.074mA   -6.592mA
-413.4mV  -46.15uA   -72.15uA   -56.26uA
3.6V      0A         0A         0A
[POWER Clamp]
| Voltage   I(typ)   I(min)   I(max)
-1.8V     687.7uA    1.13mA     736.2uA
-1.122V   247.5uA    167.5uA    79.37uA
-1.063V   40.35uA    140.6uA    6.852uA
-1.004V   4.6uA      75.51uA    361.6nA
-945mV    422.9nA    14.68uA    16.75nA
-885.9mV  36.91nA    2.392uA    1.542nA
-826.9mV  3.957nA    351.2nA    680.5pA
-767.8mV  978.3pA    89.16nA    600.1pA
-59.06mV  295.2pA    75.93nA    64.18pA
56.25mV   0A         0A         0A
3.6V      0A         0A         0A
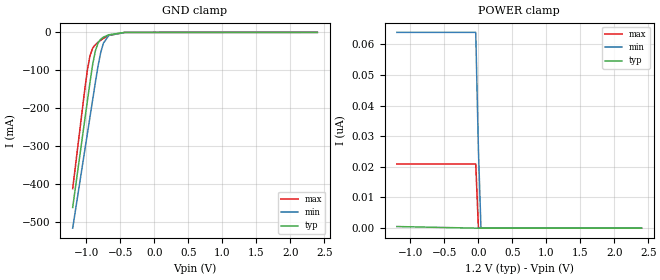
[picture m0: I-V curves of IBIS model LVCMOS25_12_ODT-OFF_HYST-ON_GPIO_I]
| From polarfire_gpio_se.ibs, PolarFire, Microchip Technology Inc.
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|   Model LVCMOS25_12_ODT-OFF_HYST-ON_GPIO_I
[Model]   LVCMOS25_12_ODT-OFF_HYST-ON_GPIO_I
Model_type   Input
Vinl =   0.7
Vinh =   1.7
|   typ   min   max
C_comp_pullup   2.605e-12   2.605e-12   2.76e-12
C_comp_pulldown  2.605e-12   2.605e-12   2.76e-12
[Model Spec]
Vinh+   1.313   1.247   1.378
Vinh-   1.313   1.247   1.378
Vinl+   1.188   1.128   1.247
Vinl-   1.188   1.128   1.247
[Temperature Range]  25C   100C   -40C
[Voltage Range]  1.2   1.14   1.26
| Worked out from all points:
|   GND clamp passes 1 mA (typ) near -0.53 V on its own axis
[GND Clamp]
| Voltage   I(typ)   I(min)   I(max)
-1.2V     -460.9mA   -515.3mA   -411.5mA
-1.024V   -232.8mA   -312.7mA   -153.3mA
-984.4mV  -181.9mA   -267.4mA   -99.94mA
-945mV    -131.1mA   -222.2mA   -61.15mA
-905.6mV  -84.23mA   -176.9mA   -41.34mA
-866.2mV  -48.93mA   -131.7mA   -32.26mA
-826.9mV  -28.05mA   -88.35mA   -26.02mA
-787.5mV  -17.96mA   -52.99mA   -20.61mA
-748.1mV  -12.65mA   -28.64mA   -15.79mA
-669.4mV  -6.309mA   -8.083mA   -8.082mA
-433.1mV  -82.31uA   -116.2uA   -108.2uA
2.4V      0A         0A         0A
[POWER Clamp]
| Voltage   I(typ)   I(min)   I(max)
-1.2V     519.2pA    63.89nA    20.93nA
-39.38mV  -1.999pA   63.89nA    20.93nA
0V        0A         25.56nA    0A
37.5mV    0A         0A         0A
2.4V      0A         0A         0A
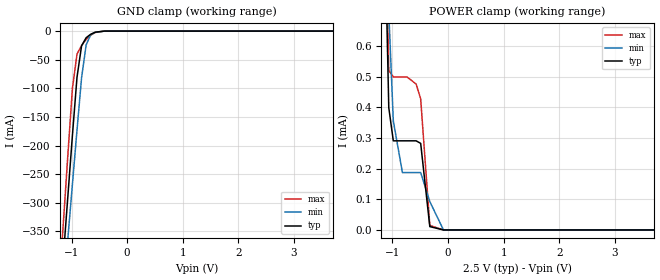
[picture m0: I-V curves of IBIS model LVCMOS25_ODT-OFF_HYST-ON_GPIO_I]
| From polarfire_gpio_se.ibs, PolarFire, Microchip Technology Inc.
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|   Model LVCMOS25_ODT-OFF_HYST-ON_GPIO_I
[Model]   LVCMOS25_ODT-OFF_HYST-ON_GPIO_I
Model_type   Input
Vinl =   0.7
Vinh =   1.7
|   typ   min   max
C_comp_pullup   2.605e-12   2.605e-12   2.76e-12
C_comp_pulldown  2.605e-12   2.605e-12   2.76e-12
[Model Spec]
Vinh+   1.313   1.247   1.378
Vinh-   1.313   1.247   1.378
Vinl+   1.188   1.128   1.247
Vinl-   1.188   1.128   1.247
[Temperature Range]  25C   100C   -40C
[Voltage Range]  2.5   2.375   2.625
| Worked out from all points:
|   GND clamp passes 1 mA (typ) near -0.52 V on its own axis
|   POWER clamp passes 1 mA (typ) near -1.14 V on its own axis
[GND Clamp]
| Voltage   I(typ)   I(min)   I(max)
-2.5V     -2.154A    -2.019A    -2.334A
-1.312V   -606.5mA   -644.5mA   -576.7mA
-1.148V   -394.1mA   -456mA     -335.8mA
-1.066V   -288mA     -361.7mA   -215.7mA
-984.4mV  -181.9mA   -267.4mA   -99.94mA
-902.3mV  -80.78mA   -173.2mA   -40.34mA
-820.3mV  -25.8mA    -81.78mA   -25.07mA
-738.3mV  -11.65mA   -24.31mA   -14.68mA
-656.2mV  -5.525mA   -6.674mA   -7.068mA
-574.2mV  -1.954mA   -1.999mA   -2.52mA
-410.2mV  -41.8uA    -66.55uA   -50.18uA
5V        0A         0A         0A
[POWER Clamp]
| Voltage   I(typ)   I(min)   I(max)
-2.5V     56.69mA    37.57mA    83.75mA
-1.148V   1.079mA    1.117mA    1.211mA
-1.066V   399uA      709.9uA    520.5uA
-984.4mV  290.7uA    355.8uA    498.9uA
-820.3mV  290.7uA    187.2uA    498.9uA
-738.3mV  290.7uA    187.2uA    498.9uA
-574.2mV  290.7uA    187.2uA    475.9uA
-492.2mV  282.4uA    187.2uA    427.6uA
-328.1mV  11.03uA    92.62uA    14.83uA
-82.03mV  4.148nA    34.17nA    42.37nA
5V        0A         0A         0A
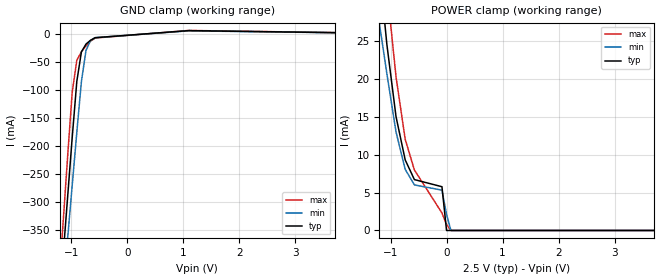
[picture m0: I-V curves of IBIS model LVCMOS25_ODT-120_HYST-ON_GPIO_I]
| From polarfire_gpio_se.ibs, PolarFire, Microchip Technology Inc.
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|   Model LVCMOS25_ODT-120_HYST-ON_GPIO_I
[Model]   LVCMOS25_ODT-120_HYST-ON_GPIO_I
Model_type   Input
Vinl =   0.7
Vinh =   1.7
|   typ   min   max
C_comp_pullup   2.605e-12   2.605e-12   2.76e-12
C_comp_pulldown  2.605e-12   2.605e-12   2.76e-12
[Model Spec]
Vinh+   1.313   1.247   1.378
Vinh-   1.313   1.247   1.378
Vinl+   1.188   1.128   1.247
Vinl-   1.188   1.128   1.247
[Temperature Range]  25C   100C   -40C
[Voltage Range]  2.5   2.375   2.625
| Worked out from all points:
|   GND clamp passes 1 mA (typ) near -0.11 V on its own axis
|   POWER clamp passes 1 mA (typ) near -0.01 V on its own axis
[GND Clamp]
| Voltage   I(typ)   I(min)   I(max)
-2.5V     -2.156A    -2.021A    -2.335A
-1.23V    -502.5mA   -552.6mA   -458.1mA
-1.148V   -396.3mA   -458.3mA   -337.8mA
-1.066V   -290.3mA   -364mA     -218mA
-984.4mV  -184.4mA   -269.7mA   -104.1mA
-902.3mV  -84.93mA   -175.5mA   -47.27mA
-820.3mV  -32.45mA   -85.19mA   -32.32mA
-738.3mV  -18.55mA   -29.57mA   -21.66mA
-656.2mV  -11.66mA   -12.42mA   -13.22mA
-574.2mV  -7.219mA   -7.126mA   -7.761mA
1.094V    5.396mA    4.977mA    5.68mA
5V        0A         0A         0A
[POWER Clamp]
| Voltage   I(typ)   I(min)   I(max)
-2.5V     167mA      131.6mA    207.9mA
-1.312V   43.5mA     33.13mA    57.52mA
-1.23V    37.31mA    28.82mA    48.7mA
-1.148V   30.82mA    24.84mA    39.92mA
-1.066V   24.63mA    20.75mA    32.15mA
-902.3mV  15.06mA    13.03mA    20.33mA
-738.3mV  9.333mA    8.09mA     12.06mA
-574.2mV  6.727mA    6.025mA    8mA
-82.03mV  5.785mA    5.329mA    2.319mA
0V        0A         2.13mA     797.2uA
78.12mV   0A         0A         0A
5V        0A         0A         0A
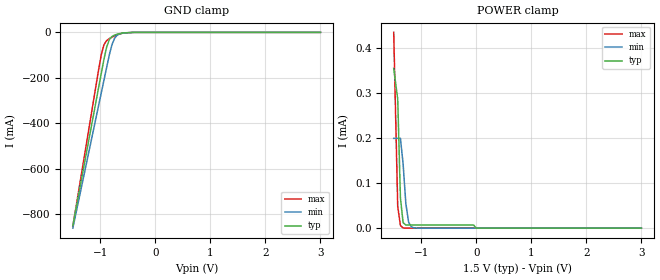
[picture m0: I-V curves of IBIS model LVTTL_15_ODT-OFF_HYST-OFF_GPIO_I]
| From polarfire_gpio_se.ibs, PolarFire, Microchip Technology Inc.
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|   Model LVTTL_15_ODT-OFF_HYST-OFF_GPIO_I
[Model]   LVTTL_15_ODT-OFF_HYST-OFF_GPIO_I
Model_type   Input
Vinl =   0.8
Vinh =   2.0
|   typ   min   max
C_comp_pullup   2.605e-12   2.605e-12   2.76e-12
C_comp_pulldown  2.605e-12   2.605e-12   2.76e-12
[Temperature Range]  25C   100C   -40C
[Voltage Range]  1.5   1.425   1.575
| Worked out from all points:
|   GND clamp passes 1 mA (typ) near -0.53 V on its own axis
[GND Clamp]
| Voltage   I(typ)   I(min)   I(max)
-1.5V     -849.3mA   -860.1mA   -852.3mA
-1.034V   -245.6mA   -324mA     -167.7mA
-984.4mV  -181.9mA   -267.4mA   -99.94mA
-935.2mV  -118.6mA   -210.9mA   -54.55mA
-885.9mV  -64.84mA   -154.3mA   -36.15mA
-836.7mV  -32mA      -98.64mA   -27.47mA
-787.5mV  -17.96mA   -52.99mA   -20.61mA
-738.3mV  -11.65mA   -24.31mA   -14.68mA
-689.1mV  -7.607mA   -10.89mA   -9.751mA
-590.6mV  -2.494mA   -2.583mA   -3.194mA
-393.7mV  -25.22uA   -44.16uA   -27.71uA
3V        0A         0A         0A
[POWER Clamp]
| Voltage   I(typ)   I(min)   I(max)
-1.5V     355.1uA    199.5uA    435uA
-1.427V   286.8uA    199.5uA    48.38uA
-1.378V   67.3uA     199.5uA    5.755uA
-1.329V   12.04uA    142.4uA    492.2nA
-1.28V    6.97uA     55.11uA    37.39nA
-1.23V    6.97uA     13.64uA    3.545nA
-1.181V   6.97uA     3.001uA    935.1pA
-1.132V   6.97uA     611.2nA    652.2pA
-1.083V   6.97uA     120.8nA    600.6pA
-49.22mV  6.97uA     19.89nA    -5.638pA
0V        0A         7.957nA    -10.86pA
3V        0A         0A         0A
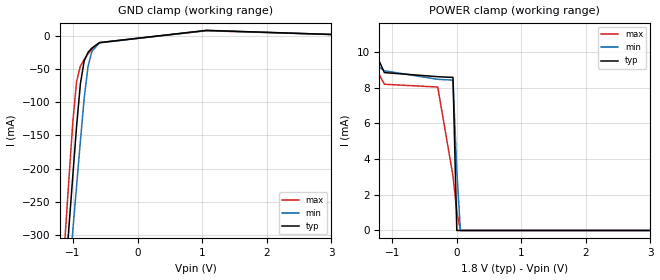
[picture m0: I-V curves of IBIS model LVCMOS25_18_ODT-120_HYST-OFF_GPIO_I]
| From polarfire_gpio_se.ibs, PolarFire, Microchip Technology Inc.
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|   Model LVCMOS25_18_ODT-120_HYST-OFF_GPIO_I
[Model]   LVCMOS25_18_ODT-120_HYST-OFF_GPIO_I
Model_type   Input
Vinl =   0.7
Vinh =   1.7
|   typ   min   max
C_comp_pullup   2.605e-12   2.605e-12   2.76e-12
C_comp_pulldown  2.605e-12   2.605e-12   2.76e-12
[Temperature Range]  25C   100C   -40C
[Voltage Range]  1.8   1.71   1.89
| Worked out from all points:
|   GND clamp passes 1 mA (typ) near -0.08 V on its own axis
|   POWER clamp passes 1 mA (typ) near -0.01 V on its own axis
[GND Clamp]
| Voltage   I(typ)   I(min)   I(max)
-1.8V     -1.241A    -1.209A    -1.296A
-1.122V   -363.5mA   -429.5mA   -300.2mA
-1.063V   -287.2mA   -361.6mA   -214.2mA
-1.004V   -211mA     -293.6mA   -130.3mA
-945mV    -135.7mA   -225.8mA   -68.9mA
-885.9mV  -71.93mA   -158.1mA   -45.72mA
-826.9mV  -37.63mA   -93.43mA   -35.7mA
-767.8mV  -25.04mA   -46.54mA   -27.43mA
-708.7mV  -18.58mA   -23.57mA   -20.22mA
-590.6mV  -10.42mA   -10.74mA   -10.27mA
1.069V    8.031mA    7.904mA    7.516mA
3.6V      0A         0A         0A
[POWER Clamp]
| Voltage   I(typ)   I(min)   I(max)
-1.8V     30.73mA    28mA       34.76mA
-1.713V   24.43mA    23.46mA    27.9mA
-1.595V   17.93mA    17.62mA    20.3mA
-1.477V   13.47mA    13.21mA    14.4mA
-1.358V   10.56mA    10.52mA    10.89mA
-1.24V    9.784mA    9.247mA    8.978mA
-1.122V   8.845mA    8.946mA    8.191mA
-295.3mV  8.613mA    8.466mA    8.034mA
-59.06mV  8.574mA    8.421mA    3.056mA
0V        0A         3.366mA    1.051mA
56.25mV   0A         0A         0A
3.6V      0A         0A         0A
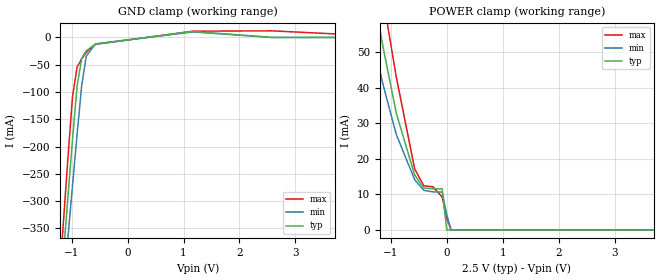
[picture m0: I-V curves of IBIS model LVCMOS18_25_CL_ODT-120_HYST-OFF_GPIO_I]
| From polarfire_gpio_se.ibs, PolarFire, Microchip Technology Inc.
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|   Model LVCMOS18_25_CL_ODT-120_HYST-OFF_GPIO_I
[Model]   LVCMOS18_25_CL_ODT-120_HYST-OFF_GPIO_I
Model_type   Input
Vinl =   0.63
Vinh =   1.17
|   typ   min   max
C_comp_pullup   2.605e-12   2.605e-12   2.76e-12
C_comp_pulldown  2.605e-12   2.605e-12   2.76e-12
[Temperature Range]  25C   100C   -40C
[Voltage Range]  2.5   2.375   2.625
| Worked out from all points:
|   POWER clamp passes 1 mA (typ) near -0.01 V on its own axis
[GND Clamp]
| Voltage   I(typ)   I(min)   I(max)
-2.5V     -2.158A    -2.024A    -2.337A
-1.23V    -504.6mA   -554.8mA   -460.2mA
-1.148V   -398.5mA   -460.5mA   -340.1mA
-1.066V   -292.5mA   -366.2mA   -220.8mA
-984.4mV  -186.9mA   -271.9mA   -108.7mA
-902.3mV  -89.08mA   -177.6mA   -54.3mA
-820.3mV  -38.4mA    -88.33mA   -39.01mA
-738.3mV  -24.38mA   -34.32mA   -27.5mA
-574.2mV  -12.07mA   -11.79mA   -12.62mA
1.172V    10.98mA    10.13mA    11.55mA
2.582V    0A         0A         12.12mA
5V        0A         0A         0A
[POWER Clamp]
| Voltage   I(typ)   I(min)   I(max)
-2.5V     202.8mA    166.5mA    244.2mA
-1.477V   82.79mA    65.41mA    104.1mA
-1.312V   66.98mA    52.91mA    84.58mA
-1.148V   52.21mA    41.44mA    66.22mA
-902.3mV  32.84mA    26.86mA    43.05mA
-574.2mV  15.48mA    14.16mA    17.2mA
-410.2mV  11.8mA     11.16mA    12.42mA
-246.1mV  11.6mA     10.72mA    12.17mA
-82.03mV  11.57mA    10.66mA    9.255mA
0V        0A         4.262mA    3.181mA
78.12mV   0A         0A         0A
5V        0A         0A         0A
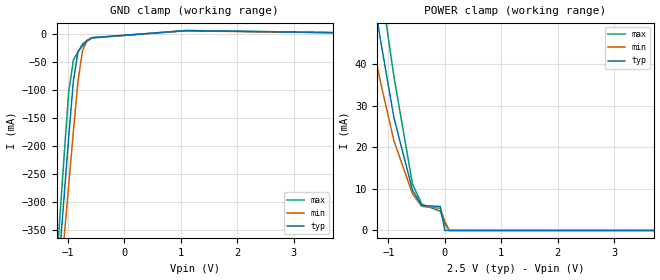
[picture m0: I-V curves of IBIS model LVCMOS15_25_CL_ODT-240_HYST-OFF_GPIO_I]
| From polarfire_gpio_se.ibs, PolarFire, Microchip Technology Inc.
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|   Model LVCMOS15_25_CL_ODT-240_HYST-OFF_GPIO_I
[Model]   LVCMOS15_25_CL_ODT-240_HYST-OFF_GPIO_I
Model_type   Input
Vinl =   0.525
Vinh =   0.975
|   typ   min   max
C_comp_pullup   2.605e-12   2.605e-12   2.76e-12
C_comp_pulldown  2.605e-12   2.605e-12   2.76e-12
[Temperature Range]  25C   100C   -40C
[Voltage Range]  2.5   2.375   2.625
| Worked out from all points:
|   GND clamp passes 1 mA (typ) near -0.11 V on its own axis
|   POWER clamp passes 1 mA (typ) near -0.01 V on its own axis
[GND Clamp]
| Voltage   I(typ)   I(min)   I(max)
-2.5V     -2.156A    -2.021A    -2.335A
-1.23V    -502.5mA   -552.6mA   -458.1mA
-1.148V   -396.3mA   -458.3mA   -337.8mA
-1.066V   -290.3mA   -364mA     -218mA
-984.4mV  -184.4mA   -269.7mA   -104.1mA
-902.3mV  -84.93mA   -175.5mA   -47.27mA
-820.3mV  -32.45mA   -85.19mA   -32.32mA
-738.3mV  -18.55mA   -29.57mA   -21.66mA
-656.2mV  -11.66mA   -12.42mA   -13.22mA
-574.2mV  -7.219mA   -7.126mA   -7.761mA
1.094V    5.396mA    4.977mA    5.68mA
5V        0A         0A         0A
[POWER Clamp]
| Voltage   I(typ)   I(min)   I(max)
-2.5V     196.5mA    160.9mA    237.1mA
-1.477V   76.88mA    60.04mA    97.62mA
-1.312V   61.08mA    47.56mA    78.12mA
-1.23V    53.55mA    41.7mA     68.83mA
-1.148V   46.36mA    36.11mA    59.94mA
-902.3mV  27.07mA    21.54mA    36.97mA
-574.2mV  9.698mA    8.817mA    11.16mA
-410.2mV  5.994mA    5.812mA    6.333mA
-82.03mV  5.785mA    5.329mA    4.628mA
0V        0A         2.13mA     1.591mA
78.12mV   0A         0A         0A
5V        0A         0A         0A
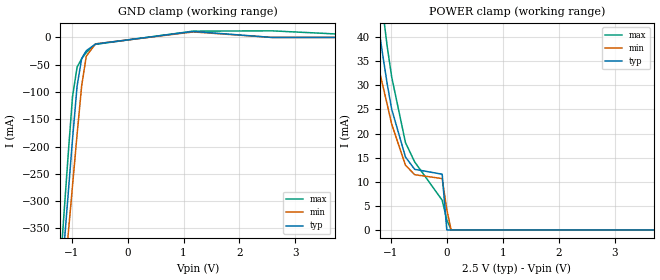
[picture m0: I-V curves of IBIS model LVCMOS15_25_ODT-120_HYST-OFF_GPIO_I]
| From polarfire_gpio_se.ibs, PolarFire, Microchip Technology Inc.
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|   Model LVCMOS15_25_ODT-120_HYST-OFF_GPIO_I
[Model]   LVCMOS15_25_ODT-120_HYST-OFF_GPIO_I
Model_type   Input
Vinl =   0.525
Vinh =   0.975
|   typ   min   max
C_comp_pullup   2.605e-12   2.605e-12   2.76e-12
C_comp_pulldown  2.605e-12   2.605e-12   2.76e-12
[Temperature Range]  25C   100C   -40C
[Voltage Range]  2.5   2.375   2.625
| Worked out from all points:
|   POWER clamp passes 1 mA (typ) near -0.01 V on its own axis
[GND Clamp]
| Voltage   I(typ)   I(min)   I(max)
-2.5V     -2.158A    -2.024A    -2.337A
-1.23V    -504.6mA   -554.8mA   -460.2mA
-1.148V   -398.5mA   -460.5mA   -340.1mA
-1.066V   -292.5mA   -366.2mA   -220.8mA
-984.4mV  -186.9mA   -271.9mA   -108.7mA
-902.3mV  -89.08mA   -177.6mA   -54.3mA
-820.3mV  -38.4mA    -88.33mA   -39.01mA
-738.3mV  -24.38mA   -34.32mA   -27.5mA
-574.2mV  -12.07mA   -11.79mA   -12.62mA
1.172V    10.98mA    10.13mA    11.55mA
2.582V    0A         0A         12.12mA
5V        0A         0A         0A
[POWER Clamp]
| Voltage   I(typ)   I(min)   I(max)
-2.5V     173.5mA    137.4mA    215.3mA
-1.395V   55.91mA    43.12mA    72.24mA
-1.23V    43.1mA     34.18mA    54.72mA
-1.148V   36.58mA    30.19mA    45.93mA
-1.066V   30.39mA    26.09mA    38.17mA
-984.4mV  25.05mA    21.96mA    31.74mA
-738.3mV  15.14mA    13.44mA    18.13mA
-574.2mV  12.58mA    11.47mA    14.13mA
-82.03mV  11.57mA    10.66mA    6.177mA
0V        0A         4.262mA    2.123mA
78.12mV   0A         0A         0A
5V        0A         0A         0A
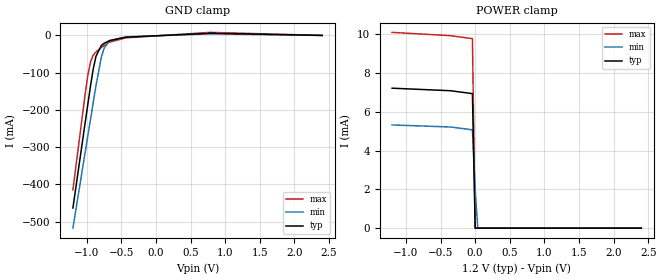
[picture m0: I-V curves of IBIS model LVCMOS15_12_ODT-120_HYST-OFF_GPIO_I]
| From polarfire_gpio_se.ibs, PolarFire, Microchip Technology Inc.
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|   Model LVCMOS15_12_ODT-120_HYST-OFF_GPIO_I
[Model]   LVCMOS15_12_ODT-120_HYST-OFF_GPIO_I
Model_type   Input
Vinl =   0.525
Vinh =   0.975
|   typ   min   max
C_comp_pullup   2.605e-12   2.605e-12   2.76e-12
C_comp_pulldown  2.605e-12   2.605e-12   2.76e-12
[Temperature Range]  25C   100C   -40C
[Voltage Range]  1.2   1.14   1.26
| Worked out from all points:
|   GND clamp passes 1 mA (typ) near -0.09 V on its own axis
|   POWER clamp passes 1 mA (typ) near -0.01 V on its own axis
[GND Clamp]
| Voltage   I(typ)   I(min)   I(max)
-1.2V     -463.6mA   -517.6mA   -414.9mA
-1.024V   -235.7mA   -315mA     -158.6mA
-984.4mV  -185mA     -269.7mA   -107.1mA
-945mV    -134.8mA   -224.5mA   -70.9mA
-905.6mV  -89.33mA   -179.3mA   -52.97mA
-866.2mV  -55.66mA   -134.3mA   -44.34mA
-787.5mV  -26.56mA   -57.15mA   -32.16mA
-748.1mV  -21.12mA   -33.7mA    -26.84mA
-669.4mV  -13.96mA   -13.86mA   -18.02mA
-433.1mV  -4.828mA   -3.774mA   -6.506mA
787.5mV   5.819mA    4.305mA    8.166mA
2.4V      0A         0A         0A
[POWER Clamp]
| Voltage   I(typ)   I(min)   I(max)
-1.2V     7.22mA     5.324mA    10.1mA
-354.4mV  7.089mA    5.217mA    9.929mA
-39.38mV  6.94mA     5.072mA    9.777mA
0V        0A         2.023mA    0A
37.5mV    0A         0A         0A
2.4V      0A         0A         0A
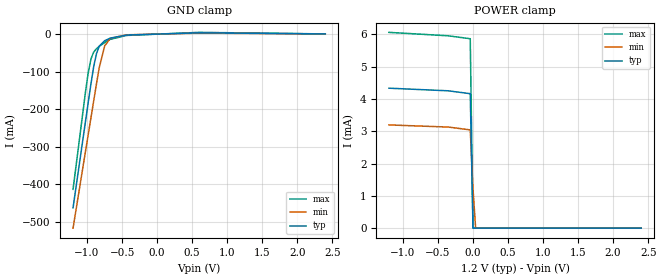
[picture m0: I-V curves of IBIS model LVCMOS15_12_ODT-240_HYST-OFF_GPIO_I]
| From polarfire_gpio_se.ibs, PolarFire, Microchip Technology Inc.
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|   Model LVCMOS15_12_ODT-240_HYST-OFF_GPIO_I
[Model]   LVCMOS15_12_ODT-240_HYST-OFF_GPIO_I
Model_type   Input
Vinl =   0.525
Vinh =   0.975
|   typ   min   max
C_comp_pullup   2.605e-12   2.605e-12   2.76e-12
C_comp_pulldown  2.605e-12   2.605e-12   2.76e-12
[Temperature Range]  25C   100C   -40C
[Voltage Range]  1.2   1.14   1.26
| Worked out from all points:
|   GND clamp passes 1 mA (typ) near -0.15 V on its own axis
|   POWER clamp passes 1 mA (typ) near -0.01 V on its own axis
[GND Clamp]
| Voltage   I(typ)   I(min)   I(max)
-1.2V     -462.5mA   -516.6mA   -413.4mA
-1.024V   -234.5mA   -314mA     -156.3mA
-984.4mV  -183.7mA   -268.8mA   -104.1mA
-945mV    -133.2mA   -223.5mA   -66.83mA
-905.6mV  -87.18mA   -178.3mA   -48.22mA
-866.2mV  -52.86mA   -133.3mA   -39.49mA
-826.9mV  -32.87mA   -90.28mA   -33.27mA
-748.1mV  -17.99mA   -31.72mA   -22.84mA
-669.4mV  -11.19mA   -11.74mA   -14.38mA
-433.1mV  -2.952mA   -2.335mA   -3.972mA
600mV     2.945mA    2.18mA     4.136mA
2.4V      0A         0A         0A
[POWER Clamp]
| Voltage   I(typ)   I(min)   I(max)
-1.2V     4.335mA    3.197mA    6.064mA
-354.4mV  4.254mA    3.131mA    5.958mA
-39.38mV  4.165mA    3.044mA    5.867mA
0V        0A         1.214mA    0A
37.5mV    0A         0A         0A
2.4V      0A         0A         0A
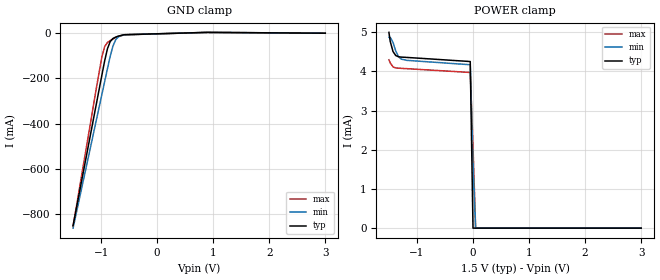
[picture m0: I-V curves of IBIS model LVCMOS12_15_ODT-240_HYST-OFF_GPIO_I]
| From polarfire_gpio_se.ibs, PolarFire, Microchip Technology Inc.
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|   Model LVCMOS12_15_ODT-240_HYST-OFF_GPIO_I
[Model]   LVCMOS12_15_ODT-240_HYST-OFF_GPIO_I
Model_type   Input
Vinl =   0.42
Vinh =   0.78
|   typ   min   max
C_comp_pullup   2.605e-12   2.605e-12   2.76e-12
C_comp_pulldown  2.605e-12   2.605e-12   2.76e-12
[Temperature Range]  25C   100C   -40C
[Voltage Range]  1.5   1.425   1.575
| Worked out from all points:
|   GND clamp passes 1 mA (typ) near -0.15 V on its own axis
|   POWER clamp passes 1 mA (typ) near -0.01 V on its own axis
[GND Clamp]
| Voltage   I(typ)   I(min)   I(max)
-1.5V     -850.9mA   -861.9mA   -853.5mA
-1.083V   -310.9mA   -382.4mA   -241.1mA
-984.4mV  -183.7mA   -269.3mA   -102.7mA
-935.2mV  -121mA     -212.7mA   -58.54mA
-885.9mV  -68.26mA   -156.3mA   -40.85mA
-836.7mV  -36.64mA   -101.1mA   -32.27mA
-787.5mV  -23.23mA   -56.36mA   -25.38mA
-738.3mV  -16.97mA   -28.59mA   -19.38mA
-689.1mV  -12.65mA   -15.6mA    -14.3mA
-590.6mV  -6.685mA   -6.9mA     -6.933mA
890.6mV   3.728mA    3.673mA    3.488mA
3V        0A         0A         0A
[POWER Clamp]
| Voltage   I(typ)   I(min)   I(max)
-1.5V     4.995mA    4.868mA    4.294mA
-1.477V   4.764mA    4.868mA    4.217mA
-1.427V   4.505mA    4.737mA    4.113mA
-1.378V   4.403mA    4.517mA    4.088mA
-1.329V   4.373mA    4.375mA    4.081mA
-1.28V    4.364mA    4.313mA    4.077mA
-1.181V   4.356mA    4.281mA    4.069mA
-49.22mV  4.251mA    4.169mA    3.972mA
0V        0A         1.666mA    2.079mA
46.88mV   0A         0A         0A
3V        0A         0A         0A
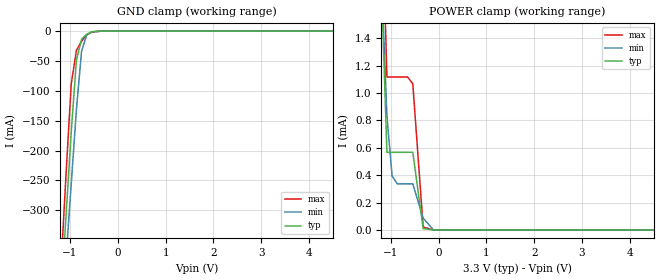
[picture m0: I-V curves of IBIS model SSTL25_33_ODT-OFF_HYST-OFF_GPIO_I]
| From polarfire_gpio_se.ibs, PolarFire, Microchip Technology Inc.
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|   Model SSTL25_33_ODT-OFF_HYST-OFF_GPIO_I
[Model]   SSTL25_33_ODT-OFF_HYST-OFF_GPIO_I
Model_type   Input
Vinl =   1.1
Vinh =   1.4
|   typ   min   max
C_comp_pullup   2.605e-12   2.605e-12   2.76e-12
C_comp_pulldown  2.605e-12   2.605e-12   2.76e-12
[Temperature Range]  25C   100C   -40C
[Voltage Range]  3.3   3.135   3.465
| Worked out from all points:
|   GND clamp passes 1 mA (typ) near -0.53 V on its own axis
|   POWER clamp passes 1 mA (typ) near -1.12 V on its own axis
[GND Clamp]
| Voltage   I(typ)   I(min)   I(max)
-3.3V     -3.213A    -2.957A    -3.541A
-1.191V   -449.3mA   -505mA     -398.4mA
-1.083V   -309.2mA   -380.6mA   -239.7mA
-974.5mV  -169.2mA   -256.1mA   -88.53mA
-866.2mV  -48.93mA   -131.7mA   -32.27mA
-758mV    -13.75mA   -33.64mA   -16.94mA
-649.7mV  -5.158mA   -6.075mA   -6.593mA
-541.4mV  -1.115mA   -1.146mA   -1.479mA
-324.8mV  -2.612uA   -7.214uA   -1.709uA
6.6V      0A         0A         0A
[POWER Clamp]
| Voltage   I(typ)   I(min)   I(max)
-3.3V     119.9mA    83.01mA    164.1mA
-1.191V   1.725mA    1.786mA    2.468mA
-1.083V   567.5uA    833.7uA    1.118mA
-974.5mV  567.5uA    394.4uA    1.118mA
-866.2mV  567.5uA    337.2uA    1.118mA
-649.7mV  567.5uA    337.2uA    1.118mA
-541.4mV  567.5uA    337.2uA    1.068mA
-324.8mV  9.786uA    86.45uA    22.2uA
-108.3mV  2.693nA    113.2nA    17.61nA
6.6V      0A         0A         0A
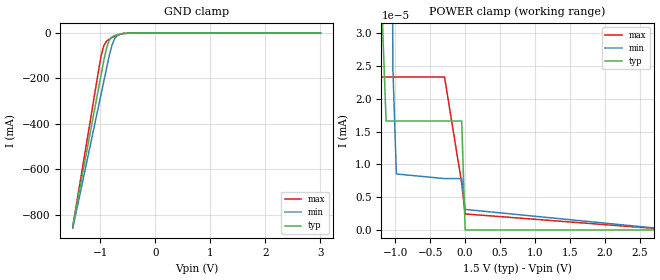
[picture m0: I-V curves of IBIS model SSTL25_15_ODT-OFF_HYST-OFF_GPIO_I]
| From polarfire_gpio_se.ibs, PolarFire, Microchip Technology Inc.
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|   Model SSTL25_15_ODT-OFF_HYST-OFF_GPIO_I
[Model]   SSTL25_15_ODT-OFF_HYST-OFF_GPIO_I
Model_type   Input
Vinl =   1.1
Vinh =   1.4
|   typ   min   max
C_comp_pullup   2.605e-12   2.605e-12   2.76e-12
C_comp_pulldown  2.605e-12   2.605e-12   2.76e-12
[Temperature Range]  25C   100C   -40C
[Voltage Range]  1.5   1.425   1.575
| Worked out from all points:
|   GND clamp passes 1 mA (typ) near -0.53 V on its own axis
[GND Clamp]
| Voltage   I(typ)   I(min)   I(max)
-1.5V     -849.3mA   -860.1mA   -852.3mA
-1.034V   -245.6mA   -324mA     -167.7mA
-984.4mV  -181.9mA   -267.4mA   -99.94mA
-935.2mV  -118.6mA   -210.9mA   -54.55mA
-885.9mV  -64.84mA   -154.3mA   -36.15mA
-836.7mV  -32mA      -98.64mA   -27.47mA
-787.5mV  -17.96mA   -52.99mA   -20.61mA
-738.3mV  -11.65mA   -24.31mA   -14.68mA
-689.1mV  -7.607mA   -10.89mA   -9.751mA
-590.6mV  -2.494mA   -2.583mA   -3.194mA
-393.7mV  -25.22uA   -44.16uA   -27.71uA
3V        0A         0A         0A
[POWER Clamp]
| Voltage   I(typ)   I(min)   I(max)
-1.5V     355.1uA    199.5uA    435uA
-1.28V    1.768uA    55.11uA    45.78nA
-1.23V    234.6nA    13.64uA    23.33nA
-1.181V   30.82nA    3.001uA    23.33nA
-1.132V   16.62nA    612.9nA    23.33nA
-1.083V   16.62nA    122.1nA    23.33nA
-1.034V   16.62nA    24.45nA    23.33nA
-984.4mV  16.62nA    8.539nA    23.33nA
-295.3mV  16.62nA    7.834nA    23.33nA
-49.22mV  16.62nA    7.834nA    7.111nA
0V        0A         3.134nA    2.444nA
3V        0A         0A         0A
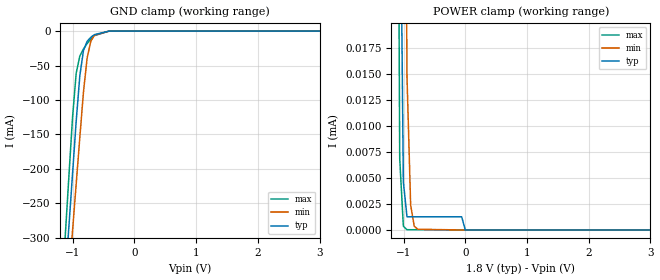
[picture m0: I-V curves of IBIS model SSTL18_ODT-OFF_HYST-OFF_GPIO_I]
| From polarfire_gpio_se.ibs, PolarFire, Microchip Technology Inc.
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|   Model SSTL18_ODT-OFF_HYST-OFF_GPIO_I
[Model]   SSTL18_ODT-OFF_HYST-OFF_GPIO_I
Model_type   Input
Vinl =   0.775
Vinh =   1.025
|   typ   min   max
C_comp_pullup   2.605e-12   2.605e-12   2.76e-12
C_comp_pulldown  2.605e-12   2.605e-12   2.76e-12
[Temperature Range]  25C   100C   -40C
[Voltage Range]  1.8   1.71   1.89
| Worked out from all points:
|   GND clamp passes 1 mA (typ) near -0.53 V on its own axis
[GND Clamp]
| Voltage   I(typ)   I(min)   I(max)
-1.8V     -1.238A    -1.206A    -1.294A
-1.122V   -360.2mA   -425.9mA   -297.3mA
-1.063V   -283.8mA   -358mA     -210.9mA
-1.004V   -207.4mA   -290mA     -125.4mA
-945mV    -131.1mA   -222.2mA   -61.15mA
-885.9mV  -64.84mA   -154.3mA   -36.15mA
-826.9mV  -28.05mA   -88.35mA   -26.02mA
-767.8mV  -14.97mA   -39.36mA   -18.12mA
-708.7mV  -9.067mA   -14.9mA    -11.6mA
-649.7mV  -5.157mA   -6.074mA   -6.592mA
-413.4mV  -46.15uA   -72.15uA   -56.26uA
3.6V      0A         0A         0A
[POWER Clamp]
| Voltage   I(typ)   I(min)   I(max)
-1.8V     692.2uA    1.143mA    803.1uA
-1.122V   247.5uA    167.5uA    79.37uA
-1.063V   40.35uA    140.6uA    6.852uA
-1.004V   4.6uA      75.51uA    361.6nA
-945mV    1.264uA    14.68uA    26.34nA
-885.9mV  1.264uA    2.392uA    22.42nA
-826.9mV  1.264uA    351.3nA    22.42nA
-767.8mV  1.264uA    67.95nA    22.42nA
-59.06mV  1.264uA    803.4pA    4.88nA
0V        0A         321.4pA    1.677nA
3.6V      0A         0A         0A
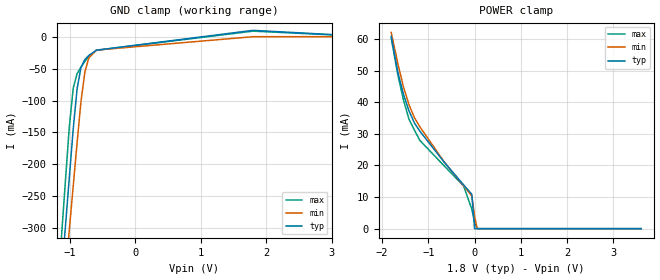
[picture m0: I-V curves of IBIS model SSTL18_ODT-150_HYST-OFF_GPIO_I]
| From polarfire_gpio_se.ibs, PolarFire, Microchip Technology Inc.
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|   Model SSTL18_ODT-150_HYST-OFF_GPIO_I
[Model]   SSTL18_ODT-150_HYST-OFF_GPIO_I
Model_type   Input
Vinl =   0.775
Vinh =   1.025
|   typ   min   max
C_comp_pullup   2.605e-12   2.605e-12   2.76e-12
C_comp_pulldown  2.605e-12   2.605e-12   2.76e-12
[Temperature Range]  25C   100C   -40C
[Voltage Range]  1.8   1.71   1.89
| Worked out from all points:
|   POWER clamp passes 1 mA (typ) near -0.01 V on its own axis
[GND Clamp]
| Voltage   I(typ)   I(min)   I(max)
-1.8V     -1.25A     -1.217A    -1.304A
-1.122V   -372.1mA   -437.5mA   -309.8mA
-1.063V   -295.8mA   -369.5mA   -223.9mA
-1.004V   -219.6mA   -301.6mA   -140.3mA
-945mV    -144.5mA   -233.7mA   -80.46mA
-885.9mV  -81.59mA   -166.1mA   -57.94mA
-826.9mV  -48.24mA   -101.9mA   -47.42mA
-767.8mV  -35.93mA   -55.86mA   -38.77mA
-708.7mV  -29.44mA   -33.6mA    -31.41mA
-590.6mV  -21.08mA   -20.93mA   -21.25mA
1.8V      9.955mA    0A         8.699mA
3.6V      0A         0A         0A
[POWER Clamp]
| Voltage   I(typ)   I(min)   I(max)
-1.8V     60.86mA    62.11mA    60.33mA
-1.654V   49.31mA    52.06mA    48.45mA
-1.536V   42.52mA    44.87mA    40.74mA
-1.417V   37.28mA    39.25mA    34.66mA
-1.299V   33.46mA    35.13mA    31.18mA
-1.181V   30.84mA    32.23mA    27.91mA
-649.7mV  20.92mA    21mA       19.77mA
-236.2mV  13.85mA    13.55mA    13.51mA
-59.06mV  10.88mA    10.38mA    6.154mA
0V        0A         3.984mA    2.116mA
56.25mV   0A         0A         0A
3.6V      0A         0A         0A
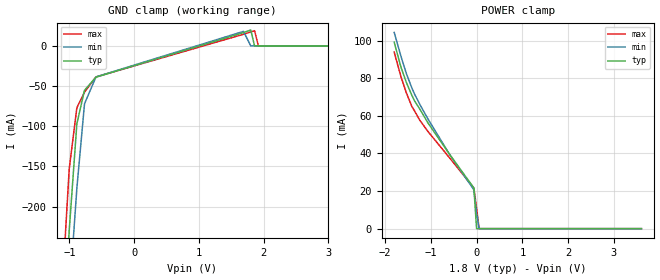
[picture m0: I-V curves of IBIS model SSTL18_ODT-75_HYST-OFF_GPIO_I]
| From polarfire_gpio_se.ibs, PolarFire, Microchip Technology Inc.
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|   Model SSTL18_ODT-75_HYST-OFF_GPIO_I
[Model]   SSTL18_ODT-75_HYST-OFF_GPIO_I
Model_type   Input
Vinl =   0.775
Vinh =   1.025
|   typ   min   max
C_comp_pullup   2.605e-12   2.605e-12   2.76e-12
C_comp_pulldown  2.605e-12   2.605e-12   2.76e-12
[Temperature Range]  25C   100C   -40C
[Voltage Range]  1.8   1.71   1.89
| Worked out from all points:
|   POWER clamp passes 1 mA (typ) near -0.00 V on its own axis
[GND Clamp]
| Voltage   I(typ)   I(min)   I(max)
-1.8V     -1.26A     -1.229A    -1.314A
-1.122V   -382.2mA   -448.7mA   -320.1mA
-1.063V   -305.9mA   -380.7mA   -234.6mA
-1.004V   -229.8mA   -312.8mA   -153.2mA
-885.9mV  -96.92mA   -177.3mA   -77.03mA
-767.8mV  -55.27mA   -72.09mA   -57.55mA
-590.6mV  -38.92mA   -38.58mA   -38.65mA
1.688V    16.54mA    18.07mA    14.49mA
1.8V      19.81mA    0A         17.35mA
1.859V    0A         0A         18.96mA
1.918V    0A         0A         0A
3.6V      0A         0A         0A
[POWER Clamp]
| Voltage   I(typ)   I(min)   I(max)
-1.8V     99.16mA    104.4mA    93.9mA
-1.654V   86.03mA    91.79mA    81.02mA
-1.536V   77.88mA    82.61mA    72.33mA
-1.417V   71.08mA    74.98mA    65.17mA
-1.358V   68.1mA     71.73mA    62.74mA
-1.24V    63.57mA    66.08mA    57.64mA
-1.063V   56.26mA    58.38mA    51.71mA
-590.6mV  39.55mA    39.51mA    37.66mA
-59.06mV  21.65mA    20.66mA    21.57mA
0V        0A         7.931mA    10.82mA
56.25mV   0A         0A         0A
3.6V      0A         0A         0A
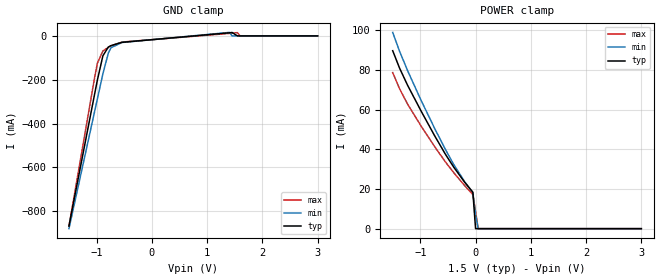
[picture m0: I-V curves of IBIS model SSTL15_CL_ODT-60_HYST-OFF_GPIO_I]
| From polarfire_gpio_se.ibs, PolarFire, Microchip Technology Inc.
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|   Model SSTL15_CL_ODT-60_HYST-OFF_GPIO_I
[Model]   SSTL15_CL_ODT-60_HYST-OFF_GPIO_I
Model_type   Input
Vinl =   0.65
Vinh =   0.85
|   typ   min   max
C_comp_pullup   2.605e-12   2.605e-12   2.76e-12
C_comp_pulldown  2.605e-12   2.605e-12   2.76e-12
[Temperature Range]  25C   100C   -40C
[Voltage Range]  1.5   1.425   1.575
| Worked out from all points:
|   POWER clamp passes 1 mA (typ) near -0.00 V on its own axis
[GND Clamp]
| Voltage   I(typ)   I(min)   I(max)
-1.5V     -866.8mA   -879.2mA   -868.8mA
-1.034V   -263.4mA   -342.7mA   -187.7mA
-984.4mV  -200.3mA   -286.1mA   -124.1mA
-885.9mV  -90.87mA   -173.2mA   -68.76mA
-787.5mV  -50.98mA   -78.65mA   -52.22mA
-738.3mV  -44.39mA   -54.01mA   -45.45mA
-541.4mV  -29.47mA   -30.28mA   -28.25mA
1.406V    14.12mA    15.89mA    11.38mA
1.453V    15.44mA    0A         12.52mA
1.549V    0A         0A         15.04mA
1.598V    0A         0A         0A
3V        0A         0A         0A
[POWER Clamp]
| Voltage   I(typ)   I(min)   I(max)
-1.5V     89.61mA    98.84mA    78.61mA
-1.378V   80.98mA    89.49mA    70.59mA
-1.23V    72.18mA    79.54mA    62.69mA
-984.4mV  59.13mA    64.49mA    51.57mA
-738.3mV  46.65mA    50.34mA    41.2mA
-541.4mV  37.27mA    39.64mA    33.44mA
-393.7mV  30.9mA     32.22mA    28.14mA
-196.9mV  23.35mA    23.62mA    21.65mA
-49.22mV  18.36mA    18.14mA    17.18mA
0V        0A         6.966mA    8.603mA
46.88mV   0A         0A         0A
3V        0A         0A         0A
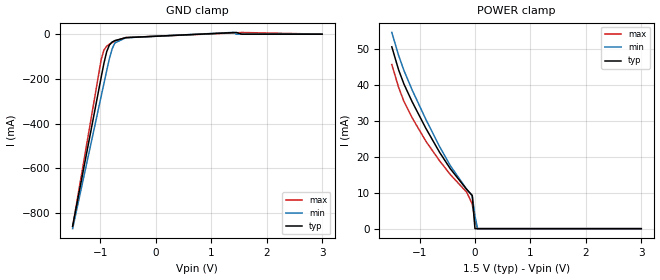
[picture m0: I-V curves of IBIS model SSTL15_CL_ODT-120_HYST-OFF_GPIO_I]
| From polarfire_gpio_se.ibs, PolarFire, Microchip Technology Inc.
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|   Model SSTL15_CL_ODT-120_HYST-OFF_GPIO_I
[Model]   SSTL15_CL_ODT-120_HYST-OFF_GPIO_I
Model_type   Input
Vinl =   0.65
Vinh =   0.85
|   typ   min   max
C_comp_pullup   2.605e-12   2.605e-12   2.76e-12
C_comp_pulldown  2.605e-12   2.605e-12   2.76e-12
[Temperature Range]  25C   100C   -40C
[Voltage Range]  1.5   1.425   1.575
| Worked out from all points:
|   POWER clamp passes 1 mA (typ) near -0.01 V on its own axis
[GND Clamp]
| Voltage   I(typ)   I(min)   I(max)
-1.5V     -858.6mA   -869.6mA   -860.4mA
-984.4mV  -192mA     -276.8mA   -113.1mA
-935.2mV  -129.9mA   -220.2mA   -70.84mA
-885.9mV  -78.61mA   -163.9mA   -53.8mA
-836.7mV  -48.33mA   -109.4mA   -44.83mA
-787.5mV  -35.26mA   -65.87mA   -37.39mA
-738.3mV  -28.71mA   -39.34mA   -30.84mA
-541.4mV  -15.52mA   -15.94mA   -15.05mA
1.406V    7.094mA    7.979mA    5.704mA
1.453V    7.758mA    0A         6.274mA
1.549V    0A         0A         7.54mA
3V        0A         0A         0A
[POWER Clamp]
| Voltage   I(typ)   I(min)   I(max)
-1.5V     50.5mA     54.51mA    45.58mA
-1.378V   44.13mA    48.14mA    39.26mA
-1.28V    40.11mA    43.88mA    35.29mA
-1.132V   35.2mA     38.48mA    30.76mA
-885.9mV  27.87mA    30.35mA    24.3mA
-639.8mV  21.24mA    22.84mA    18.88mA
-443mV    16.6mA     17.46mA    14.99mA
-147.7mV  10.87mA    10.92mA    10.1mA
-49.22mV  9.228mA    9.114mA    6.825mA
0V        0A         3.499mA    2.346mA
46.88mV   0A         0A         0A
3V        0A         0A         0A
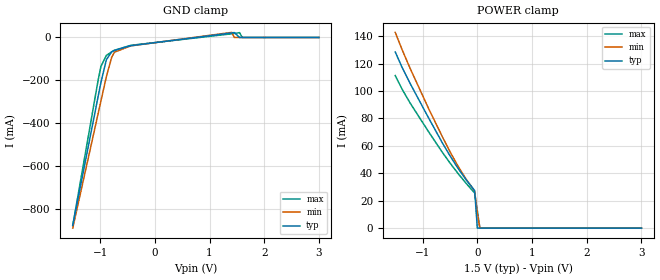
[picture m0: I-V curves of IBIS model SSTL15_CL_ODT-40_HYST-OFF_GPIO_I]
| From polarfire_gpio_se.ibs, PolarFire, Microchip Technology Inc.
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|   Model SSTL15_CL_ODT-40_HYST-OFF_GPIO_I
[Model]   SSTL15_CL_ODT-40_HYST-OFF_GPIO_I
Model_type   Input
Vinl =   0.65
Vinh =   0.85
|   typ   min   max
C_comp_pullup   2.605e-12   2.605e-12   2.76e-12
C_comp_pulldown  2.605e-12   2.605e-12   2.76e-12
[Temperature Range]  25C   100C   -40C
[Voltage Range]  1.5   1.425   1.575
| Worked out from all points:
|   POWER clamp passes 1 mA (typ) near -0.00 V on its own axis
[GND Clamp]
| Voltage   I(typ)   I(min)   I(max)
-1.5V     -875.5mA   -888.5mA   -876mA
-1.034V   -271.9mA   -351.8mA   -195.6mA
-984.4mV  -209.1mA   -295.1mA   -134.7mA
-885.9mV  -103.8mA   -182.5mA   -83.59mA
-787.5mV  -66.79mA   -91.63mA   -66.89mA
-738.3mV  -60.07mA   -68.76mA   -59.92mA
-443mV    -38.5mA    -39.39mA   -36.7mA
1.406V    21.1mA     23.72mA    17mA
1.453V    23.07mA    0A         18.69mA
1.549V    0A         0A         22.44mA
1.598V    0A         0A         0A
3V        0A         0A         0A
[POWER Clamp]
| Voltage   I(typ)   I(min)   I(max)
-1.5V     128.4mA    142.7mA    111.2mA
-1.378V   117.4mA    130.4mA    101.5mA
-1.23V    105.6mA    116.6mA    91.29mA
-885.9mV  79.98mA    86.78mA    69.95mA
-639.8mV  62.21mA    66.68mA    55.31mA
-492.2mV  52.25mA    55.18mA    47.09mA
-344.5mV  43.13mA    44.62mA    39.44mA
-196.9mV  34.85mA    35.24mA    32.29mA
-49.22mV  27.41mA    27.07mA    25.62mA
0V        0A         10.4mA     12.84mA
46.88mV   0A         0A         0A
3V        0A         0A         0A
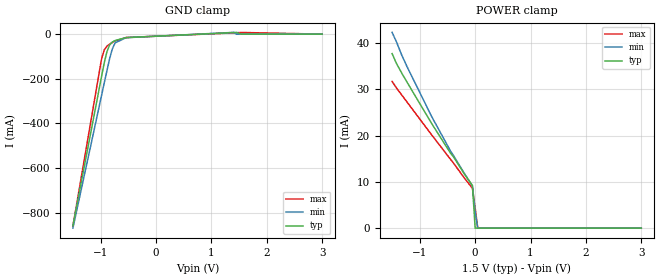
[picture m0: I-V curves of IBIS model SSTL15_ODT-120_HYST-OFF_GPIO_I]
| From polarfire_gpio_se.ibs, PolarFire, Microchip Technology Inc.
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|   Model SSTL15_ODT-120_HYST-OFF_GPIO_I
[Model]   SSTL15_ODT-120_HYST-OFF_GPIO_I
Model_type   Input
Vinl =   0.65
Vinh =   0.85
|   typ   min   max
C_comp_pullup   2.605e-12   2.605e-12   2.76e-12
C_comp_pulldown  2.605e-12   2.605e-12   2.76e-12
[Temperature Range]  25C   100C   -40C
[Voltage Range]  1.5   1.425   1.575
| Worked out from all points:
|   POWER clamp passes 1 mA (typ) near -0.01 V on its own axis
[GND Clamp]
| Voltage   I(typ)   I(min)   I(max)
-1.5V     -858.6mA   -869.6mA   -860.4mA
-984.4mV  -192mA     -276.8mA   -113.1mA
-935.2mV  -129.9mA   -220.2mA   -70.84mA
-885.9mV  -78.61mA   -163.9mA   -53.8mA
-836.7mV  -48.33mA   -109.4mA   -44.83mA
-787.5mV  -35.26mA   -65.87mA   -37.39mA
-738.3mV  -28.71mA   -39.34mA   -30.84mA
-541.4mV  -15.52mA   -15.94mA   -15.05mA
1.406V    7.094mA    7.979mA    5.704mA
1.453V    7.758mA    0A         6.274mA
1.549V    0A         0A         7.54mA
3V        0A         0A         0A
[POWER Clamp]
| Voltage   I(typ)   I(min)   I(max)
-1.5V     37.76mA    42.36mA    31.74mA
-1.427V   35.78mA    40.46mA    30.43mA
-1.329V   33.61mA    37.53mA    28.85mA
-1.23V    31.58mA    34.94mA    27.28mA
-787.5mV  22.68mA    24.19mA    20.21mA
-443mV    16.19mA    16.65mA    14.86mA
-393.7mV  15.47mA    15.74mA    14.12mA
-196.9mV  11.74mA    11.88mA    10.86mA
-49.22mV  9.228mA    9.114mA    8.615mA
0V        0A         3.499mA    4.315mA
46.88mV   0A         0A         0A
3V        0A         0A         0A
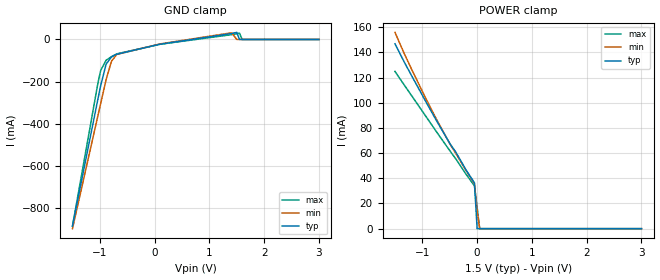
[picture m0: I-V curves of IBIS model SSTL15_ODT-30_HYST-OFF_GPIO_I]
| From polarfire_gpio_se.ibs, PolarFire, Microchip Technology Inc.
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|   Model SSTL15_ODT-30_HYST-OFF_GPIO_I
[Model]   SSTL15_ODT-30_HYST-OFF_GPIO_I
Model_type   Input
Vinl =   0.65
Vinh =   0.85
|   typ   min   max
C_comp_pullup   2.605e-12   2.605e-12   2.76e-12
C_comp_pulldown  2.605e-12   2.605e-12   2.76e-12
[Temperature Range]  25C   100C   -40C
[Voltage Range]  1.5   1.425   1.575
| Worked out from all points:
|   POWER clamp passes 1 mA (typ) near -0.00 V on its own axis
[GND Clamp]
| Voltage   I(typ)   I(min)   I(max)
-1.5V     -884.2mA   -896.5mA   -884.4mA
-1.034V   -280.5mA   -359.4mA   -204.8mA
-984.4mV  -218.2mA   -302.7mA   -146.4mA
-885.9mV  -117.2mA   -190.5mA   -98.67mA
-787.5mV  -82.55mA   -103.1mA   -81.73mA
-689.1mV  -70.02mA   -71mA      -68.12mA
93.75mV   -22.88mA   -21.5mA    -22.98mA
1.406V    28.04mA    31.62mA    22.6mA
1.5V      33.38mA    0A         27.21mA
1.549V    0A         0A         29.83mA
1.598V    0A         0A         0A
3V        0A         0A         0A
[POWER Clamp]
| Voltage   I(typ)   I(min)   I(max)
-1.5V     146.8mA    155.9mA    124.9mA
-1.329V   132.2mA    138.9mA    114mA
-1.181V   120.3mA    125.2mA    104.7mA
-935.2mV  100.8mA    103.3mA    89.16mA
-738.3mV  85.52mA    86.55mA    76.74mA
-492.2mV  67.21mA    66.95mA    61.53mA
-393.7mV  61.14mA    60.12mA    55.69mA
-196.9mV  46.26mA    45.8mA     42.91mA
-49.22mV  36.41mA    35.75mA    34.06mA
0V        0A         13.77mA    17.06mA
46.88mV   0A         0A         0A
3V        0A         0A         0A
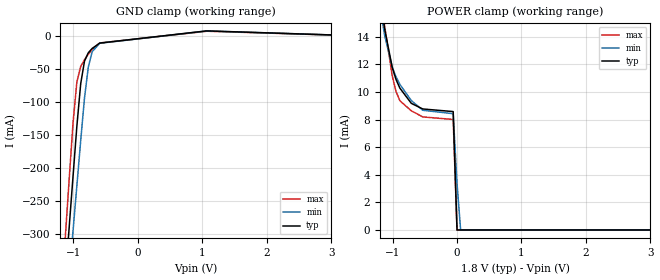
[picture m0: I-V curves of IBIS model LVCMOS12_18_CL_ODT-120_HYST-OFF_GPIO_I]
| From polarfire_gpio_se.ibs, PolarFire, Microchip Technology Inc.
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|   LVCMOS12_18_CL_ODT-120_HYST-OFF_GPIO_I
[Model]   LVCMOS12_18_CL_ODT-120_HYST-OFF_GPIO_I
Model_type  Input
Vinl =   0.42
Vinh =   0.78
|   typ   min   max
C_comp_pullup   2.605e-12   2.605e-12   2.76e-12
C_comp_pulldown  2.605e-12   2.605e-12   2.76e-12
[Temperature Range]   25   100   -40
[Voltage Range]   1.8   1.71   1.89
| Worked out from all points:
|   GND clamp passes 1 mA (typ) near -0.08 V on its own axis
|   POWER clamp passes 1 mA (typ) near -0.01 V on its own axis
[GND Clamp]
| Voltage   I(typ)   I(min)   I(max)
-1.8V     -1.241A    -1.209A    -1.296A
-1.122V   -363.5mA   -429.5mA   -300.2mA
-1.063V   -287.2mA   -361.6mA   -214.2mA
-1.004V   -211mA     -293.6mA   -130.3mA
-945mV    -135.7mA   -225.8mA   -68.9mA
-885.9mV  -71.93mA   -158.1mA   -45.72mA
-826.9mV  -37.63mA   -93.43mA   -35.7mA
-767.8mV  -25.04mA   -46.54mA   -27.43mA
-708.7mV  -18.58mA   -23.57mA   -20.22mA
-590.6mV  -10.42mA   -10.74mA   -10.27mA
1.069V    8.031mA    7.904mA    7.516mA
3.6V      0A         0A         0A
[POWER Clamp]
| Voltage   I(typ)   I(min)   I(max)
-1.8V     54.22mA    44.08mA    68.19mA
-1.181V   16.58mA    15.75mA    17.25mA
-1.122V   14.54mA    14.08mA    14.75mA
-1.004V   11.76mA    11.79mA    11.14mA
-945mV    10.89mA    11.08mA    10.02mA
-885.9mV  10.27mA    10.54mA    9.355mA
-708.7mV  9.171mA    9.373mA    8.631mA
-531.6mV  8.764mA    8.671mA    8.187mA
-59.06mV  8.574mA    8.421mA    8.002mA
0V        0A         3.366mA    0A
56.25mV   0A         0A         0A
3.6V      0A         0A         0A
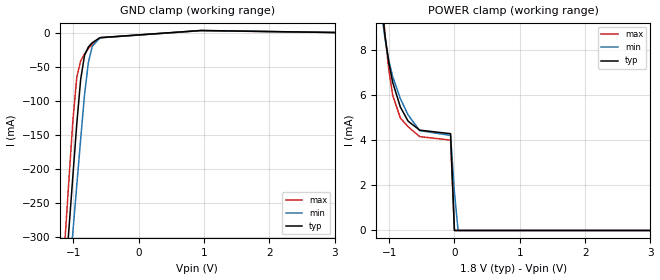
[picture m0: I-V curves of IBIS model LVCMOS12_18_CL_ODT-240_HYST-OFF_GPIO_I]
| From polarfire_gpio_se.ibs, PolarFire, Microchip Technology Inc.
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|   LVCMOS12_18_CL_ODT-240_HYST-OFF_GPIO_I
[Model]   LVCMOS12_18_CL_ODT-240_HYST-OFF_GPIO_I
Model_type  Input
Vinl =   0.42
Vinh =   0.78
|   typ   min   max
C_comp_pullup   2.605e-12   2.605e-12   2.76e-12
C_comp_pulldown  2.605e-12   2.605e-12   2.76e-12
[Temperature Range]   25   100   -40
[Voltage Range]   1.8   1.71   1.89
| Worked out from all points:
|   GND clamp passes 1 mA (typ) near -0.15 V on its own axis
|   POWER clamp passes 1 mA (typ) near -0.01 V on its own axis
[GND Clamp]
| Voltage   I(typ)   I(min)   I(max)
-1.8V     -1.24A     -1.207A    -1.295A
-1.122V   -361.8mA   -427.7mA   -298.7mA
-1.063V   -285.4mA   -359.8mA   -212.4mA
-1.004V   -209.1mA   -291.9mA   -127.8mA
-945mV    -133.2mA   -224mA     -64.89mA
-885.9mV  -68.26mA   -156.3mA   -40.85mA
-826.9mV  -32.87mA   -90.98mA   -30.81mA
-767.8mV  -20.31mA   -43.12mA   -22.87mA
-708.7mV  -14.25mA   -19.51mA   -16.23mA
-590.6mV  -6.685mA   -6.9mA     -6.933mA
956.3mV   3.852mA    3.792mA    3.605mA
3.6V      0A         0A         0A
[POWER Clamp]
| Voltage   I(typ)   I(min)   I(max)
-1.8V     49.82mA    39.81mA    63.88mA
-1.122V   10.21mA    9.818mA    10.73mA
-1.063V   8.628mA    8.495mA    8.698mA
-1.004V   7.429mA    7.521mA    7.108mA
-945mV    6.559mA    6.811mA    5.986mA
-826.9mV  5.463mA    5.837mA    4.976mA
-708.7mV  4.841mA    5.117mA    4.595mA
-531.6mV  4.444mA    4.423mA    4.158mA
-59.06mV  4.287mA    4.21mA     4.001mA
0V        0A         1.683mA    0A
56.25mV   0A         0A         0A
3.6V      0A         0A         0A
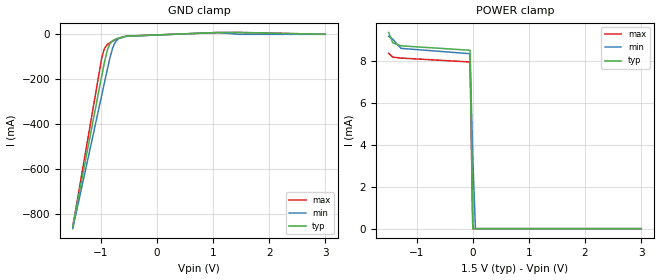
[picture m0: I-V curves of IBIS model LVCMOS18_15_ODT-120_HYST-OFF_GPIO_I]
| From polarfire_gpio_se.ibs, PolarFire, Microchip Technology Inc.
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|   LVCMOS18_15_ODT-120_HYST-OFF_GPIO_I
[Model]   LVCMOS18_15_ODT-120_HYST-OFF_GPIO_I
Model_type  Input
Vinl =   0.63
Vinh =   1.17
|   typ   min   max
C_comp_pullup   2.605e-12   2.605e-12   2.76e-12
C_comp_pulldown  2.605e-12   2.605e-12   2.76e-12
[Temperature Range]   25   100   -40
[Voltage Range]   1.5   1.425   1.575
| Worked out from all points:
|   GND clamp passes 1 mA (typ) near -0.08 V on its own axis
|   POWER clamp passes 1 mA (typ) near -0.01 V on its own axis
[GND Clamp]
| Voltage   I(typ)   I(min)   I(max)
-1.5V     -852.5mA   -863.7mA   -854.8mA
-984.4mV  -185.7mA   -271mA     -105.6mA
-935.2mV  -123.6mA   -214.5mA   -62.78mA
-885.9mV  -71.93mA   -158.1mA   -45.72mA
-836.7mV  -41.29mA   -103.4mA   -37.18mA
-787.5mV  -28.06mA   -59.45mA   -30.09mA
-738.3mV  -21.49mA   -32.42mA   -23.67mA
-689.1mV  -16.88mA   -19.73mA   -18.12mA
-541.4mV  -8.34mA    -8.6mA     -7.922mA
1.078V    8.054mA    7.926mA    7.536mA
1.453V    8.469mA    0A         7.897mA
3V        0A         0A         0A
[POWER Clamp]
| Voltage   I(typ)   I(min)   I(max)
-1.5V     9.355mA    9.166mA    8.359mA
-1.427V   8.863mA    9.029mA    8.176mA
-1.28V    8.715mA    8.593mA    8.132mA
-49.22mV  8.503mA    8.34mA     7.944mA
0V        0A         3.333mA    0A
46.88mV   0A         0A         0A
3V        0A         0A         0A
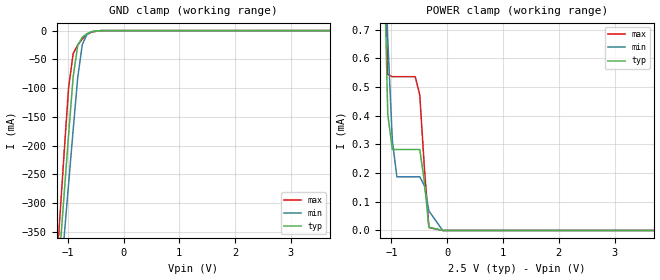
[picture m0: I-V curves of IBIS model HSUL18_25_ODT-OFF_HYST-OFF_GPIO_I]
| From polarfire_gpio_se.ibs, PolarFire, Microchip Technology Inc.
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|   HSUL18_25_ODT-OFF_HYST-OFF_GPIO_I
[Model]   HSUL18_25_ODT-OFF_HYST-OFF_GPIO_I
Model_type  Input
Vinl =   0.54
Vinh =   1.26
|   typ   min   max
C_comp_pullup   2.605e-12   2.605e-12   2.76e-12
C_comp_pulldown  2.605e-12   2.605e-12   2.76e-12
[Temperature Range]   25   100   -40
[Voltage Range]   2.5   2.375   2.625
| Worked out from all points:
|   GND clamp passes 1 mA (typ) near -0.52 V on its own axis
|   POWER clamp passes 1 mA (typ) near -1.14 V on its own axis
[GND Clamp]
| Voltage   I(typ)   I(min)   I(max)
-2.5V     -2.154A    -2.019A    -2.334A
-1.312V   -606.5mA   -644.5mA   -576.7mA
-1.148V   -394.1mA   -456mA     -335.8mA
-1.066V   -288mA     -361.7mA   -215.7mA
-984.4mV  -181.9mA   -267.4mA   -99.94mA
-902.3mV  -80.78mA   -173.2mA   -40.34mA
-820.3mV  -25.8mA    -81.78mA   -25.07mA
-738.3mV  -11.65mA   -24.31mA   -14.68mA
-656.2mV  -5.525mA   -6.674mA   -7.068mA
-574.2mV  -1.954mA   -1.999mA   -2.52mA
-410.2mV  -41.8uA    -66.55uA   -50.18uA
5V        0A         0A         0A
[POWER Clamp]
| Voltage   I(typ)   I(min)   I(max)
-2.5V     57.18mA    37.97mA    84.34mA
-1.148V   1.09mA     1.13mA     1.225mA
-1.066V   406uA      669.3uA    543.6uA
-984.4mV  282.4uA    314.7uA    536.4uA
-902.3mV  282.4uA    187.2uA    536.4uA
-574.2mV  282.4uA    187.2uA    536.4uA
-492.2mV  282.4uA    187.2uA    472.6uA
-410.2mV  170.3uA    156.5uA    220uA
-328.1mV  11.03uA    68.05uA    10.34uA
-82.03mV  1.223nA    91.77nA    2.882nA
5V        0A         0A         0A
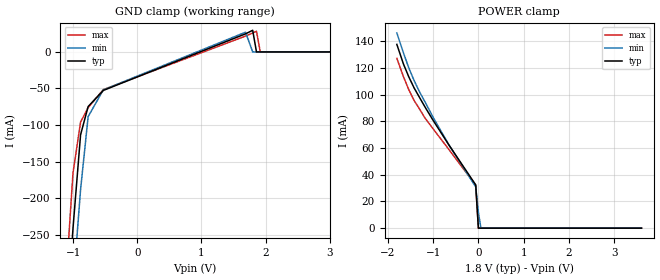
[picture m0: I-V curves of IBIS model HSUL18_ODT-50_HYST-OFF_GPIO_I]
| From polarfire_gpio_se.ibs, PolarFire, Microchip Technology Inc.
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|   HSUL18_ODT-50_HYST-OFF_GPIO_I
[Model]   HSUL18_ODT-50_HYST-OFF_GPIO_I
Model_type  Input
Vinl =   0.54
Vinh =   1.26
|   typ   min   max
C_comp_pullup   2.605e-12   2.605e-12   2.76e-12
C_comp_pulldown  2.605e-12   2.605e-12   2.76e-12
[Temperature Range]   25   100   -40
[Voltage Range]   1.8   1.71   1.89
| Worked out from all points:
|   POWER clamp passes 1 mA (typ) near -0.00 V on its own axis
[GND Clamp]
| Voltage   I(typ)   I(min)   I(max)
-1.8V     -1.272A    -1.24A     -1.324A
-1.122V   -393.6mA   -459.4mA   -329.1mA
-1.063V   -317.2mA   -391.4mA   -244.2mA
-1.004V   -241.2mA   -323.4mA   -165.6mA
-885.9mV  -113.4mA   -188.3mA   -95.96mA
-767.8mV  -74.77mA   -88.51mA   -76.15mA
-531.6mV  -52.72mA   -51.99mA   -51.66mA
1.688V    24.74mA    26.97mA    21.65mA
1.8V      29.61mA    0A         25.91mA
1.859V    0A         0A         28.31mA
1.918V    0A         0A         0A
3.6V      0A         0A         0A
[POWER Clamp]
| Voltage   I(typ)   I(min)   I(max)
-1.8V     137.5mA    146.1mA    127.1mA
-1.654V   122.8mA    131.1mA    113.3mA
-1.536V   113.2mA    119.9mA    103.6mA
-1.417V   104.8mA    110.3mA    95.4mA
-1.299V   97.77mA    102mA      89.15mA
-1.181V   90.82mA    94.64mA    82.52mA
-1.004V   80.91mA    83.21mA    74.53mA
-649.7mV  62.18mA    62.27mA    58.77mA
-59.06mV  32.36mA    30.82mA    32.18mA
0V        0A         11.84mA    0A
56.25mV   0A         0A         0A
3.6V      0A         0A         0A
